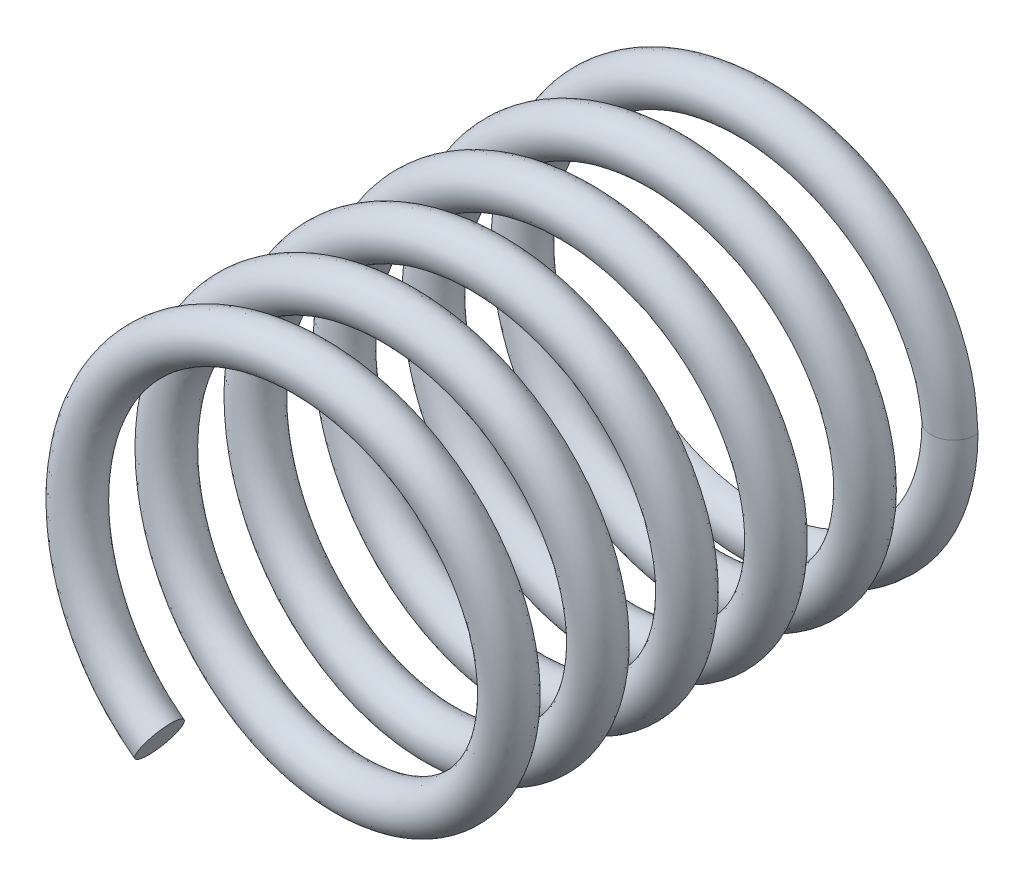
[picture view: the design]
ISO-10303-21;
HEADER;
FILE_DESCRIPTION(('STEP AP214'),'2;1');
FILE_NAME('part.step','',(''),(''),'','','');
FILE_SCHEMA(('AUTOMOTIVE_DESIGN { 1 0 10303 214 1 1 1 1 }'));
ENDSEC;
DATA;
#1=APPLICATION_CONTEXT('core data for automotive mechanical design processes');
#2=APPLICATION_PROTOCOL_DEFINITION('international standard','automotive_design',2000,#1);
#3=PRODUCT_CONTEXT('',#1,'mechanical');
#4=PRODUCT('Part','Part','',(#3));
#5=PRODUCT_RELATED_PRODUCT_CATEGORY('part','',(#4));
#6=PRODUCT_DEFINITION_FORMATION('','',#4);
#7=PRODUCT_DEFINITION_CONTEXT('part definition',#1,'design');
#8=PRODUCT_DEFINITION('design','',#6,#7);
#9=PRODUCT_DEFINITION_SHAPE('','',#8);
#10=(LENGTH_UNIT() NAMED_UNIT(*) SI_UNIT(.MILLI.,.METRE.));
#11=(NAMED_UNIT(*) PLANE_ANGLE_UNIT() SI_UNIT($,.RADIAN.));
#12=(NAMED_UNIT(*) SI_UNIT($,.STERADIAN.) SOLID_ANGLE_UNIT());
#13=UNCERTAINTY_MEASURE_WITH_UNIT(LENGTH_MEASURE(1.E-05),#10,'distance_accuracy_value','');
#14=(GEOMETRIC_REPRESENTATION_CONTEXT(3) GLOBAL_UNCERTAINTY_ASSIGNED_CONTEXT((#13)) GLOBAL_UNIT_ASSIGNED_CONTEXT((#10,
#11,#12)) REPRESENTATION_CONTEXT('',''));
#15=CARTESIAN_POINT('',(0.,0.,0.));
#16=DIRECTION('',(0.,0.,1.));
#17=DIRECTION('',(1.,0.,0.));
#18=AXIS2_PLACEMENT_3D('',#15,#16,#17);
#19=CARTESIAN_POINT('',(6.5,0.,0.75));
#20=CARTESIAN_POINT('',(6.47803879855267,0.400819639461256,0.779446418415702));
#21=CARTESIAN_POINT('',(6.43402565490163,1.20411505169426,0.838460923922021));
#22=CARTESIAN_POINT('',(6.09077083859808,2.36877362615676,0.92702323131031));
#23=CARTESIAN_POINT('',(5.55180292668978,3.45210939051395,1.0156581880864));
#24=CARTESIAN_POINT('',(4.81980996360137,4.41698855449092,1.10417552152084));
#25=CARTESIAN_POINT('',(3.92231791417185,5.22874283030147,1.19270781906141));
#26=CARTESIAN_POINT('',(2.89150520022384,5.86322878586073,1.28123286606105));
#27=CARTESIAN_POINT('',(1.76058421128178,6.29519397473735,1.36980802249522));
#28=CARTESIAN_POINT('',(0.569789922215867,6.51242937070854,1.45832328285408));
#29=CARTESIAN_POINT('',(-0.640762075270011,6.50545141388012,1.54688530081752));
#30=CARTESIAN_POINT('',(-1.82922132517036,6.27588442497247,1.63540445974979));
#31=CARTESIAN_POINT('',(-2.95512377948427,5.83112363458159,1.7239692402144));
#32=CARTESIAN_POINT('',(-3.97933162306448,5.18600612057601,1.81249157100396));
#33=CARTESIAN_POINT('',(-4.86779587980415,4.36377561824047,1.90104849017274));
#34=CARTESIAN_POINT('',(-5.58820585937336,3.39102061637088,1.98957838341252));
#35=CARTESIAN_POINT('',(-6.1186037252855,2.3028796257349,2.07812763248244));
#36=CARTESIAN_POINT('',(-6.43715274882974,1.13504232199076,2.16666656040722));
#37=CARTESIAN_POINT('',(-6.53735656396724,-0.0713012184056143,2.25520603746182));
#38=CARTESIAN_POINT('',(-6.41081294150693,-1.27520680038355,2.34375453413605));
#39=CARTESIAN_POINT('',(-6.06701483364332,-2.43582376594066,2.43228490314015));
#40=CARTESIAN_POINT('',(-5.51278706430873,-3.51206521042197,2.52084187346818));
#41=CARTESIAN_POINT('',(-4.77158359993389,-4.46903238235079,2.6093648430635));
#42=CARTESIAN_POINT('',(-3.86513544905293,-5.27143453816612,2.69792788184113));
#43=CARTESIAN_POINT('',(-2.82732227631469,-5.89439460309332,2.7864463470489));
#44=CARTESIAN_POINT('',(-1.69182218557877,-6.31408899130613,2.8750122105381));
#45=CARTESIAN_POINT('',(-0.498714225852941,-6.51811167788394,2.96352965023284));
#46=CARTESIAN_POINT('',(0.711695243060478,-6.4982025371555,3.05209471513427));
#47=CARTESIAN_POINT('',(1.89753943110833,-6.25544558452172,3.14061474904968));
#48=CARTESIAN_POINT('',(3.01860851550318,-5.79865604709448,3.22917549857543));
#49=CARTESIAN_POINT('',(4.03560159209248,-5.14220099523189,3.31770140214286));
#50=CARTESIAN_POINT('',(4.91518269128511,-4.31049178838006,3.40625489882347));
#51=CARTESIAN_POINT('',(5.62479780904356,-3.32981635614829,3.49478913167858));
#52=CARTESIAN_POINT('',(6.14342757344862,-2.23603196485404,3.58333348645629));
#53=CARTESIAN_POINT('',(6.44911757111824,-1.06474431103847,3.67187724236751));
#54=CARTESIAN_POINT('',(6.53619781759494,0.142601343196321,3.76041204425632));
#55=CARTESIAN_POINT('',(6.3965364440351,1.34507008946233,3.84896500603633));
#56=CARTESIAN_POINT('',(6.04003785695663,2.5018348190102,3.93749136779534));
#57=CARTESIAN_POINT('',(5.47419946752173,3.57202699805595,4.02605173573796));
#58=CARTESIAN_POINT('',(4.72248528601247,4.52074942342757,4.11457204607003));
#59=CARTESIAN_POINT('',(3.80746018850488,5.31336082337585,4.20313693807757));
#60=CARTESIAN_POINT('',(2.76280784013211,5.92477832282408,4.29165443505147));
#61=CARTESIAN_POINT('',(1.62287840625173,6.33228183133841,4.38022035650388));
#62=CARTESIAN_POINT('',(0.427573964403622,6.52303938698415,4.4687386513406));
#63=CARTESIAN_POINT('',(-0.78254677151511,6.49017803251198,4.55730197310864));
#64=CARTESIAN_POINT('',(-1.96563038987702,6.23426179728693,4.64582457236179));
#65=CARTESIAN_POINT('',(-3.08173197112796,5.76549033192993,4.73438200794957));
#66=CARTESIAN_POINT('',(-4.0913981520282,5.09779625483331,4.82291183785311));
#67=CARTESIAN_POINT('',(-4.9619760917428,4.25668531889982,4.91146091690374));
#68=CARTESIAN_POINT('',(-5.66073777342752,3.26822675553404,4.999999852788));
#69=CARTESIAN_POINT('',(-6.1674919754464,2.16890628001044,5.08853938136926));
#70=CARTESIAN_POINT('',(-6.46033993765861,0.994324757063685,5.17708788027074));
#71=CARTESIAN_POINT('',(-6.53422990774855,-0.213884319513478,5.26561823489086));
#72=CARTESIAN_POINT('',(-6.38152240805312,-1.41477755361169,5.35417520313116));
#73=CARTESIAN_POINT('',(-6.01232098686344,-2.56753904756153,5.44269817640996));
#74=CARTESIAN_POINT('',(-5.43497604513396,-3.63157394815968,5.53126121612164));
#75=CARTESIAN_POINT('',(-4.67281556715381,-4.57191794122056,5.61977968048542));
#76=CARTESIAN_POINT('',(-3.7493384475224,-5.35466556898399,5.70834554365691));
#77=CARTESIAN_POINT('',(-2.69796356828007,-5.95445113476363,5.79686298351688));
#78=CARTESIAN_POINT('',(-1.5537413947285,-6.34972708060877,5.88542804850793));
#79=CARTESIAN_POINT('',(-0.356384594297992,-6.52719276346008,5.97394808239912));
#80=CARTESIAN_POINT('',(0.853306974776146,-6.48137921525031,6.06250883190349));
#81=CARTESIAN_POINT('',(2.0334887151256,-6.2123453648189,6.1510347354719));
#82=CARTESIAN_POINT('',(3.14448588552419,-5.73162881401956,6.23958823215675));
#83=CARTESIAN_POINT('',(4.14671672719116,-5.05279801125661,6.32812246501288));
#84=CARTESIAN_POINT('',(5.00816558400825,-4.20235871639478,6.41666681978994));
#85=CARTESIAN_POINT('',(5.69602419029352,-3.206260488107,6.50521057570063));
#86=CARTESIAN_POINT('',(6.19078938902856,-2.10150988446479,6.59374537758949));
#87=CARTESIAN_POINT('',(6.47081915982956,-0.923791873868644,6.6822983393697));
#88=CARTESIAN_POINT('',(6.53145690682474,0.285141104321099,6.77082470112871));
#89=CARTESIAN_POINT('',(6.36577003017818,1.48432092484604,6.85938506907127));
#90=CARTESIAN_POINT('',(5.98387194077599,2.63292977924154,6.94790537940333));
#91=CARTESIAN_POINT('',(5.3951186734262,3.69069787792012,7.0364702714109));
#92=CARTESIAN_POINT('',(4.62258367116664,4.62253453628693,7.1249877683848));
#93=CARTESIAN_POINT('',(3.69077480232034,5.39534140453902,7.2135536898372));
#94=CARTESIAN_POINT('',(2.63279896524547,5.98341306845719,7.30207198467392));
#95=CARTESIAN_POINT('',(1.4844181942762,6.36641916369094,7.39063530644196));
#96=CARTESIAN_POINT('',(0.285154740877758,6.53057499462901,7.4791579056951));
#97=CARTESIAN_POINT('',(-0.923966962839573,6.47180313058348,7.56771534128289));
#98=CARTESIAN_POINT('',(-2.10110764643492,6.1897021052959,7.65624517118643));
#99=CARTESIAN_POINT('',(-3.20686019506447,5.69707155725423,7.74479425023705));
#100=CARTESIAN_POINT('',(-4.20155413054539,5.00721490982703,7.83333318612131));
#101=CARTESIAN_POINT('',(-5.05373706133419,4.14751171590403,7.92187271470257));
#102=CARTESIAN_POINT('',(-5.73065467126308,3.14392602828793,8.01042121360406));
#103=CARTESIAN_POINT('',(-6.213320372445,2.03385273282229,8.09895156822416));
#104=CARTESIAN_POINT('',(-6.48055193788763,0.853153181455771,8.18750853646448));
#105=CARTESIAN_POINT('',(-6.52788373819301,-0.356362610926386,8.27603150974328));
#106=CARTESIAN_POINT('',(-6.34927832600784,-1.55369195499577,8.36459454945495));
#107=CARTESIAN_POINT('',(-5.95469833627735,-2.69800050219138,8.45311301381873));
#108=CARTESIAN_POINT('',(-5.35462915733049,-3.74939044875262,8.54167887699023));
#109=CARTESIAN_POINT('',(-4.57179868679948,-4.67259590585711,8.6301963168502));
#110=CARTESIAN_POINT('',(-3.63177388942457,-5.43538082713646,8.71876138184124));
#111=CARTESIAN_POINT('',(-2.56732337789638,-6.01166416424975,8.80728141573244));
#112=CARTESIAN_POINT('',(-1.41491598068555,-6.3823523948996,8.8958421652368));
#113=CARTESIAN_POINT('',(-0.213892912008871,-6.53318919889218,8.98436806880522));
#114=CARTESIAN_POINT('',(0.994517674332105,-6.46144681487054,9.07292156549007));
#115=CARTESIAN_POINT('',(2.16848040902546,-6.16633765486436,9.1614557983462));
#116=CARTESIAN_POINT('',(3.26884491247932,-5.66181898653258,9.25000015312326));
#117=CARTESIAN_POINT('',(4.25590622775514,-4.96105433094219,9.33854390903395));
#118=CARTESIAN_POINT('',(5.09868039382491,-4.09214800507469,9.42707871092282));
#119=CARTESIAN_POINT('',(5.76462558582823,-3.08123090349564,9.51563167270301));
#120=CARTESIAN_POINT('',(6.23508585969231,-1.96594483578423,9.60415803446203));
#121=CARTESIAN_POINT('',(6.48953477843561,-0.782416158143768,9.69271840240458));
#122=CARTESIAN_POINT('',(6.52351532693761,0.427539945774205,9.78123871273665));
#123=CARTESIAN_POINT('',(6.33204622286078,1.62288229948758,9.86980360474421));
#124=CARTESIAN_POINT('',(5.92480768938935,2.76274486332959,9.95832110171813));
#125=CARTESIAN_POINT('',(5.31350928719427,3.80764317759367,10.0468870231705));
#126=CARTESIAN_POINT('',(4.52046955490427,4.72209882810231,10.1354053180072));
#127=CARTESIAN_POINT('',(3.57234041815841,5.4747761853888,10.2239686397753));
#128=CARTESIAN_POINT('',(2.50154600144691,6.03920446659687,10.3124912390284));
#129=CARTESIAN_POINT('',(1.34524209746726,6.39752095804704,10.4010486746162));
#130=CARTESIAN_POINT('',(0.142607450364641,6.53503853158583,10.4895785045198));
#131=CARTESIAN_POINT('',(-1.06494963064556,6.45030688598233,10.5781275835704));
#132=CARTESIAN_POINT('',(-2.23560105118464,6.14225904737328,10.6666665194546));
#133=CARTESIAN_POINT('',(-3.3304268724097,5.62586602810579,10.7552060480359));
#134=CARTESIAN_POINT('',(-4.30976787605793,4.91432342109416,10.8437545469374));
#135=CARTESIAN_POINT('',(-5.14299270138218,4.0362771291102,10.9322849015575));
#136=CARTESIAN_POINT('',(-5.79793126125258,3.01818105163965,11.0208418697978));
#137=CARTESIAN_POINT('',(-6.25608736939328,1.89779641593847,11.1093648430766));
#138=CARTESIAN_POINT('',(-6.49776393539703,0.711588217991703,11.1979278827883));
#139=CARTESIAN_POINT('',(-6.51835660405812,-0.498664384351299,11.2864463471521));
#140=CARTESIAN_POINT('',(-6.31407256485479,-1.69188350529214,11.3750122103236));
#141=CARTESIAN_POINT('',(-5.89420741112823,-2.82715665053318,11.4635296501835));
#142=CARTESIAN_POINT('',(-5.27176085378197,-3.86544742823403,11.5520947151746));
#143=CARTESIAN_POINT('',(-4.46860507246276,-4.77104014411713,11.6406147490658));
#144=CARTESIAN_POINT('',(-3.51247918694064,-5.51351968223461,11.7291754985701));
#145=CARTESIAN_POINT('',(-2.43547589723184,-6.06603399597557,11.8177014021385));
#146=CARTESIAN_POINT('',(-1.27540404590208,-6.41191896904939,11.9062548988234));
#147=CARTESIAN_POINT('',(-0.071306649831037,-6.53612597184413,11.9947891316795));
#148=CARTESIAN_POINT('',(1.13525330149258,-6.43838032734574,12.0833334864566));
#149=CARTESIAN_POINT('',(2.30246316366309,-6.11747180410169,12.1718772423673));
#150=CARTESIAN_POINT('',(3.39159529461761,-5.58921268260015,12.2604120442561));
#151=CARTESIAN_POINT('',(4.36313308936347,-4.86702801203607,12.3489650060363));
#152=CARTESIAN_POINT('',(5.18667143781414,-3.97990881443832,12.4374913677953));
#153=CARTESIAN_POINT('',(5.83056585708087,-2.95478230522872,12.5260517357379));
#154=CARTESIAN_POINT('',(6.2763264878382,-1.82941751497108,12.61457204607));
#155=CARTESIAN_POINT('',(6.50523554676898,-0.640676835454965,12.7031369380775));
#156=CARTESIAN_POINT('',(6.51241245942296,0.569727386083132,12.7916544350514));
#157=CARTESIAN_POINT('',(6.29535613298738,1.76068698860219,12.8802203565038));
#158=CARTESIAN_POINT('',(5.86290480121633,2.89122977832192,12.9687386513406));
#159=CARTESIAN_POINT('',(5.22938566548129,3.92279440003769,13.0573019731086));
#160=CARTESIAN_POINT('',(4.41621389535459,4.81941675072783,13.1458245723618));
#161=CARTESIAN_POINT('',(3.45219510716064,5.55160334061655,13.2343820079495));
#162=CARTESIAN_POINT('',(2.36912198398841,6.09215286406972,13.3229118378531));
#163=CARTESIAN_POINT('',(1.20540957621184,6.42554000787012,13.4114609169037));
#164=CARTESIAN_POINT('',(-1.49109357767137E-06,6.53645609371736,13.499999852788));
#165=CARTESIAN_POINT('',(-1.20541805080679,6.4256578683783,13.5885393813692));
#166=CARTESIAN_POINT('',(-2.36905946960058,6.0919808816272,13.6770878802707));
#167=CARTESIAN_POINT('',(-3.45234420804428,5.55186693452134,13.7656182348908));
#168=CARTESIAN_POINT('',(-4.41599450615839,4.81917174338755,13.8541752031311));
#169=CARTESIAN_POINT('',(-5.22971453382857,3.92305318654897,13.9426981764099));
#170=CARTESIAN_POINT('',(-5.86252331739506,2.89104034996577,14.0312612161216));
#171=CARTESIAN_POINT('',(-6.29580486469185,1.76081801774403,14.1197796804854));
#172=CARTESIAN_POINT('',(-6.51194563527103,0.569689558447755,14.2083455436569));
#173=CARTESIAN_POINT('',(-6.50568773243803,-0.640720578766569,14.2968629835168));
#174=CARTESIAN_POINT('',(-6.27589565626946,-1.82928402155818,14.3854280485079));
#175=CARTESIAN_POINT('',(-5.83090704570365,-2.95495826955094,14.473948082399));
#176=CARTESIAN_POINT('',(-5.18638556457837,-3.97967512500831,14.5625088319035));
#177=CARTESIAN_POINT('',(-4.36330454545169,-4.86722556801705,14.6510347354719));
#178=CARTESIAN_POINT('',(-3.39149321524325,-5.58901906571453,14.7395882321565));
#179=CARTESIAN_POINT('',(-2.3024930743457,-6.11756103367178,14.8281224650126));
#180=CARTESIAN_POINT('',(-1.13526661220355,-6.43837798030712,14.9166668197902));
#181=CARTESIAN_POINT('',(0.0713090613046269,-6.53603189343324,15.0052105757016));
#182=CARTESIAN_POINT('',(1.27543374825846,-6.4121358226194,15.0937453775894));
#183=CARTESIAN_POINT('',(2.43538234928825,-6.06578971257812,15.1822983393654));
#184=CARTESIAN_POINT('',(3.51266789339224,-5.51383705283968,15.2708247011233));
#185=CARTESIAN_POINT('',(4.46834464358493,-4.77075809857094,15.3593850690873));
#186=CARTESIAN_POINT('',(5.27212004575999,-3.86572022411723,15.4479053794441));
#187=CARTESIAN_POINT('',(5.89379745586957,-2.82696088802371,15.5364702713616));
#188=CARTESIAN_POINT('',(6.31452417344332,-1.69200762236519,15.6249877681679));
#189=CARTESIAN_POINT('',(6.51789012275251,-0.498634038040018,15.7135536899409));
#190=CARTESIAN_POINT('',(6.49818720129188,0.711635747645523,15.8020719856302));
#191=CARTESIAN_POINT('',(6.25568981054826,1.89766571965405,15.8906353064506));
#192=CARTESIAN_POINT('',(5.79822122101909,3.0183362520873,15.9791579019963));
#193=CARTESIAN_POINT('',(5.14276249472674,4.036080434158,16.0677153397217));
#194=CARTESIAN_POINT('',(4.30988543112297,4.91446361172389,16.1562451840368));
#195=CARTESIAN_POINT('',(3.33037839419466,5.62575801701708,16.244794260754));
#196=CARTESIAN_POINT('',(2.23559824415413,6.14226028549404,16.3333331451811));
#197=CARTESIAN_POINT('',(1.06498238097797,6.45042149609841,16.4218726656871));
#198=CARTESIAN_POINT('',(-0.142607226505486,6.53485456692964,16.5104213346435));
#199=CARTESIAN_POINT('',(-1.34529177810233,6.39781606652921,16.5989517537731));
#200=CARTESIAN_POINT('',(-2.50142564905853,6.03890224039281,16.687508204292));
#201=CARTESIAN_POINT('',(-3.57256720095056,5.47514244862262,16.7760309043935));
#202=CARTESIAN_POINT('',(-4.52016795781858,4.72178283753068,16.8645954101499));
#203=CARTESIAN_POINT('',(-5.313853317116,3.80789649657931,16.9531147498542));
#204=CARTESIAN_POINT('',(-5.92440386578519,2.76256665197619,17.0416766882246));
#205=CARTESIAN_POINT('',(-6.33260379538,1.62302507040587,17.1301918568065));
#206=CARTESIAN_POINT('',(-6.52301737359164,0.427468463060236,17.2187672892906));
#207=CARTESIAN_POINT('',(-6.48959308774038,-0.782443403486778,17.3072919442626));
#208=CARTESIAN_POINT('',(-6.23484691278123,-1.96563514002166,17.3958249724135));
#209=CARTESIAN_POINT('',(-5.765579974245,-3.0815324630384,17.4843401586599));
#210=CARTESIAN_POINT('',(-5.09797767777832,-4.09263332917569,17.5729822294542));
#211=CARTESIAN_POINT('',(-4.25486215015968,-4.96096647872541,17.6615197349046));
#212=CARTESIAN_POINT('',(-3.59661837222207,-5.42889327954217,17.7205943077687));
#213=CARTESIAN_POINT('',(-3.24993433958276,-5.62905139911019,17.7499999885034));
#214=CARTESIAN_POINT('',(8.,0.,0.75));
#215=CARTESIAN_POINT('',(7.97295207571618,0.493790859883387,0.779474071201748));
#216=CARTESIAN_POINT('',(7.91874446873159,1.48341285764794,0.838543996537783));
#217=CARTESIAN_POINT('',(7.49731211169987,2.91277065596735,0.926948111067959));
#218=CARTESIAN_POINT('',(6.83246371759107,4.24994089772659,1.01627020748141));
#219=CARTESIAN_POINT('',(5.93260444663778,5.43560340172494,1.103905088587));
#220=CARTESIAN_POINT('',(4.82616965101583,6.43653315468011,1.19308333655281));
#221=CARTESIAN_POINT('',(3.56093396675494,7.21523217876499,1.28090952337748));
#222=CARTESIAN_POINT('',(2.16491457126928,7.74863220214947,1.37048079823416));
#223=CARTESIAN_POINT('',(0.703343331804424,8.01512891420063,1.45798266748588));
#224=CARTESIAN_POINT('',(-0.790784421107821,8.00660569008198,1.54745582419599));
#225=CARTESIAN_POINT('',(-2.2494462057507,7.72477534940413,1.63509786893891));
#226=CARTESIAN_POINT('',(-3.63881967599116,7.17597396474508,1.7245404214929));
#227=CARTESIAN_POINT('',(-4.89648252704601,6.38376586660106,1.81229025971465));
#228=CARTESIAN_POINT('',(-5.99209324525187,5.36979751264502,1.90148160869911));
#229=CARTESIAN_POINT('',(-6.87743679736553,4.17434793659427,1.98952237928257));
#230=CARTESIAN_POINT('',(-7.53079320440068,2.83382067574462,2.07837975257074));
#231=CARTESIAN_POINT('',(-7.92276623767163,1.39700622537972,2.16679821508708));
#232=CARTESIAN_POINT('',(-8.04597328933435,-0.0872066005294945,2.25521790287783));
#233=CARTESIAN_POINT('',(-7.89021161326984,-1.57032986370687,2.34407206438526));
#234=CARTESIAN_POINT('',(-7.46759523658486,-2.99662700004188,2.43210914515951));
#235=CARTESIAN_POINT('',(-6.78429262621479,-4.32389491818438,2.52130818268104));
#236=CARTESIAN_POINT('',(-5.87402862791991,-5.4989225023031,2.60907094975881));
#237=CARTESIAN_POINT('',(-4.75560388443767,-6.48919421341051,2.69849283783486));
#238=CARTESIAN_POINT('',(-3.48173292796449,-7.2537082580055,2.7861022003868));
#239=CARTESIAN_POINT('',(-2.08020057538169,-7.77186524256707,2.87562009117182));
#240=CARTESIAN_POINT('',(-0.615901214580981,-8.02216582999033,2.96319856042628));
#241=CARTESIAN_POINT('',(0.877999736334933,-7.9976576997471,3.05268457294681));
#242=CARTESIAN_POINT('',(2.33375040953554,-7.6995901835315,3.14035513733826));
#243=CARTESIAN_POINT('',(3.7167401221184,-7.13608085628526,3.22968170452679));
#244=CARTESIAN_POINT('',(4.96599562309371,-6.32968645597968,3.31756631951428));
#245=CARTESIAN_POINT('',(6.05013771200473,-5.3044901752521,3.40660784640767));
#246=CARTESIAN_POINT('',(6.92269785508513,-4.09867415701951,3.49482466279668));
#247=CARTESIAN_POINT('',(7.56114144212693,-2.75204742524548,3.58346480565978));
#248=CARTESIAN_POINT('',(7.93757563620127,-1.31005914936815,3.67210435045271));
#249=CARTESIAN_POINT('',(8.0445540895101,0.174494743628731,3.76032173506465));
#250=CARTESIAN_POINT('',(7.87256467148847,1.65667121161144,3.8493627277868));
#251=CARTESIAN_POINT('',(7.43452501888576,3.07759402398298,3.93724780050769));
#252=CARTESIAN_POINT('',(6.73664555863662,4.39789819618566,4.02657398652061));
#253=CARTESIAN_POINT('',(5.81372635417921,5.56248653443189,4.11424482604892));
#254=CARTESIAN_POINT('',(4.68449301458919,6.54084800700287,4.2037306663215));
#255=CARTESIAN_POINT('',(3.40235088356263,7.29113640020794,4.2913091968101));
#256=CARTESIAN_POINT('',(1.99533934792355,7.79421871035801,4.38082714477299));
#257=CARTESIAN_POINT('',(0.528216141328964,8.02827827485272,4.46843632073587));
#258=CARTESIAN_POINT('',(-0.96504926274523,7.98775983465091,4.55785848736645));
#259=CARTESIAN_POINT('',(-2.41780695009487,7.67347355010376,4.6456209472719));
#260=CARTESIAN_POINT('',(-3.79414503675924,7.09537497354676,4.73482049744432));
#261=CARTESIAN_POINT('',(-5.03496605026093,6.2748254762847,4.82285682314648));
#262=CARTESIAN_POINT('',(-6.10740772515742,5.2386037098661,4.91171122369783));
#263=CARTESIAN_POINT('',(-6.96716080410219,4.02250216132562,5.00013117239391));
#264=CARTESIAN_POINT('',(-7.59056795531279,2.66993739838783,5.08855171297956));
#265=CARTESIAN_POINT('',(-7.95145798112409,1.22298393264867,5.177405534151));
#266=CARTESIAN_POINT('',(-8.04215098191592,-0.261840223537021,5.26544238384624));
#267=CARTESIAN_POINT('',(-7.85400891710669,-1.74276742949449,5.35464146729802));
#268=CARTESIAN_POINT('',(-7.40052360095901,-3.15826080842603,5.44240430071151));
#269=CARTESIAN_POINT('',(-6.68824100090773,-4.47133558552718,5.53182618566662));
#270=CARTESIAN_POINT('',(-5.75267308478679,-5.62543332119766,5.61943553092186));
#271=CARTESIAN_POINT('',(-4.61288359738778,-6.59169392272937,5.70895342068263));
#272=CARTESIAN_POINT('',(-3.32250013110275,-7.32771941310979,5.79653189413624));
#273=CARTESIAN_POINT('',(-1.91031015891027,-7.81563351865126,5.88601790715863));
#274=CARTESIAN_POINT('',(-0.440406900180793,-8.03343772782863,5.97368847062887));
#275=CARTESIAN_POINT('',(1.05190986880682,-7.97692251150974,6.06301503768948));
#276=CARTESIAN_POINT('',(2.50162917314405,-7.64643018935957,6.15089965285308));
#277=CARTESIAN_POINT('',(3.87102727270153,-7.05385924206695,6.23994117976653));
#278=CARTESIAN_POINT('',(5.10337896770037,-6.21919597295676,6.32815799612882));
#279=CARTESIAN_POINT('',(6.16389316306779,-5.17214133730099,6.41679813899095));
#280=CARTESIAN_POINT('',(7.010814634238,-3.94586367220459,6.50543768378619));
#281=CARTESIAN_POINT('',(7.61908883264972,-2.58742811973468,6.59365506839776));
#282=CARTESIAN_POINT('',(7.96440585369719,-1.13581398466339,6.68269606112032));
#283=CARTESIAN_POINT('',(8.03876744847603,0.349235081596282,6.77058113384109));
#284=CARTESIAN_POINT('',(7.83454589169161,1.82860400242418,6.85990731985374));
#285=CARTESIAN_POINT('',(7.36559819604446,3.23861602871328,6.94757815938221));
#286=CARTESIAN_POINT('',(6.63908529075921,4.54419563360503,7.03706399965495));
#287=CARTESIAN_POINT('',(5.6908795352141,5.6877545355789,7.12464253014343));
#288=CARTESIAN_POINT('',(4.54078546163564,6.64172355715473,7.21416047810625));
#289=CARTESIAN_POINT('',(3.24219369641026,7.36345329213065,7.30176965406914));
#290=CARTESIAN_POINT('',(1.82512509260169,7.83610526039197,7.39119182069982));
#291=CARTESIAN_POINT('',(0.352487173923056,8.03764515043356,7.47895428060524));
#292=CARTESIAN_POINT('',(-1.13856892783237,7.96514553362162,7.56815383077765));
#293=CARTESIAN_POINT('',(-2.5852037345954,7.61846700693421,7.65619015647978));
#294=CARTESIAN_POINT('',(-3.94737797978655,7.01153371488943,7.74504455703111));
#295=CARTESIAN_POINT('',(-5.17121282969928,6.16282493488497,7.83346450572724));
#296=CARTESIAN_POINT('',(-6.21962832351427,5.10504761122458,7.92188504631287));
#297=CARTESIAN_POINT('',(-7.05364124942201,3.86878777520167,8.01073886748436));
#298=CARTESIAN_POINT('',(-7.64670456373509,2.50452830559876,8.09877571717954));
#299=CARTESIAN_POINT('',(-7.97641578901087,1.04856356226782,8.1879748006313));
#300=CARTESIAN_POINT('',(-8.03440623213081,-0.436666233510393,8.27573763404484));
#301=CARTESIAN_POINT('',(-7.81417755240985,-1.91416790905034,8.36515951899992));
#302=CARTESIAN_POINT('',(-7.32975595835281,-3.31864810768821,8.45276886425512));
#303=CARTESIAN_POINT('',(-6.58918477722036,-4.61646702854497,8.54228675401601));
#304=CARTESIAN_POINT('',(-5.62835649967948,-5.74944188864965,8.62986522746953));
#305=CARTESIAN_POINT('',(-4.46820845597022,-6.69092858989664,8.71935124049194));
#306=CARTESIAN_POINT('',(-3.16144463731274,-7.39833412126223,8.80702180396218));
#307=CARTESIAN_POINT('',(-1.73979623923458,-7.8556295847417,8.89634837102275));
#308=CARTESIAN_POINT('',(-0.264470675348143,-8.04090159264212,8.98423298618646));
#309=CARTESIAN_POINT('',(1.22501381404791,-7.95242878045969,9.07327451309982));
#310=CARTESIAN_POINT('',(2.66851725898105,-7.58959096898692,9.16149132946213));
#311=CARTESIAN_POINT('',(4.02318839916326,-6.96839867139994,9.25013147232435));
#312=CARTESIAN_POINT('',(5.23844591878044,-6.10573880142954,9.33877101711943));
#313=CARTESIAN_POINT('',(6.27464901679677,-5.03726896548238,9.42698840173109));
#314=CARTESIAN_POINT('',(7.09562214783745,-3.79130325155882,9.51602939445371));
#315=CARTESIAN_POINT('',(7.67341588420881,-2.42124676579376,9.60391446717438));
#316=CARTESIAN_POINT('',(7.98748436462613,-0.961246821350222,9.69324065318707));
#317=CARTESIAN_POINT('',(8.02907019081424,0.524120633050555,9.78091149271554));
#318=CARTESIAN_POINT('',(7.79290589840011,1.99944620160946,9.87039733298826));
#319=CARTESIAN_POINT('',(7.29300412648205,3.39834553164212,9.95797586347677));
#320=CARTESIAN_POINT('',(6.53854583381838,4.68813852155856,10.0474938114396));
#321=CARTESIAN_POINT('',(5.5651148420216,5.81048716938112,10.1351029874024));
#322=CARTESIAN_POINT('',(4.39516242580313,6.73930074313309,10.2245251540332));
#323=CARTESIAN_POINT('',(3.08026614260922,7.43235812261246,10.3122876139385));
#324=CARTESIAN_POINT('',(1.65433539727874,7.87420198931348,10.4014871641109));
#325=CARTESIAN_POINT('',(0.17637230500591,8.0432089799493,10.4895234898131));
#326=CARTESIAN_POINT('',(-1.31123619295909,7.93876927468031,10.5783778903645));
#327=CARTESIAN_POINT('',(-2.75154026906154,7.55982006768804,10.6667978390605));
#328=CARTESIAN_POINT('',(-4.0985097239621,6.9244137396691,10.7552183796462));
#329=CARTESIAN_POINT('',(-5.30505128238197,6.04795871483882,10.8440722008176));
#330=CARTESIAN_POINT('',(-6.32895272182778,4.9688137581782,10.9321090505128));
#331=CARTESIAN_POINT('',(-7.13674919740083,3.71342231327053,11.0213081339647));
#332=CARTESIAN_POINT('',(-7.69922089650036,2.33759673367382,11.1090709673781));
#333=CARTESIAN_POINT('',(-7.99760896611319,0.873876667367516,11.1984928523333));
#334=CARTESIAN_POINT('',(-8.02276208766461,-0.611584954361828,11.2861021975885));
#335=CARTESIAN_POINT('',(-7.77073302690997,-2.08442607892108,11.3756200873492));
#336=CARTESIAN_POINT('',(-7.25535000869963,-3.47769681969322,11.463198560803));
#337=CARTESIAN_POINT('',(-6.48717486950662,-4.75919892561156,11.5526845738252));
#338=CARTESIAN_POINT('',(-5.50116549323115,-5.87088223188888,11.6403551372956));
#339=CARTESIAN_POINT('',(-4.32165724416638,-6.78683179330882,11.7296817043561));
#340=CARTESIAN_POINT('',(-2.99867145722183,-7.46552159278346,11.8175663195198));
#341=CARTESIAN_POINT('',(-1.56875438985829,-7.89181804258,11.9066078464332));
#342=CARTESIAN_POINT('',(-0.0882070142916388,-8.04456928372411,11.9948246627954));
#343=CARTESIAN_POINT('',(1.39722773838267,-7.9241642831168,12.0834648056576));
#344=CARTESIAN_POINT('',(2.83424331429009,-7.5291717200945,12.1721043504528));
#345=CARTESIAN_POINT('',(4.17339392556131,-6.87954083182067,12.2603217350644));
#346=CARTESIAN_POINT('',(5.37100169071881,-5.9895053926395,12.349362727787));
#347=CARTESIAN_POINT('',(6.3825371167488,-4.89969051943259,12.4372478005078));
#348=CARTESIAN_POINT('',(7.17701434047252,-3.63515709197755,12.5265739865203));
#349=CARTESIAN_POINT('',(7.72411782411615,-2.25359144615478,12.6142448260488));
#350=CARTESIAN_POINT('',(8.00678704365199,-0.786465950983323,12.7037306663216));
#351=CARTESIAN_POINT('',(8.01548478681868,0.699045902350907,12.7913091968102));
#352=CARTESIAN_POINT('',(7.74766107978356,2.1690947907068,12.8808271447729));
#353=CARTESIAN_POINT('',(7.21680100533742,3.55669054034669,12.9684363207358));
#354=CARTESIAN_POINT('',(6.43507830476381,4.82963709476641,13.0578584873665));
#355=CARTESIAN_POINT('',(5.43651955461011,5.93061901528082,13.1456209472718));
#356=CARTESIAN_POINT('',(4.24770245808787,6.83351347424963,13.2348204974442));
#357=CARTESIAN_POINT('',(2.91667524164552,7.49782124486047,13.3228568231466));
#358=CARTESIAN_POINT('',(1.48306003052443,7.90847209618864,13.4117112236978));
#359=CARTESIAN_POINT('',(8.6564343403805E-06,8.04498932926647,13.5001311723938));
#360=CARTESIAN_POINT('',(-1.48305036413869,7.90859337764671,13.5885517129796));
#361=CARTESIAN_POINT('',(-2.91659383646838,7.49765657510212,13.6774055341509));
#362=CARTESIAN_POINT('',(-4.24783577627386,6.8337869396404,13.7654423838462));
#363=CARTESIAN_POINT('',(-5.43628532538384,5.93038752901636,13.854641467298));
#364=CARTESIAN_POINT('',(-6.43539589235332,4.82991103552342,13.9424043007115));
#365=CARTESIAN_POINT('',(-7.21641070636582,3.55651882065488,14.0318261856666));
#366=CARTESIAN_POINT('',(-7.74810470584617,2.16924437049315,14.1194355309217));
#367=CARTESIAN_POINT('',(-8.0150161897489,0.699027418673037,14.2089534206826));
#368=CARTESIAN_POINT('',(-8.00724122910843,-0.786490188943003,14.2965318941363));
#369=CARTESIAN_POINT('',(-7.72369225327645,-2.2534396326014,14.3860179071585));
#370=CARTESIAN_POINT('',(-7.17736460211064,-3.63531530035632,14.4736884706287));
#371=CARTESIAN_POINT('',(-6.38226260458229,-4.89944192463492,14.5630150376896));
#372=CARTESIAN_POINT('',(-5.37118820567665,-5.98968950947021,14.6508996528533));
#373=CARTESIAN_POINT('',(-4.17330766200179,-6.87933757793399,14.7399411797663));
#374=CARTESIAN_POINT('',(-2.83429221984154,-7.52925381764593,14.8281579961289));
#375=CARTESIAN_POINT('',(-1.39725920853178,-7.92415873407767,14.9167981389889));
#376=CARTESIAN_POINT('',(0.088189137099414,-8.04447541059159,15.005437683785));
#377=CARTESIAN_POINT('',(1.56876593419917,-7.89203854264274,15.0936550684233));
#378=CARTESIAN_POINT('',(2.99855916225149,-7.46528478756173,15.1826960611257));
#379=CARTESIAN_POINT('',(4.32183017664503,-6.78715928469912,15.2705811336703));
#380=CARTESIAN_POINT('',(5.50089046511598,-5.87061376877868,15.359907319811));
#381=CARTESIAN_POINT('',(6.48752285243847,-4.7594871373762,15.447578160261));
#382=CARTESIAN_POINT('',(7.25493150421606,-3.47751869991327,15.5370640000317));
#383=CARTESIAN_POINT('',(7.77117968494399,-2.08456897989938,15.6246425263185));
#384=CARTESIAN_POINT('',(8.02229405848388,-0.611573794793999,15.7141604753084));
#385=CARTESIAN_POINT('',(7.99803446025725,0.873904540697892,15.8017696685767));
#386=CARTESIAN_POINT('',(7.69882874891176,2.3374479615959,15.8911918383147));
#387=CARTESIAN_POINT('',(7.13704847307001,3.7135597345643,15.9789542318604));
#388=CARTESIAN_POINT('',(6.32873399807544,4.96860235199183,16.0681537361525));
#389=CARTESIAN_POINT('',(5.30518408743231,6.04808557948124,16.1561902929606));
#390=CARTESIAN_POINT('',(4.09847709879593,6.92429631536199,16.2450450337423));
#391=CARTESIAN_POINT('',(2.75155666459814,7.55981431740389,16.333464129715));
#392=CARTESIAN_POINT('',(1.31128690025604,7.93888099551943,16.4218831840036));
#393=CARTESIAN_POINT('',(-0.176352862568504,8.04302538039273,16.510739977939));
#394=CARTESIAN_POINT('',(-1.65436541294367,7.87450097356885,16.5987812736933));
#395=CARTESIAN_POINT('',(-3.08012197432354,7.43206571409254,16.6879721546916));
#396=CARTESIAN_POINT('',(-4.39537808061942,6.73967606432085,16.7757223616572));
#397=CARTESIAN_POINT('',(-5.56481727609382,5.81016717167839,16.8651646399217));
#398=CARTESIAN_POINT('',(-6.53886971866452,4.68841307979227,16.9528068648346));
#399=CARTESIAN_POINT('',(-7.2925446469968,3.39827103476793,17.0422799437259));
#400=CARTESIAN_POINT('',(-7.79349204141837,1.99961168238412,17.1297817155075));
#401=CARTESIAN_POINT('',(-8.02854961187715,0.523714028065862,17.2193532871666));
#402=CARTESIAN_POINT('',(-7.98768554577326,-0.961165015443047,17.3071790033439));
#403=CARTESIAN_POINT('',(-7.67269823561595,-2.42047340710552,17.3963582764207));
#404=CARTESIAN_POINT('',(-7.09946791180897,-3.78998300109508,17.4839899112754));
#405=CARTESIAN_POINT('',(-6.26263456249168,-5.04507880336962,17.5733232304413));
#406=CARTESIAN_POINT('',(-5.27545103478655,-6.08339191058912,17.6616872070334));
#407=CARTESIAN_POINT('',(-4.34665518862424,-6.7279101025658,17.7208552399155));
#408=CARTESIAN_POINT('',(-3.99995103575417,-6.92807983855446,17.7502626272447));
#409=CARTESIAN_POINT('',(8.,0.,-0.75));
#410=CARTESIAN_POINT('',(7.97297969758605,0.49379359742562,-0.720525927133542));
#411=CARTESIAN_POINT('',(7.91882744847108,1.48342108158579,-0.661455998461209));
#412=CARTESIAN_POINT('',(7.49723522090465,2.91277308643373,-0.573051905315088));
#413=CARTESIAN_POINT('',(6.83298316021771,4.25025413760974,-0.483729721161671));
#414=CARTESIAN_POINT('',(5.93240777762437,5.43542817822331,-0.396094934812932));
#415=CARTESIAN_POINT('',(4.8263973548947,6.43682450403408,-0.306916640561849));
#416=CARTESIAN_POINT('',(3.56078166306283,7.21495599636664,-0.219090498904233));
#417=CARTESIAN_POINT('',(2.16509163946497,7.74927322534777,-0.129519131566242));
#418=CARTESIAN_POINT('',(0.70331340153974,8.0147988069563,-0.042017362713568));
#419=CARTESIAN_POINT('',(-0.790844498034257,8.00716571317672,0.0474558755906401));
#420=CARTESIAN_POINT('',(-2.24936015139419,7.72449000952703,0.135097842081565));
#421=CARTESIAN_POINT('',(-3.63908648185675,7.17647217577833,0.224540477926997));
#422=CARTESIAN_POINT('',(-4.89635885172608,6.3836157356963,0.312290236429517));
#423=CARTESIAN_POINT('',(-5.99242339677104,5.37007225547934,0.401481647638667));
#424=CARTESIAN_POINT('',(-6.87738836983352,4.17432785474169,0.489522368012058));
#425=CARTESIAN_POINT('',(-7.5310346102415,2.8338926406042,0.578379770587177));
#426=CARTESIAN_POINT('',(-7.92289544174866,1.39703592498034,0.666798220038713));
#427=CARTESIAN_POINT('',(-8.04598732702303,-0.0872241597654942,0.755217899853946));
#428=CARTESIAN_POINT('',(-7.89052191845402,-1.57038371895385,0.844072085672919));
#429=CARTESIAN_POINT('',(-7.46743123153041,-2.99657828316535,0.932109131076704));
#430=CARTESIAN_POINT('',(-6.78468486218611,-4.32413701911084,1.02130821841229));
#431=CARTESIAN_POINT('',(-5.87381171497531,-5.49873540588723,1.10907092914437));
#432=CARTESIAN_POINT('',(-4.75593589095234,-6.48964255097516,1.19849288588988));
#433=CARTESIAN_POINT('',(-3.48158266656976,-7.25340850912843,1.28610217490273));
#434=CARTESIAN_POINT('',(-2.08035295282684,-7.7724458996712,1.37562014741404));
#435=CARTESIAN_POINT('',(-0.615876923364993,-8.02184463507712,1.46319853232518));
#436=CARTESIAN_POINT('',(0.878072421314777,-7.99823617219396,1.55268463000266));
#437=CARTESIAN_POINT('',(2.33367235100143,-7.69935081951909,1.64035511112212));
#438=CARTESIAN_POINT('',(3.71698425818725,-7.13651865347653,1.72968175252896));
#439=CARTESIAN_POINT('',(4.96590966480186,-6.32958940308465,1.81756630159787));
#440=CARTESIAN_POINT('',(6.05041252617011,-5.30470843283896,1.90660787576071));
#441=CARTESIAN_POINT('',(6.92272685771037,-4.09869984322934,1.99482465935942));
#442=CARTESIAN_POINT('',(7.56127161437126,-2.75207595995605,2.08346481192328));
#443=CARTESIAN_POINT('',(7.93779752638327,-1.31010313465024,2.17210436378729));
#444=CARTESIAN_POINT('',(8.0444673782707,0.174509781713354,2.26032172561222));
#445=CARTESIAN_POINT('',(7.87295134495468,1.6567448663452,2.3493627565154));
#446=CARTESIAN_POINT('',(7.43430075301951,3.07751639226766,2.43724778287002));
#447=CARTESIAN_POINT('',(6.73708025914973,4.39817599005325,2.52657402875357));
#448=CARTESIAN_POINT('',(5.81348990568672,5.56227252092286,2.61424480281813));
#449=CARTESIAN_POINT('',(4.6848344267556,6.54132459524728,2.70373071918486));
#450=CARTESIAN_POINT('',(3.40220635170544,7.29083288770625,2.79130916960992));
#451=CARTESIAN_POINT('',(1.99548213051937,7.79480089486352,2.88082720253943));
#452=CARTESIAN_POINT('',(0.528199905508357,8.02798496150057,2.96843629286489));
#453=CARTESIAN_POINT('',(-0.965127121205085,7.98830478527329,3.05785854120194));
#454=CARTESIAN_POINT('',(-2.41774128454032,7.67328800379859,3.14562092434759));
#455=CARTESIAN_POINT('',(-3.79436412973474,7.09575065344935,3.23482053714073));
#456=CARTESIAN_POINT('',(-5.03492810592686,6.27479074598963,3.32285681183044));
#457=CARTESIAN_POINT('',(-6.10760849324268,5.23875281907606,3.41171124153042));
#458=CARTESIAN_POINT('',(-6.96727174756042,4.02257413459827,3.50013117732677));
#459=CARTESIAN_POINT('',(-7.59058760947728,2.66992580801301,3.58855170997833));
#460=CARTESIAN_POINT('',(-7.95176811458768,1.22303946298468,3.67740555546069));
#461=CARTESIAN_POINT('',(-8.04198011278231,-0.261850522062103,3.76544236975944));
#462=CARTESIAN_POINT('',(-7.85446025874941,-1.74286076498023,3.85464150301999));
#463=CARTESIAN_POINT('',(-7.40025579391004,-3.1581591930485,3.94240428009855));
#464=CARTESIAN_POINT('',(-6.68870633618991,-4.47164334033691,4.03182623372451));
#465=CARTESIAN_POINT('',(-5.75242936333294,-5.62520303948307,4.11943550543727));
#466=CARTESIAN_POINT('',(-4.61322537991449,-6.59218744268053,4.20895347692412));
#467=CARTESIAN_POINT('',(-3.32236744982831,-7.3274258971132,4.29653186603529));
#468=CARTESIAN_POINT('',(-1.91043970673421,-7.81620196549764,4.38601796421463));
#469=CARTESIAN_POINT('',(-0.440398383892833,-8.03318610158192,4.47368844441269));
#470=CARTESIAN_POINT('',(1.05198954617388,-7.97741740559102,4.56301508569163));
#471=CARTESIAN_POINT('',(2.50158159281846,-7.64630959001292,4.65089963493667));
#472=CARTESIAN_POINT('',(3.87121086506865,-7.054158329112,4.73994120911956));
#473=CARTESIAN_POINT('',(5.10339743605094,-6.21923002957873,4.82815799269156));
#474=CARTESIAN_POINT('',(6.16400572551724,-5.17221267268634,4.91679814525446));
#475=CARTESIAN_POINT('',(7.01100809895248,-3.94598089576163,5.00543769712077));
#476=CARTESIAN_POINT('',(7.61901249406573,-2.58738433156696,5.09365505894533));
#477=CARTESIAN_POINT('',(7.96479439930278,-1.13587702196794,5.18269608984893));
#478=CARTESIAN_POINT('',(8.03853015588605,0.349238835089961,5.27058111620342));
#479=CARTESIAN_POINT('',(7.83504938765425,1.82871636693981,5.35990736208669));
#480=CARTESIAN_POINT('',(7.36530281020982,3.23849579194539,5.44757813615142));
#481=CARTESIAN_POINT('',(6.63956911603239,4.54452671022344,5.53706405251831));
#482=CARTESIAN_POINT('',(5.6906399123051,5.68751875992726,5.62464250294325));
#483=CARTESIAN_POINT('',(4.5411187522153,6.64222179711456,5.7141605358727));
#484=CARTESIAN_POINT('',(3.24207812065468,7.3631832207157,5.80176962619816));
#485=CARTESIAN_POINT('',(1.82523831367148,7.83664397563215,5.89119187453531));
#486=CARTESIAN_POINT('',(0.352485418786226,8.03744833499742,5.97895425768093));
#487=CARTESIAN_POINT('',(-1.13864631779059,7.96557349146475,6.06815387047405));
#488=CARTESIAN_POINT('',(-2.58517995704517,7.61842139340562,6.15619014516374));
#489=CARTESIAN_POINT('',(-3.94751564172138,7.011742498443,6.24504457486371));
#490=CARTESIAN_POINT('',(-5.1712924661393,6.16293051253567,6.3334645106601));
#491=CARTESIAN_POINT('',(-6.21965075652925,5.10504344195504,6.42188504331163));
#492=CARTESIAN_POINT('',(-7.05391368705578,3.86894602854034,6.51073888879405));
#493=CARTESIAN_POINT('',(-7.64654752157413,2.50446018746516,6.59877570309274));
#494=CARTESIAN_POINT('',(-7.97687183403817,1.04863022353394,6.68797483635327));
#495=CARTESIAN_POINT('',(-8.03411982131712,-0.436662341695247,6.77573761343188));
#496=CARTESIAN_POINT('',(-7.81472008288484,-1.91429794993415,6.86515956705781));
#497=CARTESIAN_POINT('',(-7.32944817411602,-3.31851507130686,6.95276883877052));
#498=CARTESIAN_POINT('',(-6.58967474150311,-4.61681388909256,7.0422868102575));
#499=CARTESIAN_POINT('',(-5.62813143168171,-5.74921145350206,7.12986519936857));
#500=CARTESIAN_POINT('',(-4.46852461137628,-6.69141844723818,7.21935129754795));
#501=CARTESIAN_POINT('',(-3.16135057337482,-7.39810058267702,7.307021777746));
#502=CARTESIAN_POINT('',(-1.73989063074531,-7.85612188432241,7.3963484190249));
#503=CARTESIAN_POINT('',(-0.264474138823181,-8.04077199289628,7.48423296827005));
#504=CARTESIAN_POINT('',(1.22508404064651,-7.95277262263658,7.57327454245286));
#505=CARTESIAN_POINT('',(2.66852296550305,-7.58962928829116,7.66149132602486));
#506=CARTESIAN_POINT('',(4.02326977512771,-6.96850420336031,7.75013147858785));
#507=CARTESIAN_POINT('',(5.23858762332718,-6.10591512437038,7.838771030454));
#508=CARTESIAN_POINT('',(6.27459225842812,-5.03720170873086,7.92698839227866));
#509=CARTESIAN_POINT('',(7.09596570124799,-3.79149537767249,8.01602942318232));
#510=CARTESIAN_POINT('',(7.67319418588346,-2.42116207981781,8.10391444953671));
#511=CARTESIAN_POINT('',(7.98799592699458,-0.96131343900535,8.19324069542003));
#512=CARTESIAN_POINT('',(8.02875149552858,0.524108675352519,8.28091146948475));
#513=CARTESIAN_POINT('',(7.79347378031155,1.99959183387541,8.37039738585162));
#514=CARTESIAN_POINT('',(7.29269831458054,3.39820593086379,8.45797583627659));
#515=CARTESIAN_POINT('',(6.53902943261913,4.68849272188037,8.54749386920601));
#516=CARTESIAN_POINT('',(5.56491386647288,5.81027291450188,8.63510295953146));
#517=CARTESIAN_POINT('',(4.39545307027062,6.73976824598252,8.72452520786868));
#518=CARTESIAN_POINT('',(3.08019717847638,7.43217377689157,8.81228759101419));
#519=CARTESIAN_POINT('',(1.65440904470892,7.8746306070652,8.9014872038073));
#520=CARTESIAN_POINT('',(0.176379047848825,8.04315798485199,8.98952347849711));
#521=CARTESIAN_POINT('',(-1.31129414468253,7.93901255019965,9.07837790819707));
#522=CARTESIAN_POINT('',(-2.75157899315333,7.55994651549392,9.1667978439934));
#523=CARTESIAN_POINT('',(-4.09853223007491,6.92441749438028,9.25521837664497));
#524=CARTESIAN_POINT('',(-5.30525316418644,6.04820060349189,9.34407222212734));
#525=CARTESIAN_POINT('',(-6.32882844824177,4.9686960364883,9.43210903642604));
#526=CARTESIAN_POINT('',(-7.13715494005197,3.71364093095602,9.52130816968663));
#527=CARTESIAN_POINT('',(-7.69895042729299,2.33750243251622,9.60907094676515));
#528=CARTESIAN_POINT('',(-7.99816325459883,0.873940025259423,9.69849290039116));
#529=CARTESIAN_POINT('',(-8.02242736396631,-0.611565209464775,9.78610217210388));
#530=CARTESIAN_POINT('',(-7.77131207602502,-2.08458444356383,9.87562014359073));
#531=CARTESIAN_POINT('',(-7.25505970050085,-3.47755725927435,9.96319853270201));
#532=CARTESIAN_POINT('',(-6.4876394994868,-4.75955110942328,10.0526846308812));
#533=CARTESIAN_POINT('',(-5.50099722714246,-5.87069494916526,10.1403551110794));
#534=CARTESIAN_POINT('',(-4.32191431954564,-6.78726211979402,10.2296817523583));
#535=CARTESIAN_POINT('',(-2.99863038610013,-7.46539862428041,10.3175663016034));
#536=CARTESIAN_POINT('',(-1.56880599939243,-7.89216516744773,10.4066078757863));
#537=CARTESIAN_POINT('',(-0.0882147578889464,-8.04460724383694,10.4948246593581));
#538=CARTESIAN_POINT('',(1.39726811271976,-7.92429128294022,10.5834648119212));
#539=CARTESIAN_POINT('',(2.83431616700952,-7.5293858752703,10.6721043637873));
#540=CARTESIAN_POINT('',(4.17336359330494,-6.87945821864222,10.760321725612));
#541=CARTESIAN_POINT('',(5.37125881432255,-5.98980343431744,10.8493627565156));
#542=CARTESIAN_POINT('',(6.38235775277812,-4.89953511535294,10.9372477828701));
#543=CARTESIAN_POINT('',(7.1774722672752,-3.63539465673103,11.0265740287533));
#544=CARTESIAN_POINT('',(7.72381425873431,-2.25349368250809,11.114244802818));
#545=CARTESIAN_POINT('',(8.00737048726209,-0.786523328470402,11.2037307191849));
#546=CARTESIAN_POINT('',(8.01514967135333,0.699019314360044,11.29130916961));
#547=CARTESIAN_POINT('',(7.74823665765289,2.16926222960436,11.3808272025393));
#548=CARTESIAN_POINT('',(7.21653887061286,3.55655794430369,11.4684362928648));
#549=CARTESIAN_POINT('',(6.43551131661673,4.82997699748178,11.557858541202));
#550=CARTESIAN_POINT('',(5.43639169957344,5.93046937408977,11.6456209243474));
#551=CARTESIAN_POINT('',(4.24791825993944,6.83389105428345,11.7348205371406));
#552=CARTESIAN_POINT('',(2.9166641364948,7.49777101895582,11.8228568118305));
#553=CARTESIAN_POINT('',(1.48308877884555,7.90872052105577,11.9117112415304));
#554=CARTESIAN_POINT('',(1.55153877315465E-05,8.04512139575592,12.0001311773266));
#555=CARTESIAN_POINT('',(-1.48307022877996,7.90860460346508,12.0885517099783));
#556=CARTESIAN_POINT('',(-2.91670081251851,7.49795292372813,12.1774055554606));
#557=CARTESIAN_POINT('',(-4.24775926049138,6.83363381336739,12.2654423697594));
#558=CARTESIAN_POINT('',(-5.43659182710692,5.93073173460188,12.3546415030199));
#559=CARTESIAN_POINT('',(-6.43517398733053,4.82972991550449,12.4424042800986));
#560=CARTESIAN_POINT('',(-7.21690989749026,3.55676793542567,12.5318262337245));
#561=CARTESIAN_POINT('',(-7.74778341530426,2.16914844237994,12.6194355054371));
#562=CARTESIAN_POINT('',(-8.01561448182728,0.699076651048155,12.7089534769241));
#563=CARTESIAN_POINT('',(-8.0069206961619,-0.786458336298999,12.7965318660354));
#564=CARTESIAN_POINT('',(-7.72424931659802,-2.25361166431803,12.8860179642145));
#565=CARTESIAN_POINT('',(-7.17714242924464,-3.63519686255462,12.9736884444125));
#566=CARTESIAN_POINT('',(-6.38265135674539,-4.89975837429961,13.0630150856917));
#567=CARTESIAN_POINT('',(-5.3711075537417,-5.98958800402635,13.1508996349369));
#568=CARTESIAN_POINT('',(-4.17347488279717,-6.87964611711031,13.2399412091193));
#569=CARTESIAN_POINT('',(-2.83431247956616,-7.52928684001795,13.3281579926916));
#570=CARTESIAN_POINT('',(-1.39726470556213,-7.92429188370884,13.4167981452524));
#571=CARTESIAN_POINT('',(0.0881843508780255,-8.04470156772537,13.5054376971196));
#572=CARTESIAN_POINT('',(1.56876568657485,-7.8919505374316,13.5936550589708));
#573=CARTESIAN_POINT('',(2.99869884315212,-7.46565279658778,13.6826960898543));
#574=CARTESIAN_POINT('',(4.32171478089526,-6.78695190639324,13.7705811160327));
#575=CARTESIAN_POINT('',(5.50123952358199,-5.8709936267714,13.859907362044));
#576=CARTESIAN_POINT('',(6.48727103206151,-4.75929144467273,13.9475781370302));
#577=CARTESIAN_POINT('',(7.25546013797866,-3.47777216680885,14.0370640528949));
#578=CARTESIAN_POINT('',(7.77085568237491,-2.08447934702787,14.1246424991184));
#579=CARTESIAN_POINT('',(8.02289218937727,-0.611613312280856,14.2141605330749));
#580=CARTESIAN_POINT('',(7.99774279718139,0.87386959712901,14.3017696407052));
#581=CARTESIAN_POINT('',(7.69935191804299,2.3376192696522,14.3911918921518));
#582=CARTESIAN_POINT('',(7.13687710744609,3.71346282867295,14.4789542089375));
#583=CARTESIAN_POINT('',(6.32906584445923,4.96888330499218,14.5681537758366));
#584=CARTESIAN_POINT('',(5.30515656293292,6.04804226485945,14.6561902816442));
#585=CARTESIAN_POINT('',(4.09858936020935,6.92452030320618,14.7450450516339));
#586=CARTESIAN_POINT('',(2.75160812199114,7.55993577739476,14.833464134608));
#587=CARTESIAN_POINT('',(1.31127164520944,7.9388965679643,14.9218831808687));
#588=CARTESIAN_POINT('',(-0.176351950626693,8.04334143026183,15.0107399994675));
#589=CARTESIAN_POINT('',(-1.65434667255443,7.87433623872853,15.09878125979));
#590=CARTESIAN_POINT('',(-3.08029148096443,7.43249181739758,15.1879721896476));
#591=CARTESIAN_POINT('',(-4.3952240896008,6.73941730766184,15.2757223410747));
#592=CARTESIAN_POINT('',(-5.56520427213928,5.81057493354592,15.3651646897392));
#593=CARTESIAN_POINT('',(-6.53862925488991,4.68823521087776,15.4528068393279));
#594=CARTESIAN_POINT('',(-7.29308504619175,3.39852147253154,15.5422799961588));
#595=CARTESIAN_POINT('',(-7.79310415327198,1.99951045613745,15.6297816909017));
#596=CARTESIAN_POINT('',(-8.02912856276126,0.523737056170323,15.7193533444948));
#597=CARTESIAN_POINT('',(-7.9875816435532,-0.961144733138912,15.8071789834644));
#598=CARTESIAN_POINT('',(-7.67320021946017,-2.42063595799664,15.896358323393));
#599=CARTESIAN_POINT('',(-7.09916992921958,-3.78981306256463,15.9839898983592));
#600=CARTESIAN_POINT('',(-6.2628768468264,-5.04531619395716,16.0733232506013));
#601=CARTESIAN_POINT('',(-5.2755735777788,-6.08351017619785,16.1616872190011));
#602=CARTESIAN_POINT('',(-4.3467865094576,-6.72813755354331,16.2208552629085));
#603=CARTESIAN_POINT('',(-4.00008235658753,-6.92830728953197,16.2502626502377));
#604=CARTESIAN_POINT('',(6.5,0.,-0.75));
#605=CARTESIAN_POINT('',(6.47806642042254,0.400822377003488,-0.720553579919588));
#606=CARTESIAN_POINT('',(6.43410863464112,1.20412327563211,-0.661539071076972));
#607=CARTESIAN_POINT('',(6.09069394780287,2.36877605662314,-0.572976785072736));
#608=CARTESIAN_POINT('',(5.55232236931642,3.4524226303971,-0.48434174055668));
#609=CARTESIAN_POINT('',(4.81961329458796,4.41681333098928,-0.395824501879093));
#610=CARTESIAN_POINT('',(3.92254561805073,5.22903417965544,-0.307292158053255));
#611=CARTESIAN_POINT('',(2.89135289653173,5.86295260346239,-0.218767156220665));
#612=CARTESIAN_POINT('',(1.76076127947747,6.29583499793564,-0.130191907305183));
#613=CARTESIAN_POINT('',(0.569759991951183,6.51209926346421,-0.0416767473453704));
#614=CARTESIAN_POINT('',(-0.640822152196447,6.50601143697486,0.0468853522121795));
#615=CARTESIAN_POINT('',(-1.82913527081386,6.27559908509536,0.135404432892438));
#616=CARTESIAN_POINT('',(-2.95539058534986,5.83162184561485,0.223969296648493));
#617=CARTESIAN_POINT('',(-3.97920794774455,5.18585598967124,0.312491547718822));
#618=CARTESIAN_POINT('',(-4.86812603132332,4.36405036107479,0.401048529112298));
#619=CARTESIAN_POINT('',(-5.58815743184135,3.3910005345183,0.48957837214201));
#620=CARTESIAN_POINT('',(-6.11884513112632,2.30295159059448,0.578127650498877));
#621=CARTESIAN_POINT('',(-6.43728195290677,1.13507202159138,0.66666656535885));
#622=CARTESIAN_POINT('',(-6.53737060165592,-0.071318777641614,0.755206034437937));
#623=CARTESIAN_POINT('',(-6.41112324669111,-1.27526065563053,0.843754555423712));
#624=CARTESIAN_POINT('',(-6.06685082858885,-2.43577504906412,0.932284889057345));
#625=CARTESIAN_POINT('',(-5.51317930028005,-3.51230731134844,1.02084190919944));
#626=CARTESIAN_POINT('',(-4.77136668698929,-4.46884528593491,1.10936482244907));
#627=CARTESIAN_POINT('',(-3.8654674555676,-5.27188287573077,1.19792792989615));
#628=CARTESIAN_POINT('',(-2.82717201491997,-5.89409485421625,1.28644632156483));
#629=CARTESIAN_POINT('',(-1.69197456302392,-6.31466964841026,1.37501226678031));
#630=CARTESIAN_POINT('',(-0.498689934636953,-6.51779048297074,1.46352962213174));
#631=CARTESIAN_POINT('',(0.711767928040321,-6.49878100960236,1.55209477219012));
#632=CARTESIAN_POINT('',(1.89746137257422,-6.25520622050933,1.64061472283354));
#633=CARTESIAN_POINT('',(3.01885265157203,-5.79909384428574,1.7291755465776));
#634=CARTESIAN_POINT('',(4.03551563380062,-5.14210394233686,1.81770138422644));
#635=CARTESIAN_POINT('',(4.91545750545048,-4.31071004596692,1.9062549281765));
#636=CARTESIAN_POINT('',(5.6248268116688,-3.32984204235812,1.99478912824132));
#637=CARTESIAN_POINT('',(6.14355774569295,-2.23606049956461,2.0833334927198));
#638=CARTESIAN_POINT('',(6.44933946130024,-1.06478829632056,2.17187725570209));
#639=CARTESIAN_POINT('',(6.53611110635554,0.142616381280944,2.26041203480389));
#640=CARTESIAN_POINT('',(6.3969231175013,1.3451437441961,2.34896503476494));
#641=CARTESIAN_POINT('',(6.03981359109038,2.50175718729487,2.43749135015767));
#642=CARTESIAN_POINT('',(5.47463416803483,3.57230479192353,2.52605177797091));
#643=CARTESIAN_POINT('',(4.72224883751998,4.52053540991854,2.61457202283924));
#644=CARTESIAN_POINT('',(3.8078016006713,5.31383741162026,2.70313699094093));
#645=CARTESIAN_POINT('',(2.76266330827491,5.92447481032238,2.79165440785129));
#646=CARTESIAN_POINT('',(1.62302118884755,6.33286401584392,2.88022041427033));
#647=CARTESIAN_POINT('',(0.427557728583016,6.522746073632,2.96873862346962));
#648=CARTESIAN_POINT('',(-0.782624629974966,6.49072298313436,3.05730202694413));
#649=CARTESIAN_POINT('',(-1.96556472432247,6.23407625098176,3.14582454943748));
#650=CARTESIAN_POINT('',(-3.08195106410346,5.76586601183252,3.23438204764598));
#651=CARTESIAN_POINT('',(-4.09136020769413,5.09776152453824,3.32291182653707));
#652=CARTESIAN_POINT('',(-4.96217685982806,4.25683442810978,3.41146093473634));
#653=CARTESIAN_POINT('',(-5.66084871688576,3.26829872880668,3.49999985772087));
#654=CARTESIAN_POINT('',(-6.16751162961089,2.16889468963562,3.58853937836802));
#655=CARTESIAN_POINT('',(-6.4606500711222,0.994380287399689,3.67708790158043));
#656=CARTESIAN_POINT('',(-6.53405903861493,-0.21389461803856,3.76561822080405));
#657=CARTESIAN_POINT('',(-6.38197374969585,-1.41487088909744,3.85417523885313));
#658=CARTESIAN_POINT('',(-6.01205317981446,-2.567437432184,3.94269815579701));
#659=CARTESIAN_POINT('',(-5.43544138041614,-3.63188170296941,4.03126126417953));
#660=CARTESIAN_POINT('',(-4.67257184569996,-4.57168765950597,4.11977965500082));
#661=CARTESIAN_POINT('',(-3.74968023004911,-5.35515908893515,4.2083455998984));
#662=CARTESIAN_POINT('',(-2.69783088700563,-5.95415761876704,4.29686295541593));
#663=CARTESIAN_POINT('',(-1.55387094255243,-6.35029552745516,4.38542810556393));
#664=CARTESIAN_POINT('',(-0.356376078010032,-6.52694113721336,4.47394805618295));
#665=CARTESIAN_POINT('',(0.853386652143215,-6.48187410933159,4.56250887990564));
#666=CARTESIAN_POINT('',(2.0334411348,-6.21222476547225,4.65103471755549));
#667=CARTESIAN_POINT('',(3.14466947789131,-5.73192790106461,4.73958826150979));
#668=CARTESIAN_POINT('',(4.14673519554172,-5.05283206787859,4.82812246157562));
#669=CARTESIAN_POINT('',(5.00827814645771,-4.20243005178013,4.91666682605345));
#670=CARTESIAN_POINT('',(5.69621765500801,-3.20637771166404,5.0052105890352));
#671=CARTESIAN_POINT('',(6.19071305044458,-2.10146609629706,5.09374536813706));
#672=CARTESIAN_POINT('',(6.47120770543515,-0.923854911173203,5.18229836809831));
#673=CARTESIAN_POINT('',(6.53121961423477,0.285144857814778,5.27082468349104));
#674=CARTESIAN_POINT('',(6.36627352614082,1.48443328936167,5.35938511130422));
#675=CARTESIAN_POINT('',(5.98357655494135,2.63280954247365,5.44790535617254));
#676=CARTESIAN_POINT('',(5.39560249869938,3.69102895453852,5.53647032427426));
#677=CARTESIAN_POINT('',(4.62234404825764,4.62229876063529,5.62498774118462));
#678=CARTESIAN_POINT('',(3.6911080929,5.39583964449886,5.71355374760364));
#679=CARTESIAN_POINT('',(2.63268338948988,5.98314299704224,5.80207195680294));
#680=CARTESIAN_POINT('',(1.48453141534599,6.36695787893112,5.89063536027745));
#681=CARTESIAN_POINT('',(0.285152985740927,6.53037817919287,5.97915788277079));
#682=CARTESIAN_POINT('',(-0.924044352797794,6.47223108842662,6.06771538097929));
#683=CARTESIAN_POINT('',(-2.10108386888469,6.18965649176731,6.15624515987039));
#684=CARTESIAN_POINT('',(-3.2069978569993,5.69728034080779,6.24479426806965));
#685=CARTESIAN_POINT('',(-4.20163376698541,5.00732048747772,6.33333319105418));
#686=CARTESIAN_POINT('',(-5.05375949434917,4.1475075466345,6.42187271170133));
#687=CARTESIAN_POINT('',(-5.73092710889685,3.1440842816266,6.51042123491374));
#688=CARTESIAN_POINT('',(-6.21316333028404,2.03378461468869,6.59895155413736));
#689=CARTESIAN_POINT('',(-6.48100798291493,0.853219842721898,6.68750857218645));
#690=CARTESIAN_POINT('',(-6.52759732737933,-0.35635871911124,6.77603148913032));
#691=CARTESIAN_POINT('',(-6.34982085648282,-1.55382199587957,6.86459459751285));
#692=CARTESIAN_POINT('',(-5.95439055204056,-2.69786746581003,6.95311298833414));
#693=CARTESIAN_POINT('',(-5.35511912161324,-3.74973730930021,7.04167893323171));
#694=CARTESIAN_POINT('',(-4.57157361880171,-4.67236547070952,7.13019628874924));
#695=CARTESIAN_POINT('',(-3.63209004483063,-5.435870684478,7.21876143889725));
#696=CARTESIAN_POINT('',(-2.56722931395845,-6.01143062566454,7.30728138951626));
#697=CARTESIAN_POINT('',(-1.41501037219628,-6.38284469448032,7.39584221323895));
#698=CARTESIAN_POINT('',(-0.213896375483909,-6.53305959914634,7.48436805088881));
#699=CARTESIAN_POINT('',(0.994587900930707,-6.46179065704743,7.57292159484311));
#700=CARTESIAN_POINT('',(2.16848611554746,-6.1663759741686,7.66145579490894));
#701=CARTESIAN_POINT('',(3.26892628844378,-5.66192451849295,7.75000015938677));
#702=CARTESIAN_POINT('',(4.25604793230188,-4.96123065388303,7.83854392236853));
#703=CARTESIAN_POINT('',(5.09862363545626,-4.09208074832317,7.92707870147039));
#704=CARTESIAN_POINT('',(5.76496913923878,-3.08142302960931,8.01563170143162));
#705=CARTESIAN_POINT('',(6.23486416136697,-1.96586014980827,8.10415801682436));
#706=CARTESIAN_POINT('',(6.49004634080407,-0.782482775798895,8.19271844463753));
#707=CARTESIAN_POINT('',(6.52319663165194,0.427527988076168,8.28123868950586));
#708=CARTESIAN_POINT('',(6.33261410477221,1.62302793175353,8.36980365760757));
#709=CARTESIAN_POINT('',(5.92450187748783,2.76260526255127,8.45832107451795));
#710=CARTESIAN_POINT('',(5.31399288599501,3.80799737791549,8.54688708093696));
#711=CARTESIAN_POINT('',(4.52026857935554,4.72188457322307,8.63540529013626));
#712=CARTESIAN_POINT('',(3.5726310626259,5.47524368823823,8.72396869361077));
#713=CARTESIAN_POINT('',(2.50147703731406,6.03902012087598,8.81249121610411));
#714=CARTESIAN_POINT('',(1.34531574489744,6.39794957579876,8.90104871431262));
#715=CARTESIAN_POINT('',(0.142614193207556,6.53498753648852,8.98957849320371));
#716=CARTESIAN_POINT('',(-1.06500758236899,6.45055016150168,9.07812760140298));
#717=CARTESIAN_POINT('',(-2.23563977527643,6.14238549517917,9.1666665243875));
#718=CARTESIAN_POINT('',(-3.33044937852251,5.62586978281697,9.25520604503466));
#719=CARTESIAN_POINT('',(-4.3099697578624,4.91456530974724,9.34375456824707));
#720=CARTESIAN_POINT('',(-5.14286842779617,4.03615940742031,9.43228488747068));
#721=CARTESIAN_POINT('',(-5.79833700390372,3.01839966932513,9.52084190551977));
#722=CARTESIAN_POINT('',(-6.25581690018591,1.89770211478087,9.60936482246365));
#723=CARTESIAN_POINT('',(-6.49831822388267,0.71165157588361,9.69792793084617));
#724=CARTESIAN_POINT('',(-6.51802188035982,-0.498644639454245,9.78644632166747));
#725=CARTESIAN_POINT('',(-6.31465161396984,-1.69204186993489,9.87501226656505));
#726=CARTESIAN_POINT('',(-5.89391710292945,-2.82701709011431,9.96352962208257));
#727=CARTESIAN_POINT('',(-5.27222548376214,-3.86579961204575,10.0520947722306));
#728=CARTESIAN_POINT('',(-4.46843680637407,-4.77085286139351,10.1406147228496));
#729=CARTESIAN_POINT('',(-3.51273626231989,-5.51395000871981,10.2291755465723));
#730=CARTESIAN_POINT('',(-2.43543482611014,-6.06591102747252,10.3177013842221));
#731=CARTESIAN_POINT('',(-1.27545565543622,-6.41226609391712,10.4062549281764));
#732=CARTESIAN_POINT('',(-0.0713143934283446,-6.53616393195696,10.4947891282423));
#733=CARTESIAN_POINT('',(1.13529367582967,-6.43850732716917,10.5833334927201));
#734=CARTESIAN_POINT('',(2.30253601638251,-6.11768595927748,10.6718772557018));
#735=CARTESIAN_POINT('',(3.39156496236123,-5.58913006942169,10.7604120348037));
#736=CARTESIAN_POINT('',(4.36339021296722,-4.867326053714,10.8489650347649));
#737=CARTESIAN_POINT('',(5.18649207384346,-3.97975341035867,10.9374913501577));
#738=CARTESIAN_POINT('',(5.83102378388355,-2.95501986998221,11.0260517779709));
#739=CARTESIAN_POINT('',(6.27602292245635,-1.82931975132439,11.1145720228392));
#740=CARTESIAN_POINT('',(6.50581899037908,-0.640734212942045,11.2031369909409));
#741=CARTESIAN_POINT('',(6.51207734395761,0.56970079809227,11.2916544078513));
#742=CARTESIAN_POINT('',(6.29593171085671,1.76085442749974,11.3802204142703));
#743=CARTESIAN_POINT('',(5.86264266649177,2.89109718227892,11.4687386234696));
#744=CARTESIAN_POINT('',(5.22981867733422,3.92313430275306,11.5573020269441));
#745=CARTESIAN_POINT('',(4.41608604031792,4.81926710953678,11.6458245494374));
#746=CARTESIAN_POINT('',(3.45241090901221,5.55198092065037,11.7343820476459));
#747=CARTESIAN_POINT('',(2.36911087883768,6.09210263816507,11.822911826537));
#748=CARTESIAN_POINT('',(1.20543832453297,6.42578843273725,11.9114609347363));
#749=CARTESIAN_POINT('',(5.36785981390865E-06,6.53658816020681,11.9999998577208));
#750=CARTESIAN_POINT('',(-1.20543791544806,6.42566909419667,12.088539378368));
#751=CARTESIAN_POINT('',(-2.36916644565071,6.0922772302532,12.1770879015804));
#752=CARTESIAN_POINT('',(-3.4522676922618,5.55171380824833,12.265618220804));
#753=CARTESIAN_POINT('',(-4.41630100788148,4.81951594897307,12.3541752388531));
#754=CARTESIAN_POINT('',(-5.22949262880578,3.92287206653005,12.442698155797));
#755=CARTESIAN_POINT('',(-5.86302250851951,2.89128946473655,12.5312612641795));
#756=CARTESIAN_POINT('',(-6.29548357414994,1.76072208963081,12.6197796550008));
#757=CARTESIAN_POINT('',(-6.51254392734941,0.569738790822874,12.7083455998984));
#758=CARTESIAN_POINT('',(-6.5053671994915,-0.640688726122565,12.7968629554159));
#759=CARTESIAN_POINT('',(-6.27645271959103,-1.82945605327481,12.8854281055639));
#760=CARTESIAN_POINT('',(-5.83068487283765,-2.95483983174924,12.9739480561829));
#761=CARTESIAN_POINT('',(-5.18677431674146,-3.97999157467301,13.0625088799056));
#762=CARTESIAN_POINT('',(-4.36322389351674,-4.86712406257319,13.1510347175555));
#763=CARTESIAN_POINT('',(-3.39166043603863,-5.58932760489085,13.2395882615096));
#764=CARTESIAN_POINT('',(-2.30251333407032,-6.1175940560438,13.3281224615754));
#765=CARTESIAN_POINT('',(-1.1352721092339,-6.43851112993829,13.4166668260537));
#766=CARTESIAN_POINT('',(0.0713042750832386,-6.53625805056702,13.5052105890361));
#767=CARTESIAN_POINT('',(1.27543350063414,-6.41204781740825,13.593745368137));
#768=CARTESIAN_POINT('',(2.43552203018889,-6.06615772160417,13.682298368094));
#769=CARTESIAN_POINT('',(3.51255249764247,-5.51362967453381,13.7708246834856));
#770=CARTESIAN_POINT('',(4.46869370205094,-4.77113795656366,13.8593851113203));
#771=CARTESIAN_POINT('',(5.27186822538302,-3.86552453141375,13.9479053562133));
#772=CARTESIAN_POINT('',(5.89432608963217,-2.82721435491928,14.0364703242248));
#773=CARTESIAN_POINT('',(6.31420017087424,-1.69191798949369,14.1249877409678));
#774=CARTESIAN_POINT('',(6.5184882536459,-0.498673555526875,14.2135537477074));
#775=CARTESIAN_POINT('',(6.49789553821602,0.711600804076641,14.3020719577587));
#776=CARTESIAN_POINT('',(6.25621297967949,1.89783702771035,14.3906353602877));
#777=CARTESIAN_POINT('',(5.79804985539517,3.01823934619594,14.4791578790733));
#778=CARTESIAN_POINT('',(5.14309434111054,4.03636138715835,14.5677153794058));
#779=CARTESIAN_POINT('',(4.30985790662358,4.91442029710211,14.6562451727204));
#780=CARTESIAN_POINT('',(3.33049065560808,5.62598200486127,14.7447942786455));
#781=CARTESIAN_POINT('',(2.23564970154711,6.14238174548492,14.833333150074));
#782=CARTESIAN_POINT('',(1.06496712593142,6.45043706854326,14.9218726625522));
#783=CARTESIAN_POINT('',(-0.142606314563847,6.53517061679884,15.010421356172));
#784=CARTESIAN_POINT('',(-1.34527303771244,6.39765133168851,15.0989517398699));
#785=CARTESIAN_POINT('',(-2.50159515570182,6.03932834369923,15.1875082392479));
#786=CARTESIAN_POINT('',(-3.572413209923,5.47488369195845,15.2760308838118));
#787=CARTESIAN_POINT('',(-4.52055495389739,4.72219059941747,15.3645954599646));
#788=CARTESIAN_POINT('',(-5.31361285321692,3.80771862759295,15.4531147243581));
#789=CARTESIAN_POINT('',(-5.92494426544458,2.76281709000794,15.5416767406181));
#790=CARTESIAN_POINT('',(-6.33221590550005,1.62292384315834,15.6301918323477));
#791=CARTESIAN_POINT('',(-6.52359633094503,0.427491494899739,15.7187673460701));
#792=CARTESIAN_POINT('',(-6.48948916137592,-0.782423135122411,15.807291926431));
#793=CARTESIAN_POINT('',(-6.2353489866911,-1.96579763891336,15.8958250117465));
#794=CARTESIAN_POINT('',(-5.76528165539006,-3.08136271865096,15.9843401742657));
#795=CARTESIAN_POINT('',(-5.09822121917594,-4.09286999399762,16.0729821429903));
#796=CARTESIAN_POINT('',(-4.2549800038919,-4.96108745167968,16.1615201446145));
#797=CARTESIAN_POINT('',(-3.59675975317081,-5.42911492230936,16.2205934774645));
#798=CARTESIAN_POINT('',(-3.25006566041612,-5.6292788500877,16.2500000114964));
#799=CARTESIAN_POINT('',(5.,0.,-0.75));
#800=CARTESIAN_POINT('',(4.98315314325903,0.307851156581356,-0.720581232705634));
#801=CARTESIAN_POINT('',(4.94938982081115,0.924825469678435,-0.661622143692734));
#802=CARTESIAN_POINT('',(4.68415267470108,1.82477902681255,-0.572901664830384));
#803=CARTESIAN_POINT('',(4.27166157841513,2.65459112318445,-0.484953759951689));
#804=CARTESIAN_POINT('',(3.70681881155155,3.39819848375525,-0.395554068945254));
#805=CARTESIAN_POINT('',(3.01869388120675,4.0212438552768,-0.307667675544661));
#806=CARTESIAN_POINT('',(2.22192413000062,4.51094921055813,-0.218443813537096));
#807=CARTESIAN_POINT('',(1.35643091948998,4.84239677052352,-0.130864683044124));
#808=CARTESIAN_POINT('',(0.436206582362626,5.00939971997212,-0.0413361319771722));
#809=CARTESIAN_POINT('',(-0.490799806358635,5.00485716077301,0.046314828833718));
#810=CARTESIAN_POINT('',(-1.40891039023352,4.8267081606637,0.135711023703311));
#811=CARTESIAN_POINT('',(-2.27169468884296,4.48677151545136,0.223398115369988));
#812=CARTESIAN_POINT('',(-3.06205704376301,3.98809624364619,0.312692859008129));
#813=CARTESIAN_POINT('',(-3.74382866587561,3.35802846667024,0.400615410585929));
#814=CARTESIAN_POINT('',(-4.29892649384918,2.6076732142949,0.489634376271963));
#815=CARTESIAN_POINT('',(-4.70665565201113,1.77201054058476,0.577875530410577));
#816=CARTESIAN_POINT('',(-4.95166846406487,0.873108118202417,0.666534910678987));
#817=CARTESIAN_POINT('',(-5.02875387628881,-0.0554133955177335,0.755194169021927));
#818=CARTESIAN_POINT('',(-4.9317245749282,-0.980137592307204,0.843437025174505));
#819=CARTESIAN_POINT('',(-4.66627042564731,-1.8749718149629,0.932460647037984));
#820=CARTESIAN_POINT('',(-4.24167373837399,-2.70047760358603,1.02037559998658));
#821=CARTESIAN_POINT('',(-3.66892165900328,-3.4389551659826,1.10965871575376));
#822=CARTESIAN_POINT('',(-2.97499902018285,-4.05412320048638,1.19736297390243));
#823=CARTESIAN_POINT('',(-2.17276136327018,-4.53478119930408,1.28679046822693));
#824=CARTESIAN_POINT('',(-1.303596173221,-4.85689339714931,1.37440438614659));
#825=CARTESIAN_POINT('',(-0.381502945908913,-5.01373633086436,1.4638607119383));
#826=CARTESIAN_POINT('',(0.545463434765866,-4.99932584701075,1.55150491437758));
#827=CARTESIAN_POINT('',(1.461250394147,-4.81106162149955,1.64087433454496));
#828=CARTESIAN_POINT('',(2.32072104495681,-4.46166903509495,1.72866934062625));
#829=CARTESIAN_POINT('',(3.1051216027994,-3.95461848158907,1.81783646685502));
#830=CARTESIAN_POINT('',(3.78050248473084,-3.31671165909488,1.9059019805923));
#831=CARTESIAN_POINT('',(4.32692676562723,-2.56098424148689,1.99475359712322));
#832=CARTESIAN_POINT('',(4.72584387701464,-1.72004503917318,2.08320217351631));
#833=CARTESIAN_POINT('',(4.96088139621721,-0.819473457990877,2.17165014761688));
#834=CARTESIAN_POINT('',(5.02775483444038,0.110722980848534,2.26050234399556));
#835=CARTESIAN_POINT('',(4.92089489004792,1.033542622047,2.34856731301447));
#836=CARTESIAN_POINT('',(4.64532642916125,1.92599798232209,2.43773491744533));
#837=CARTESIAN_POINT('',(4.21218807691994,2.74643359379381,2.52552952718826));
#838=CARTESIAN_POINT('',(3.63100776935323,3.47879829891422,2.61489924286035));
#839=CARTESIAN_POINT('',(2.93076877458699,4.08635022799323,2.702543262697));
#840=CARTESIAN_POINT('',(2.12312026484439,4.55811673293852,2.79199964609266));
#841=CARTESIAN_POINT('',(1.25056024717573,4.87092713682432,2.87961362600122));
#842=CARTESIAN_POINT('',(0.326915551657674,5.01750718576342,2.96904095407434));
#843=CARTESIAN_POINT('',(-0.600122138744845,4.99314118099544,3.05674551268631));
#844=CARTESIAN_POINT('',(-1.51338816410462,4.79486449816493,3.14602817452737));
#845=CARTESIAN_POINT('',(-2.36953799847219,4.4359813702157,3.23394355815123));
#846=CARTESIAN_POINT('',(-3.14779230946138,3.92073230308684,3.32296684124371));
#847=CARTESIAN_POINT('',(-3.81674522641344,3.2749160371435,3.41121062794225));
#848=CARTESIAN_POINT('',(-4.35442568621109,2.5140233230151,3.49986853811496));
#849=CARTESIAN_POINT('',(-4.7444356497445,1.66786357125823,3.58852704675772));
#850=CARTESIAN_POINT('',(-4.96953202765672,0.765721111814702,3.67677024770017));
#851=CARTESIAN_POINT('',(-5.02613796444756,-0.165938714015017,3.76579407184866));
#852=CARTESIAN_POINT('',(-4.90948724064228,-1.08688101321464,3.85370897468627));
#853=CARTESIAN_POINT('',(-4.62385056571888,-1.97671567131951,3.94299203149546));
#854=CARTESIAN_POINT('',(-4.18217642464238,-2.7921200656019,4.03069629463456));
#855=CARTESIAN_POINT('',(-3.59271432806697,-3.51817227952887,4.12012380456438));
#856=CARTESIAN_POINT('',(-2.88613508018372,-4.11813073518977,4.20773772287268));
#857=CARTESIAN_POINT('',(-2.07329432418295,-4.58088934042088,4.29719404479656));
#858=CARTESIAN_POINT('',(-1.19730217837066,-4.88438908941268,4.38483824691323));
#859=CARTESIAN_POINT('',(-0.27235377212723,-5.0206961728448,4.4742076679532));
#860=CARTESIAN_POINT('',(0.654783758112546,-4.98633081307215,4.56200267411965));
#861=CARTESIAN_POINT('',(1.56530067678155,-4.77813994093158,4.65116980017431));
#862=CARTESIAN_POINT('',(2.41812809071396,-4.40969747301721,4.73923531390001));
#863=CARTESIAN_POINT('',(3.19007295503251,-3.88643410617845,4.82808693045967));
#864=CARTESIAN_POINT('',(3.85255056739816,-3.23264743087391,4.91653550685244));
#865=CARTESIAN_POINT('',(4.38142721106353,-2.46677452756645,5.00498348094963));
#866=CARTESIAN_POINT('',(4.76241360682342,-1.61554786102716,5.0938356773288));
#867=CARTESIAN_POINT('',(4.97762101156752,-0.711832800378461,5.18190064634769));
#868=CARTESIAN_POINT('',(5.02390907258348,0.221050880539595,5.27106825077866));
#869=CARTESIAN_POINT('',(4.89749766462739,1.14015021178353,5.35886286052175));
#870=CARTESIAN_POINT('',(4.60185029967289,2.02712329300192,5.44823257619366));
#871=CARTESIAN_POINT('',(4.15163588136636,2.8375311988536,5.53587659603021));
#872=CARTESIAN_POINT('',(3.55404818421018,3.55707876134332,5.62533297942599));
#873=CARTESIAN_POINT('',(2.8410974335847,4.14945749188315,5.71294695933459));
#874=CARTESIAN_POINT('',(2.02328865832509,4.60310277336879,5.80237428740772));
#875=CARTESIAN_POINT('',(1.14382451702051,4.89727178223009,5.89007884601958));
#876=CARTESIAN_POINT('',(0.217820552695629,5.02330802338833,5.97936150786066));
#877=CARTESIAN_POINT('',(-0.709442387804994,4.97888868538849,6.06727689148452));
#878=CARTESIAN_POINT('',(-1.6169877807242,4.760891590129,6.15630017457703));
#879=CARTESIAN_POINT('',(-2.46648007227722,4.38281818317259,6.24454396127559));
#880=CARTESIAN_POINT('',(-3.23197506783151,3.85171046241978,6.33320187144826));
#881=CARTESIAN_POINT('',(-3.88786823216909,3.18997165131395,6.42186038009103));
#882=CARTESIAN_POINT('',(-4.40794053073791,2.41922253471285,6.51010358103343));
#883=CARTESIAN_POINT('',(-4.77977913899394,1.56310904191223,6.59912740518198));
#884=CARTESIAN_POINT('',(-4.98514413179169,0.657809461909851,6.68704230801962));
#885=CARTESIAN_POINT('',(-5.02107483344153,-0.276055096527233,6.77632536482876));
#886=CARTESIAN_POINT('',(-4.88492163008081,-1.193346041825,6.86402962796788));
#887=CARTESIAN_POINT('',(-4.5793329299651,-2.0772198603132,6.95345713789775));
#888=CARTESIAN_POINT('',(-4.12056350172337,-2.88266072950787,7.04107105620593));
#889=CARTESIAN_POINT('',(-3.51501580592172,-3.59551948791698,7.13052737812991));
#890=CARTESIAN_POINT('',(-2.79565547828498,-4.18032292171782,7.21817158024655));
#891=CARTESIAN_POINT('',(-1.97310805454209,-4.62476066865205,7.30754100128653));
#892=CARTESIAN_POINT('',(-1.09013011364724,-4.90956750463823,7.395336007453));
#893=CARTESIAN_POINT('',(-0.163318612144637,-5.0253472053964,7.48450313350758));
#894=CARTESIAN_POINT('',(0.764091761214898,-4.97080869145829,7.57256864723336));
#895=CARTESIAN_POINT('',(1.66844926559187,-4.74312266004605,7.66142026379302));
#896=CARTESIAN_POINT('',(2.51458280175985,-4.35534483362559,7.74986884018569));
#897=CARTESIAN_POINT('',(3.27350824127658,-3.81654618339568,7.83831681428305));
#898=CARTESIAN_POINT('',(3.92265501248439,-3.14695978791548,7.92716901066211));
#899=CARTESIAN_POINT('',(4.43397257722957,-2.37135068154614,8.01523397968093));
#900=CARTESIAN_POINT('',(4.79653413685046,-1.51055821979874,8.10440158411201));
#901=CARTESIAN_POINT('',(4.99209675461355,-0.60365211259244,8.19219619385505));
#902=CARTESIAN_POINT('',(5.01764176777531,0.330947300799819,8.28156590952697));
#903=CARTESIAN_POINT('',(4.87175442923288,1.24646402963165,8.36920992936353));
#904=CARTESIAN_POINT('',(4.55630544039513,2.12700459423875,8.4586663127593));
#905=CARTESIAN_POINT('',(4.08895633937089,2.9275020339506,8.54628029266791));
#906=CARTESIAN_POINT('',(3.47562329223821,3.63349623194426,8.63570762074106));
#907=CARTESIAN_POINT('',(2.74980905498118,4.21071913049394,8.72341217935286));
#908=CARTESIAN_POINT('',(1.92275689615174,4.64586646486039,8.81269484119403));
#909=CARTESIAN_POINT('',(1.03622244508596,4.92126854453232,8.90061022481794));
#910=CARTESIAN_POINT('',(0.108849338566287,5.02681708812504,8.98963350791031));
#911=CARTESIAN_POINT('',(-0.818721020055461,4.9620877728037,9.07787729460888));
#912=CARTESIAN_POINT('',(-1.71970055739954,4.72482447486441,9.16653520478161));
#913=CARTESIAN_POINT('',(-2.5623665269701,4.32732207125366,9.25519371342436));
#914=CARTESIAN_POINT('',(-3.31468635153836,3.78093001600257,9.34343691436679));
#915=CARTESIAN_POINT('',(-3.95690840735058,3.10362277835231,9.43246073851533));
#916=CARTESIAN_POINT('',(-4.45951906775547,2.32315840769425,9.52037564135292));
#917=CARTESIAN_POINT('',(-4.81268337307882,1.45790179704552,9.60965869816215));
#918=CARTESIAN_POINT('',(-4.99847319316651,0.549363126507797,9.69736296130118));
#919=CARTESIAN_POINT('',(-5.01361639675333,-0.385724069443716,9.78679047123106));
#920=CARTESIAN_POINT('',(-4.85799115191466,-1.29949929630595,9.87440438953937));
#921=CARTESIAN_POINT('',(-4.53277450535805,-2.17647692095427,9.96386071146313));
#922=CARTESIAN_POINT('',(-4.05681146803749,-2.97204811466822,10.05150491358));
#923=CARTESIAN_POINT('',(-3.43587638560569,-3.67101077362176,10.1408743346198));
#924=CARTESIAN_POINT('',(-2.70355820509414,-4.2406378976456,10.2286693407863));
#925=CARTESIAN_POINT('',(-1.87223926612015,-4.66642343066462,10.3178364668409));
#926=CARTESIAN_POINT('',(-0.982105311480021,-4.93236702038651,10.4059019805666));
#927=CARTESIAN_POINT('',(-0.0544140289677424,-5.02772062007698,10.4947535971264));
#928=CARTESIAN_POINT('',(0.873319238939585,-4.95272337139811,10.583202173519));
#929=CARTESIAN_POINT('',(1.77075586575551,-4.70598604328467,10.6716501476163));
#930=CARTESIAN_POINT('',(2.60976633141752,-4.29880192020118,10.7605023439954));
#931=CARTESIAN_POINT('',(3.35552161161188,-3.74484867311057,10.8485673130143));
#932=CARTESIAN_POINT('',(3.9906263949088,-3.05997170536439,10.9377349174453));
#933=CARTESIAN_POINT('',(4.4845753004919,-2.27464508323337,11.0255295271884));
#934=CARTESIAN_POINT('',(4.82823158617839,-1.40514582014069,11.1148992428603));
#935=CARTESIAN_POINT('',(5.00426749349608,-0.494945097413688,11.2025432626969));
#936=CARTESIAN_POINT('',(5.00900501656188,0.440382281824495,11.2919996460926));
#937=CARTESIAN_POINT('',(4.84362676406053,1.35244662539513,11.3796136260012));
#938=CARTESIAN_POINT('',(4.50874646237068,2.22563642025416,11.4690409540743));
#939=CARTESIAN_POINT('',(4.0241260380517,3.01629160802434,11.5567455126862));
#940=CARTESIAN_POINT('',(3.39578038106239,3.70806484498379,11.6460281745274));
#941=CARTESIAN_POINT('',(2.65690355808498,4.27007078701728,11.7339435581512));
#942=CARTESIAN_POINT('',(1.82155762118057,4.68643425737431,11.8229668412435));
#943=CARTESIAN_POINT('',(0.92778787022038,4.94285634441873,11.9112106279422));
#944=CARTESIAN_POINT('',(-4.77966810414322E-06,5.0280549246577,11.999868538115));
#945=CARTESIAN_POINT('',(-0.927805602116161,4.94273358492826,12.0885270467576));
#946=CARTESIAN_POINT('',(-1.82163207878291,4.68660153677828,12.1767702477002));
#947=CARTESIAN_POINT('',(-2.65677612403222,4.26979380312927,12.2657940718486));
#948=CARTESIAN_POINT('',(-3.39601018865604,3.70830016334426,12.3537089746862));
#949=CARTESIAN_POINT('',(-4.02381127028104,3.0160142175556,12.4429920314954));
#950=CARTESIAN_POINT('',(-4.50913511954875,2.22581099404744,12.5306962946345));
#951=CARTESIAN_POINT('',(-4.84318373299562,1.35229573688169,12.6201238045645));
#952=CARTESIAN_POINT('',(-5.00947337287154,0.440400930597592,12.7077377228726));
#953=CARTESIAN_POINT('',(-5.00381370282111,-0.494919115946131,12.7971940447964));
#954=CARTESIAN_POINT('',(-4.82865612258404,-1.40530044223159,12.8848382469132));
#955=CARTESIAN_POINT('',(-4.48422731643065,-2.27448280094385,12.9742076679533));
#956=CARTESIAN_POINT('',(-3.99089727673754,-3.0602247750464,13.0620026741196));
#957=CARTESIAN_POINT('',(-3.35534023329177,-3.74466012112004,13.1511698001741));
#958=CARTESIAN_POINT('',(-2.60984598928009,-4.29900909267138,13.2392353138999));
#959=CARTESIAN_POINT('',(-1.77071418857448,-4.70590127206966,13.3280869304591));
#960=CARTESIAN_POINT('',(-0.873279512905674,-4.95273037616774,13.4165355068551));
#961=CARTESIAN_POINT('',(0.0544241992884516,-5.02781453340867,13.5049834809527));
#962=CARTESIAN_POINT('',(0.982101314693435,-4.93214509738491,13.5938356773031));
#963=CARTESIAN_POINT('',(1.87234521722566,-4.66666264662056,13.6819006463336));
#964=CARTESIAN_POINT('',(2.70339021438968,-4.24030744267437,13.7710682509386));
#965=CARTESIAN_POINT('',(3.43614788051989,-3.67128228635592,13.8588628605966));
#966=CARTESIAN_POINT('',(4.05646541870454,-2.97175761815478,13.9482325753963));
#967=CARTESIAN_POINT('',(4.53319204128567,-2.17665654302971,14.0358765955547));
#968=CARTESIAN_POINT('',(4.85754465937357,-1.29935663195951,14.1253329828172));
#969=CARTESIAN_POINT('',(5.01408431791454,-0.385733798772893,14.2129469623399));
#970=CARTESIAN_POINT('',(4.99804827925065,0.549332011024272,14.3023742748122));
#971=CARTESIAN_POINT('',(4.81307404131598,1.45805478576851,14.3900788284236));
#972=CARTESIAN_POINT('',(4.45922260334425,2.32301586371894,14.4793615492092));
#973=CARTESIAN_POINT('',(3.95712283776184,3.10383946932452,14.5672769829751));
#974=CARTESIAN_POINT('',(3.31455925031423,3.78079832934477,14.6563000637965));
#975=CARTESIAN_POINT('',(2.56239195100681,4.32744370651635,14.7445435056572));
#976=CARTESIAN_POINT('',(1.71969128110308,4.72482771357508,14.8332021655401));
#977=CARTESIAN_POINT('',(0.818662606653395,4.9619775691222,14.9218621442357));
#978=CARTESIAN_POINT('',(-0.108860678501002,5.02699980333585,15.0101027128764));
#979=CARTESIAN_POINT('',(-1.03619940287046,4.9209664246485,15.0991222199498));
#980=CARTESIAN_POINT('',(-1.92289883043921,4.64616487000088,15.1870442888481));
#981=CARTESIAN_POINT('',(-2.74960233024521,4.21035007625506,15.2763394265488));
#982=CARTESIAN_POINT('',(-3.47590563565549,3.63380626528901,15.36402623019));
#983=CARTESIAN_POINT('',(-4.08859645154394,2.92720204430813,15.4534226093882));
#984=CARTESIAN_POINT('',(-4.55680348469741,2.12711270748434,15.5410734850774));
#985=CARTESIAN_POINT('',(-4.87132765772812,1.24633723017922,15.6306019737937));
#986=CARTESIAN_POINT('',(-5.01806409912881,0.331245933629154,15.7181813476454));
#987=CARTESIAN_POINT('',(-4.99139667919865,-0.603701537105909,15.8074048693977));
#988=CARTESIAN_POINT('',(-4.79749775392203,-1.51095931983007,15.8952917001));
#989=CARTESIAN_POINT('',(-4.43139338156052,-2.37291237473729,15.9846904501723));
#990=CARTESIAN_POINT('',(-3.93356559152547,-3.14042379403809,16.0726410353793));
#991=CARTESIAN_POINT('',(-3.234386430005,-3.83866472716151,16.161353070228));
#992=CARTESIAN_POINT('',(-2.84673299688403,-4.13009229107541,16.2203316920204));
#993=CARTESIAN_POINT('',(-2.50004896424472,-4.33025041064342,16.2497373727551));
#994=CARTESIAN_POINT('',(5.,0.,0.75));
#995=CARTESIAN_POINT('',(4.98312552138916,0.307848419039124,0.779418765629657));
#996=CARTESIAN_POINT('',(4.94930684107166,0.924817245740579,0.838377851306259));
#997=CARTESIAN_POINT('',(4.68422956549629,1.82477659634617,0.927098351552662));
#998=CARTESIAN_POINT('',(4.27114213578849,2.65427788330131,1.01504616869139));
#999=CARTESIAN_POINT('',(3.70701548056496,3.39837370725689,1.10444595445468));
#1000=CARTESIAN_POINT('',(3.01846617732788,4.02095250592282,1.19233230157));
#1001=CARTESIAN_POINT('',(2.22207643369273,4.51122539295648,1.28155620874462));
#1002=CARTESIAN_POINT('',(1.35625385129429,4.84175574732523,1.36913524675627));
#1003=CARTESIAN_POINT('',(0.43623651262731,5.00972982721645,1.45866389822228));
#1004=CARTESIAN_POINT('',(-0.490739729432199,5.00429713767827,1.54631477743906));
#1005=CARTESIAN_POINT('',(-1.40899644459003,4.82699350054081,1.63571105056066));
#1006=CARTESIAN_POINT('',(-2.27142788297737,4.4862733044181,1.7233980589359));
#1007=CARTESIAN_POINT('',(-3.06218071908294,3.98824637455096,1.81269288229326));
#1008=CARTESIAN_POINT('',(-3.74349851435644,3.35775372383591,1.90061537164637));
#1009=CARTESIAN_POINT('',(-4.29897492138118,2.60769329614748,1.98963438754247));
#1010=CARTESIAN_POINT('',(-4.70641424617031,1.77193857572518,2.07787551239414));
#1011=CARTESIAN_POINT('',(-4.95153925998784,0.8730784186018,2.16653490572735));
#1012=CARTESIAN_POINT('',(-5.02873983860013,-0.055395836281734,2.25519417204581));
#1013=CARTESIAN_POINT('',(-4.93141426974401,-0.980083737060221,2.34343700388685));
#1014=CARTESIAN_POINT('',(-4.66643443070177,-1.87502053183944,2.43246066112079));
#1015=CARTESIAN_POINT('',(-4.24128150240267,-2.70023550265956,2.52037556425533));
#1016=CARTESIAN_POINT('',(-3.66913857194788,-3.43914226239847,2.6096587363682));
#1017=CARTESIAN_POINT('',(-2.97466701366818,-4.05367486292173,2.6973629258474));
#1018=CARTESIAN_POINT('',(-2.1729116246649,-4.53508094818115,2.78679049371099));
#1019=CARTESIAN_POINT('',(-1.30344379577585,-4.85631274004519,2.87440432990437));
#1020=CARTESIAN_POINT('',(-0.381527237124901,-5.01405752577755,2.9638607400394));
#1021=CARTESIAN_POINT('',(0.545390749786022,-4.9987473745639,3.05150485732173));
#1022=CARTESIAN_POINT('',(1.46132845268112,-4.81130098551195,3.14087436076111));
#1023=CARTESIAN_POINT('',(2.32047690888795,-4.46123123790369,3.22866929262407));
#1024=CARTESIAN_POINT('',(3.10520756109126,-3.95471553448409,3.31783648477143));
#1025=CARTESIAN_POINT('',(3.78022767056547,-3.31649340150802,3.40590195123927));
#1026=CARTESIAN_POINT('',(4.326897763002,-2.56095855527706,3.49475360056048));
#1027=CARTESIAN_POINT('',(4.72571370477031,-1.72001650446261,3.5832021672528));
#1028=CARTESIAN_POINT('',(4.96065950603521,-0.819429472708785,3.67165013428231));
#1029=CARTESIAN_POINT('',(5.02784154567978,0.11070794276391,3.76050235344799));
#1030=CARTESIAN_POINT('',(4.92050821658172,1.03346896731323,3.84856728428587));
#1031=CARTESIAN_POINT('',(4.6455506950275,1.92607561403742,3.937734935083));
#1032=CARTESIAN_POINT('',(4.21175337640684,2.74615579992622,4.02552948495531));
#1033=CARTESIAN_POINT('',(3.63124421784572,3.47901231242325,4.11489926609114));
#1034=CARTESIAN_POINT('',(2.93042736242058,4.08587363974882,4.20254320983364));
#1035=CARTESIAN_POINT('',(2.12326479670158,4.55842024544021,4.29199967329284));
#1036=CARTESIAN_POINT('',(1.25041746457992,4.87034495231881,4.37961356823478));
#1037=CARTESIAN_POINT('',(0.326931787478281,5.01780049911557,4.46904098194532));
#1038=CARTESIAN_POINT('',(-0.60004428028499,4.99259623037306,4.55674545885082));
#1039=CARTESIAN_POINT('',(-1.51345382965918,4.7950500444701,4.64602819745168));
#1040=CARTESIAN_POINT('',(-2.36931890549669,4.43560569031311,4.73394351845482));
#1041=CARTESIAN_POINT('',(-3.14783025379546,3.92076703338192,4.82296685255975));
#1042=CARTESIAN_POINT('',(-3.81654445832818,3.27476692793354,4.91121061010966));
#1043=CARTESIAN_POINT('',(-4.35431474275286,2.51395134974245,4.9998685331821));
#1044=CARTESIAN_POINT('',(-4.74441599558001,1.66787516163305,5.08852704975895));
#1045=CARTESIAN_POINT('',(-4.96922189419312,0.765665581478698,5.17677022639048));
#1046=CARTESIAN_POINT('',(-5.02630883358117,-0.165928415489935,5.26579408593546));
#1047=CARTESIAN_POINT('',(-4.90903589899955,-1.0867876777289,5.3537089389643));
#1048=CARTESIAN_POINT('',(-4.62411837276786,-1.97681728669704,5.44299205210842));
#1049=CARTESIAN_POINT('',(-4.18171108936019,-2.79181231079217,5.53069624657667));
#1050=CARTESIAN_POINT('',(-3.59295804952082,-3.51840256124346,5.62012383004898));
#1051=CARTESIAN_POINT('',(-2.88579329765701,-4.1176372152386,5.70773766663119));
#1052=CARTESIAN_POINT('',(-2.07342700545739,-4.58118285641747,5.79719407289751));
#1053=CARTESIAN_POINT('',(-1.19717263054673,-4.88382064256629,5.88483818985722));
#1054=CARTESIAN_POINT('',(-0.272362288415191,-5.02094779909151,5.97420769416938));
#1055=CARTESIAN_POINT('',(0.654704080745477,-4.98583591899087,6.06200262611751));
#1056=CARTESIAN_POINT('',(1.56534825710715,-4.77826054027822,6.15116981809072));
#1057=CARTESIAN_POINT('',(2.41794449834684,-4.40939838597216,6.23923528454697));
#1058=CARTESIAN_POINT('',(3.19005448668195,-3.88640004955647,6.32808693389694));
#1059=CARTESIAN_POINT('',(3.8524380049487,-3.23257609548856,6.41653550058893));
#1060=CARTESIAN_POINT('',(4.38123374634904,-2.46665730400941,6.50498346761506));
#1061=CARTESIAN_POINT('',(4.76248994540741,-1.61559164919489,6.59383568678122));
#1062=CARTESIAN_POINT('',(4.97723246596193,-0.711769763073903,6.68190061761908));
#1063=CARTESIAN_POINT('',(5.02414636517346,0.221047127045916,6.77106826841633));
#1064=CARTESIAN_POINT('',(4.89699416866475,1.1400378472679,6.85886281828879));
#1065=CARTESIAN_POINT('',(4.60214568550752,2.0272435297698,6.94823259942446));
#1066=CARTESIAN_POINT('',(4.15115205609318,2.8372001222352,7.03587654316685));
#1067=CARTESIAN_POINT('',(3.55428780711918,3.55731453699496,7.12533300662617));
#1068=CARTESIAN_POINT('',(2.84076414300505,4.14895925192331,7.21294690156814));
#1069=CARTESIAN_POINT('',(2.02340423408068,4.60337284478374,7.3023743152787));
#1070=CARTESIAN_POINT('',(1.14371129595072,4.89673306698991,7.39007879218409));
#1071=CARTESIAN_POINT('',(0.217822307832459,5.02350483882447,7.47936153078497));
#1072=CARTESIAN_POINT('',(-0.709364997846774,4.97846072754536,7.56727685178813));
#1073=CARTESIAN_POINT('',(-1.61701155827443,4.76093720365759,7.65630018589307));
#1074=CARTESIAN_POINT('',(-2.46634241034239,4.38260939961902,7.744543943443));
#1075=CARTESIAN_POINT('',(-3.23189543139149,3.85160488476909,7.83320186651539));
#1076=CARTESIAN_POINT('',(-3.88784579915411,3.18997582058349,7.92186038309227));
#1077=CARTESIAN_POINT('',(-4.40766809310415,2.41906428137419,8.01010355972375));
#1078=CARTESIAN_POINT('',(-4.77993618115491,1.56317716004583,8.09912741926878));
#1079=CARTESIAN_POINT('',(-4.98468808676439,0.657742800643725,8.18704227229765));
#1080=CARTESIAN_POINT('',(-5.02136124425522,-0.276058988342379,8.27632538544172));
#1081=CARTESIAN_POINT('',(-4.88437909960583,-1.19321600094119,8.36402957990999));
#1082=CARTESIAN_POINT('',(-4.57964071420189,-2.07735289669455,8.45345716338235));
#1083=CARTESIAN_POINT('',(-4.12007353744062,-2.88231386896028,8.54107099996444));
#1084=CARTESIAN_POINT('',(-3.51524087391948,-3.59574992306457,8.63052740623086));
#1085=CARTESIAN_POINT('',(-2.79533932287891,-4.17983306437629,8.71817152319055));
#1086=CARTESIAN_POINT('',(-1.97320211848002,-4.62499420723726,8.8075410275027));
#1087=CARTESIAN_POINT('',(-1.09003572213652,-4.90907520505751,8.89533595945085));
#1088=CARTESIAN_POINT('',(-0.163315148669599,-5.02547680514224,8.98450315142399));
#1089=CARTESIAN_POINT('',(0.764021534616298,-4.97046484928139,9.07256861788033));
#1090=CARTESIAN_POINT('',(1.66844355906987,-4.74308434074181,9.16142026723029));
#1091=CARTESIAN_POINT('',(2.51450142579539,-4.35523930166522,9.24986883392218));
#1092=CARTESIAN_POINT('',(3.27336653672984,-3.81636986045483,9.33831680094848));
#1093=CARTESIAN_POINT('',(3.92271177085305,-3.147027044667,9.42716902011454));
#1094=CARTESIAN_POINT('',(4.43362902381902,-2.37115855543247,9.51523395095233));
#1095=CARTESIAN_POINT('',(4.79675583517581,-1.5106429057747,9.60440160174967));
#1096=CARTESIAN_POINT('',(4.9915851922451,-0.603585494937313,9.69219615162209));
#1097=CARTESIAN_POINT('',(5.01796046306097,0.330959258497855,9.78156593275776));
#1098=CARTESIAN_POINT('',(4.87118654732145,1.2463183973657,9.86920987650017));
#1099=CARTESIAN_POINT('',(4.55661125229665,2.12714419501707,9.95866633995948));
#1100=CARTESIAN_POINT('',(4.08847274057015,2.92714783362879,10.0462802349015));
#1101=CARTESIAN_POINT('',(3.47582426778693,3.6337104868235,10.135707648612));
#1102=CARTESIAN_POINT('',(2.74951841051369,4.21025162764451,10.2234121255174));
#1103=CARTESIAN_POINT('',(1.92282586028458,4.64605081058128,10.3126948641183));
#1104=CARTESIAN_POINT('',(1.03614879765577,4.9208399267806,10.4006101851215));
#1105=CARTESIAN_POINT('',(0.108842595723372,5.02686808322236,10.4896335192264));
#1106=CARTESIAN_POINT('',(-0.81866306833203,4.96184449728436,10.5778772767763));
#1107=CARTESIAN_POINT('',(-1.71966183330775,4.72469802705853,10.6665351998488));
#1108=CARTESIAN_POINT('',(-2.56234402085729,4.32731831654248,10.7551937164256));
#1109=CARTESIAN_POINT('',(-3.31448446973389,3.78068812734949,10.8434368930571));
#1110=CARTESIAN_POINT('',(-3.95703268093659,3.10374050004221,10.9324607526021));
#1111=CARTESIAN_POINT('',(-4.45911332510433,2.32293979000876,11.0203756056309));
#1112=CARTESIAN_POINT('',(-4.81295384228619,1.45799609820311,11.1096587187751));
#1113=CARTESIAN_POINT('',(-4.99791890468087,0.54929976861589,11.1973629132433));
#1114=CARTESIAN_POINT('',(-5.01395112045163,-0.38574381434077,11.2867904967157));
#1115=CARTESIAN_POINT('',(-4.85741210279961,-1.2993409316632,11.3744043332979));
#1116=CARTESIAN_POINT('',(-4.53306481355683,-2.17661648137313,11.4638607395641));
#1117=CARTESIAN_POINT('',(-4.05634683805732,-2.9716959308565,11.551504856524));
#1118=CARTESIAN_POINT('',(-3.43604465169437,-3.67119805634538,11.640874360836));
#1119=CARTESIAN_POINT('',(-2.70330112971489,-4.24020757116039,11.7286692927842));
#1120=CARTESIAN_POINT('',(-1.87228033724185,-4.66654639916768,11.8178364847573));
#1121=CARTESIAN_POINT('',(-0.982053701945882,-4.93201989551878,11.9059019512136));
#1122=CARTESIAN_POINT('',(-0.054406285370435,-5.02768265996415,11.9947536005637));
#1123=CARTESIAN_POINT('',(0.873278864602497,-4.95259637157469,12.0832021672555));
#1124=CARTESIAN_POINT('',(1.77068301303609,-4.70577188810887,12.1716501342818));
#1125=CARTESIAN_POINT('',(2.6097966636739,-4.29888453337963,12.2605023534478));
#1126=CARTESIAN_POINT('',(3.35526448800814,-3.74455063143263,12.3485672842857));
#1127=CARTESIAN_POINT('',(3.99080575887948,-3.06012710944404,12.4377349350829));
#1128=CARTESIAN_POINT('',(4.48411737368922,-2.27440751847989,12.5255294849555));
#1129=CARTESIAN_POINT('',(4.82853515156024,-1.40524358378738,12.6148992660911));
#1130=CARTESIAN_POINT('',(5.00368404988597,-0.494887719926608,12.7025432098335));
#1131=CARTESIAN_POINT('',(5.00934013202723,0.440408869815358,12.7919996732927));
#1132=CARTESIAN_POINT('',(4.84305118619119,1.35227918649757,12.8796135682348));
#1133=CARTESIAN_POINT('',(4.50900859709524,2.22576901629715,12.9690409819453));
#1134=CARTESIAN_POINT('',(4.02369302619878,3.01595170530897,13.0567454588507));
#1135=CARTESIAN_POINT('',(3.39590823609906,3.70821448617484,13.1460281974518));
#1136=CARTESIAN_POINT('',(2.65668775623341,4.26969320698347,13.2339435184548));
#1137=CARTESIAN_POINT('',(1.82156872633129,4.68648448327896,13.3229668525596));
#1138=CARTESIAN_POINT('',(0.927759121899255,4.9426079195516,13.4112106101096));
#1139=CARTESIAN_POINT('',(-1.16386214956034E-05,5.02792285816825,13.4998685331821));
#1140=CARTESIAN_POINT('',(-0.927785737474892,4.94272235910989,13.5885270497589));
#1141=CARTESIAN_POINT('',(-1.82152510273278,4.68630518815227,13.6767702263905));
#1142=CARTESIAN_POINT('',(-2.6568526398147,4.26994692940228,13.7657940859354));
#1143=CARTESIAN_POINT('',(-3.39570368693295,3.70795595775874,13.8537089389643));
#1144=CARTESIAN_POINT('',(-4.02403317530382,3.01619533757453,13.9429920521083));
#1145=CARTESIAN_POINT('',(-4.50863592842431,2.22556187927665,14.0306962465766));
#1146=CARTESIAN_POINT('',(-4.84350502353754,1.35239166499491,14.1201238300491));
#1147=CARTESIAN_POINT('',(-5.00887508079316,0.440351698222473,14.2077376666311));
#1148=CARTESIAN_POINT('',(-5.00413423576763,-0.494950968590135,14.2971940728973));
#1149=CARTESIAN_POINT('',(-4.82809905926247,-1.40512841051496,14.3848381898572));
#1150=CARTESIAN_POINT('',(-4.48444948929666,-2.27460123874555,14.4742076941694));
#1151=CARTESIAN_POINT('',(-3.99050852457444,-3.0599083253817,14.5620026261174));
#1152=CARTESIAN_POINT('',(-3.35542088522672,-3.7447616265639,14.6511698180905));
#1153=CARTESIAN_POINT('',(-2.60967876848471,-4.29870055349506,14.7392352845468));
#1154=CARTESIAN_POINT('',(-1.77069392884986,-4.70586824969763,14.8280869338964));
#1155=CARTESIAN_POINT('',(-0.87327401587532,-4.95259722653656,14.9165355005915));
#1156=CARTESIAN_POINT('',(0.0544289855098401,-5.02758837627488,15.0049834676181));
#1157=CARTESIAN_POINT('',(0.982101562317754,-4.93223310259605,15.0938356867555));
#1158=CARTESIAN_POINT('',(1.87220553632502,-4.6662946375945,15.181900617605));
#1159=CARTESIAN_POINT('',(2.70350561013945,-4.24051482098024,15.2710682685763));
#1160=CARTESIAN_POINT('',(3.43579882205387,-3.67090242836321,15.3588628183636));
#1161=CARTESIAN_POINT('',(4.0567172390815,-2.97195331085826,15.4482325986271));
#1162=CARTESIAN_POINT('',(4.53266340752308,-2.17640307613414,15.5358765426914));
#1163=CARTESIAN_POINT('',(4.85786866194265,-1.29944626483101,15.6253330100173));
#1164=CARTESIAN_POINT('',(5.01348618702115,-0.385694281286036,15.7129469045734));
#1165=CARTESIAN_POINT('',(4.99833994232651,0.549366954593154,15.8023743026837));
#1166=CARTESIAN_POINT('',(4.81255087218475,1.45788347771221,15.8900787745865));
#1167=CARTESIAN_POINT('',(4.45939396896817,2.32311276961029,15.9793615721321));
#1168=CARTESIAN_POINT('',(3.95679099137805,3.10355851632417,16.0672769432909));
#1169=CARTESIAN_POINT('',(3.31458677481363,3.78084164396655,16.1563000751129));
#1170=CARTESIAN_POINT('',(2.56227968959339,4.32721971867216,16.2445434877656));
#1171=CARTESIAN_POINT('',(1.71963982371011,4.72470625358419,16.3332021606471));
#1172=CARTESIAN_POINT('',(0.818677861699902,4.96196199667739,16.4218621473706));
#1173=CARTESIAN_POINT('',(-0.108861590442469,5.02668375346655,16.510102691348));
#1174=CARTESIAN_POINT('',(-1.03621814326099,4.92113115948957,16.5991222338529));
#1175=CARTESIAN_POINT('',(-1.92272932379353,4.64573876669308,16.6870442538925));
#1176=CARTESIAN_POINT('',(-2.7497563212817,4.2106088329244,16.7763394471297));
#1177=CARTESIAN_POINT('',(-3.47551863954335,3.63339850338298,16.8640261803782));
#1178=CARTESIAN_POINT('',(-4.08883691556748,2.92737991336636,16.9534226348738));
#1179=CARTESIAN_POINT('',(-4.55626308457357,2.12686226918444,17.0410734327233));
#1180=CARTESIAN_POINT('',(-4.87171554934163,1.24643845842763,17.1306019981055));
#1181=CARTESIAN_POINT('',(-5.01748513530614,0.33122289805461,17.2181812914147));
#1182=CARTESIAN_POINT('',(-4.99150062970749,-0.603721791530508,17.3074048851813));
#1183=CARTESIAN_POINT('',(-4.79699558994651,-1.5107968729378,17.3952916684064));
#1184=CARTESIAN_POINT('',(-4.43169203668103,-2.37308192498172,17.4846904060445));
#1185=CARTESIAN_POINT('',(-3.93332079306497,-3.14018785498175,17.5726412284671));
#1186=CARTESIAN_POINT('',(-3.23427326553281,-3.8385410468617,17.6613522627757));
#1187=CARTESIAN_POINT('',(-2.84658155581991,-4.12987645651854,17.7203333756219));
#1188=CARTESIAN_POINT('',(-2.49991764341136,-4.33002295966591,17.749737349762));
#1189=CARTESIAN_POINT('',(6.5,0.,0.75));
#1190=CARTESIAN_POINT('',(6.47803879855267,0.400819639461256,0.779446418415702));
#1191=CARTESIAN_POINT('',(6.43402565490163,1.20411505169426,0.838460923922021));
#1192=CARTESIAN_POINT('',(6.09077083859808,2.36877362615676,0.92702323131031));
#1193=CARTESIAN_POINT('',(5.55180292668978,3.45210939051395,1.0156581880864));
#1194=CARTESIAN_POINT('',(4.81980996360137,4.41698855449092,1.10417552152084));
#1195=CARTESIAN_POINT('',(3.92231791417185,5.22874283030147,1.19270781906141));
#1196=CARTESIAN_POINT('',(2.89150520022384,5.86322878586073,1.28123286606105));
#1197=CARTESIAN_POINT('',(1.76058421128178,6.29519397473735,1.36980802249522));
#1198=CARTESIAN_POINT('',(0.569789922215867,6.51242937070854,1.45832328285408));
#1199=CARTESIAN_POINT('',(-0.640762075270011,6.50545141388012,1.54688530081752));
#1200=CARTESIAN_POINT('',(-1.82922132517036,6.27588442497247,1.63540445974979));
#1201=CARTESIAN_POINT('',(-2.95512377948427,5.83112363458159,1.7239692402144));
#1202=CARTESIAN_POINT('',(-3.97933162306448,5.18600612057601,1.81249157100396));
#1203=CARTESIAN_POINT('',(-4.86779587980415,4.36377561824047,1.90104849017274));
#1204=CARTESIAN_POINT('',(-5.58820585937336,3.39102061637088,1.98957838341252));
#1205=CARTESIAN_POINT('',(-6.1186037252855,2.3028796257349,2.07812763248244));
#1206=CARTESIAN_POINT('',(-6.43715274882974,1.13504232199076,2.16666656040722));
#1207=CARTESIAN_POINT('',(-6.53735656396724,-0.0713012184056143,2.25520603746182));
#1208=CARTESIAN_POINT('',(-6.41081294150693,-1.27520680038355,2.34375453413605));
#1209=CARTESIAN_POINT('',(-6.06701483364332,-2.43582376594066,2.43228490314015));
#1210=CARTESIAN_POINT('',(-5.51278706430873,-3.51206521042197,2.52084187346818));
#1211=CARTESIAN_POINT('',(-4.77158359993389,-4.46903238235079,2.6093648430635));
#1212=CARTESIAN_POINT('',(-3.86513544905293,-5.27143453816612,2.69792788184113));
#1213=CARTESIAN_POINT('',(-2.82732227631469,-5.89439460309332,2.7864463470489));
#1214=CARTESIAN_POINT('',(-1.69182218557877,-6.31408899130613,2.8750122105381));
#1215=CARTESIAN_POINT('',(-0.498714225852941,-6.51811167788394,2.96352965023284));
#1216=CARTESIAN_POINT('',(0.711695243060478,-6.4982025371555,3.05209471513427));
#1217=CARTESIAN_POINT('',(1.89753943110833,-6.25544558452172,3.14061474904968));
#1218=CARTESIAN_POINT('',(3.01860851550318,-5.79865604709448,3.22917549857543));
#1219=CARTESIAN_POINT('',(4.03560159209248,-5.14220099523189,3.31770140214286));
#1220=CARTESIAN_POINT('',(4.91518269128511,-4.31049178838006,3.40625489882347));
#1221=CARTESIAN_POINT('',(5.62479780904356,-3.32981635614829,3.49478913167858));
#1222=CARTESIAN_POINT('',(6.14342757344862,-2.23603196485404,3.58333348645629));
#1223=CARTESIAN_POINT('',(6.44911757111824,-1.06474431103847,3.67187724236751));
#1224=CARTESIAN_POINT('',(6.53619781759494,0.142601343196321,3.76041204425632));
#1225=CARTESIAN_POINT('',(6.3965364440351,1.34507008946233,3.84896500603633));
#1226=CARTESIAN_POINT('',(6.04003785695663,2.5018348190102,3.93749136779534));
#1227=CARTESIAN_POINT('',(5.47419946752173,3.57202699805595,4.02605173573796));
#1228=CARTESIAN_POINT('',(4.72248528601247,4.52074942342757,4.11457204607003));
#1229=CARTESIAN_POINT('',(3.80746018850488,5.31336082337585,4.20313693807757));
#1230=CARTESIAN_POINT('',(2.76280784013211,5.92477832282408,4.29165443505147));
#1231=CARTESIAN_POINT('',(1.62287840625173,6.33228183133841,4.38022035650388));
#1232=CARTESIAN_POINT('',(0.427573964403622,6.52303938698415,4.4687386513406));
#1233=CARTESIAN_POINT('',(-0.78254677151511,6.49017803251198,4.55730197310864));
#1234=CARTESIAN_POINT('',(-1.96563038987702,6.23426179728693,4.64582457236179));
#1235=CARTESIAN_POINT('',(-3.08173197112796,5.76549033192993,4.73438200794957));
#1236=CARTESIAN_POINT('',(-4.0913981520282,5.09779625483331,4.82291183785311));
#1237=CARTESIAN_POINT('',(-4.9619760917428,4.25668531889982,4.91146091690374));
#1238=CARTESIAN_POINT('',(-5.66073777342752,3.26822675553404,4.999999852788));
#1239=CARTESIAN_POINT('',(-6.1674919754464,2.16890628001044,5.08853938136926));
#1240=CARTESIAN_POINT('',(-6.46033993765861,0.994324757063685,5.17708788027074));
#1241=CARTESIAN_POINT('',(-6.53422990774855,-0.213884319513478,5.26561823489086));
#1242=CARTESIAN_POINT('',(-6.38152240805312,-1.41477755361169,5.35417520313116));
#1243=CARTESIAN_POINT('',(-6.01232098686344,-2.56753904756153,5.44269817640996));
#1244=CARTESIAN_POINT('',(-5.43497604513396,-3.63157394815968,5.53126121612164));
#1245=CARTESIAN_POINT('',(-4.67281556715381,-4.57191794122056,5.61977968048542));
#1246=CARTESIAN_POINT('',(-3.7493384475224,-5.35466556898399,5.70834554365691));
#1247=CARTESIAN_POINT('',(-2.69796356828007,-5.95445113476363,5.79686298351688));
#1248=CARTESIAN_POINT('',(-1.5537413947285,-6.34972708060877,5.88542804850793));
#1249=CARTESIAN_POINT('',(-0.356384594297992,-6.52719276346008,5.97394808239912));
#1250=CARTESIAN_POINT('',(0.853306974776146,-6.48137921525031,6.06250883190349));
#1251=CARTESIAN_POINT('',(2.0334887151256,-6.2123453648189,6.1510347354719));
#1252=CARTESIAN_POINT('',(3.14448588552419,-5.73162881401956,6.23958823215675));
#1253=CARTESIAN_POINT('',(4.14671672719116,-5.05279801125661,6.32812246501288));
#1254=CARTESIAN_POINT('',(5.00816558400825,-4.20235871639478,6.41666681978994));
#1255=CARTESIAN_POINT('',(5.69602419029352,-3.206260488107,6.50521057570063));
#1256=CARTESIAN_POINT('',(6.19078938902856,-2.10150988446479,6.59374537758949));
#1257=CARTESIAN_POINT('',(6.47081915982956,-0.923791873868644,6.6822983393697));
#1258=CARTESIAN_POINT('',(6.53145690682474,0.285141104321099,6.77082470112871));
#1259=CARTESIAN_POINT('',(6.36577003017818,1.48432092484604,6.85938506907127));
#1260=CARTESIAN_POINT('',(5.98387194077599,2.63292977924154,6.94790537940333));
#1261=CARTESIAN_POINT('',(5.3951186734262,3.69069787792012,7.0364702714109));
#1262=CARTESIAN_POINT('',(4.62258367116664,4.62253453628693,7.1249877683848));
#1263=CARTESIAN_POINT('',(3.69077480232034,5.39534140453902,7.2135536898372));
#1264=CARTESIAN_POINT('',(2.63279896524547,5.98341306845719,7.30207198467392));
#1265=CARTESIAN_POINT('',(1.4844181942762,6.36641916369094,7.39063530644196));
#1266=CARTESIAN_POINT('',(0.285154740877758,6.53057499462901,7.4791579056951));
#1267=CARTESIAN_POINT('',(-0.923966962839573,6.47180313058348,7.56771534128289));
#1268=CARTESIAN_POINT('',(-2.10110764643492,6.1897021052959,7.65624517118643));
#1269=CARTESIAN_POINT('',(-3.20686019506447,5.69707155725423,7.74479425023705));
#1270=CARTESIAN_POINT('',(-4.20155413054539,5.00721490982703,7.83333318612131));
#1271=CARTESIAN_POINT('',(-5.05373706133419,4.14751171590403,7.92187271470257));
#1272=CARTESIAN_POINT('',(-5.73065467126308,3.14392602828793,8.01042121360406));
#1273=CARTESIAN_POINT('',(-6.213320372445,2.03385273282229,8.09895156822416));
#1274=CARTESIAN_POINT('',(-6.48055193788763,0.853153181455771,8.18750853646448));
#1275=CARTESIAN_POINT('',(-6.52788373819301,-0.356362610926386,8.27603150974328));
#1276=CARTESIAN_POINT('',(-6.34927832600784,-1.55369195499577,8.36459454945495));
#1277=CARTESIAN_POINT('',(-5.95469833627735,-2.69800050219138,8.45311301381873));
#1278=CARTESIAN_POINT('',(-5.35462915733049,-3.74939044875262,8.54167887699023));
#1279=CARTESIAN_POINT('',(-4.57179868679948,-4.67259590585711,8.6301963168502));
#1280=CARTESIAN_POINT('',(-3.63177388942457,-5.43538082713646,8.71876138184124));
#1281=CARTESIAN_POINT('',(-2.56732337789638,-6.01166416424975,8.80728141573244));
#1282=CARTESIAN_POINT('',(-1.41491598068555,-6.3823523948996,8.8958421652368));
#1283=CARTESIAN_POINT('',(-0.213892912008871,-6.53318919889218,8.98436806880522));
#1284=CARTESIAN_POINT('',(0.994517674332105,-6.46144681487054,9.07292156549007));
#1285=CARTESIAN_POINT('',(2.16848040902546,-6.16633765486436,9.1614557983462));
#1286=CARTESIAN_POINT('',(3.26884491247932,-5.66181898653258,9.25000015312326));
#1287=CARTESIAN_POINT('',(4.25590622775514,-4.96105433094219,9.33854390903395));
#1288=CARTESIAN_POINT('',(5.09868039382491,-4.09214800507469,9.42707871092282));
#1289=CARTESIAN_POINT('',(5.76462558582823,-3.08123090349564,9.51563167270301));
#1290=CARTESIAN_POINT('',(6.23508585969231,-1.96594483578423,9.60415803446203));
#1291=CARTESIAN_POINT('',(6.48953477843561,-0.782416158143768,9.69271840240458));
#1292=CARTESIAN_POINT('',(6.52351532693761,0.427539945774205,9.78123871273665));
#1293=CARTESIAN_POINT('',(6.33204622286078,1.62288229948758,9.86980360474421));
#1294=CARTESIAN_POINT('',(5.92480768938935,2.76274486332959,9.95832110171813));
#1295=CARTESIAN_POINT('',(5.31350928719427,3.80764317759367,10.0468870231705));
#1296=CARTESIAN_POINT('',(4.52046955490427,4.72209882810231,10.1354053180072));
#1297=CARTESIAN_POINT('',(3.57234041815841,5.4747761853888,10.2239686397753));
#1298=CARTESIAN_POINT('',(2.50154600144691,6.03920446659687,10.3124912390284));
#1299=CARTESIAN_POINT('',(1.34524209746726,6.39752095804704,10.4010486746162));
#1300=CARTESIAN_POINT('',(0.142607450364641,6.53503853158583,10.4895785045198));
#1301=CARTESIAN_POINT('',(-1.06494963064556,6.45030688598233,10.5781275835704));
#1302=CARTESIAN_POINT('',(-2.23560105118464,6.14225904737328,10.6666665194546));
#1303=CARTESIAN_POINT('',(-3.3304268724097,5.62586602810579,10.7552060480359));
#1304=CARTESIAN_POINT('',(-4.30976787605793,4.91432342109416,10.8437545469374));
#1305=CARTESIAN_POINT('',(-5.14299270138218,4.0362771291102,10.9322849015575));
#1306=CARTESIAN_POINT('',(-5.79793126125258,3.01818105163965,11.0208418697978));
#1307=CARTESIAN_POINT('',(-6.25608736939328,1.89779641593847,11.1093648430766));
#1308=CARTESIAN_POINT('',(-6.49776393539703,0.711588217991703,11.1979278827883));
#1309=CARTESIAN_POINT('',(-6.51835660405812,-0.498664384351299,11.2864463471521));
#1310=CARTESIAN_POINT('',(-6.31407256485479,-1.69188350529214,11.3750122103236));
#1311=CARTESIAN_POINT('',(-5.89420741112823,-2.82715665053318,11.4635296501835));
#1312=CARTESIAN_POINT('',(-5.27176085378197,-3.86544742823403,11.5520947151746));
#1313=CARTESIAN_POINT('',(-4.46860507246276,-4.77104014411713,11.6406147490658));
#1314=CARTESIAN_POINT('',(-3.51247918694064,-5.51351968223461,11.7291754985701));
#1315=CARTESIAN_POINT('',(-2.43547589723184,-6.06603399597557,11.8177014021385));
#1316=CARTESIAN_POINT('',(-1.27540404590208,-6.41191896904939,11.9062548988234));
#1317=CARTESIAN_POINT('',(-0.071306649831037,-6.53612597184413,11.9947891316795));
#1318=CARTESIAN_POINT('',(1.13525330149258,-6.43838032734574,12.0833334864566));
#1319=CARTESIAN_POINT('',(2.30246316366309,-6.11747180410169,12.1718772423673));
#1320=CARTESIAN_POINT('',(3.39159529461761,-5.58921268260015,12.2604120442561));
#1321=CARTESIAN_POINT('',(4.36313308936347,-4.86702801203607,12.3489650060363));
#1322=CARTESIAN_POINT('',(5.18667143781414,-3.97990881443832,12.4374913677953));
#1323=CARTESIAN_POINT('',(5.83056585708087,-2.95478230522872,12.5260517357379));
#1324=CARTESIAN_POINT('',(6.2763264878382,-1.82941751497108,12.61457204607));
#1325=CARTESIAN_POINT('',(6.50523554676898,-0.640676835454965,12.7031369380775));
#1326=CARTESIAN_POINT('',(6.51241245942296,0.569727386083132,12.7916544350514));
#1327=CARTESIAN_POINT('',(6.29535613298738,1.76068698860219,12.8802203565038));
#1328=CARTESIAN_POINT('',(5.86290480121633,2.89122977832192,12.9687386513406));
#1329=CARTESIAN_POINT('',(5.22938566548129,3.92279440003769,13.0573019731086));
#1330=CARTESIAN_POINT('',(4.41621389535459,4.81941675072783,13.1458245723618));
#1331=CARTESIAN_POINT('',(3.45219510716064,5.55160334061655,13.2343820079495));
#1332=CARTESIAN_POINT('',(2.36912198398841,6.09215286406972,13.3229118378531));
#1333=CARTESIAN_POINT('',(1.20540957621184,6.42554000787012,13.4114609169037));
#1334=CARTESIAN_POINT('',(-1.49109357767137E-06,6.53645609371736,13.499999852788));
#1335=CARTESIAN_POINT('',(-1.20541805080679,6.4256578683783,13.5885393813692));
#1336=CARTESIAN_POINT('',(-2.36905946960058,6.0919808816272,13.6770878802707));
#1337=CARTESIAN_POINT('',(-3.45234420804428,5.55186693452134,13.7656182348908));
#1338=CARTESIAN_POINT('',(-4.41599450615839,4.81917174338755,13.8541752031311));
#1339=CARTESIAN_POINT('',(-5.22971453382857,3.92305318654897,13.9426981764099));
#1340=CARTESIAN_POINT('',(-5.86252331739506,2.89104034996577,14.0312612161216));
#1341=CARTESIAN_POINT('',(-6.29580486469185,1.76081801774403,14.1197796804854));
#1342=CARTESIAN_POINT('',(-6.51194563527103,0.569689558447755,14.2083455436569));
#1343=CARTESIAN_POINT('',(-6.50568773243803,-0.640720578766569,14.2968629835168));
#1344=CARTESIAN_POINT('',(-6.27589565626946,-1.82928402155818,14.3854280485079));
#1345=CARTESIAN_POINT('',(-5.83090704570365,-2.95495826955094,14.473948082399));
#1346=CARTESIAN_POINT('',(-5.18638556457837,-3.97967512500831,14.5625088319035));
#1347=CARTESIAN_POINT('',(-4.36330454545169,-4.86722556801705,14.6510347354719));
#1348=CARTESIAN_POINT('',(-3.39149321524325,-5.58901906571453,14.7395882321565));
#1349=CARTESIAN_POINT('',(-2.3024930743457,-6.11756103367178,14.8281224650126));
#1350=CARTESIAN_POINT('',(-1.13526661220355,-6.43837798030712,14.9166668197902));
#1351=CARTESIAN_POINT('',(0.0713090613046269,-6.53603189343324,15.0052105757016));
#1352=CARTESIAN_POINT('',(1.27543374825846,-6.4121358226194,15.0937453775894));
#1353=CARTESIAN_POINT('',(2.43538234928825,-6.06578971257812,15.1822983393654));
#1354=CARTESIAN_POINT('',(3.51266789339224,-5.51383705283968,15.2708247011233));
#1355=CARTESIAN_POINT('',(4.46834464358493,-4.77075809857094,15.3593850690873));
#1356=CARTESIAN_POINT('',(5.27212004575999,-3.86572022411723,15.4479053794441));
#1357=CARTESIAN_POINT('',(5.89379745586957,-2.82696088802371,15.5364702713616));
#1358=CARTESIAN_POINT('',(6.31452417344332,-1.69200762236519,15.6249877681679));
#1359=CARTESIAN_POINT('',(6.51789012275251,-0.498634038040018,15.7135536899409));
#1360=CARTESIAN_POINT('',(6.49818720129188,0.711635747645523,15.8020719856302));
#1361=CARTESIAN_POINT('',(6.25568981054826,1.89766571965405,15.8906353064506));
#1362=CARTESIAN_POINT('',(5.79822122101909,3.0183362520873,15.9791579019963));
#1363=CARTESIAN_POINT('',(5.14276249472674,4.036080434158,16.0677153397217));
#1364=CARTESIAN_POINT('',(4.30988543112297,4.91446361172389,16.1562451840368));
#1365=CARTESIAN_POINT('',(3.33037839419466,5.62575801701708,16.244794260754));
#1366=CARTESIAN_POINT('',(2.23559824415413,6.14226028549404,16.3333331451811));
#1367=CARTESIAN_POINT('',(1.06498238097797,6.45042149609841,16.4218726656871));
#1368=CARTESIAN_POINT('',(-0.142607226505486,6.53485456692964,16.5104213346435));
#1369=CARTESIAN_POINT('',(-1.34529177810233,6.39781606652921,16.5989517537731));
#1370=CARTESIAN_POINT('',(-2.50142564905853,6.03890224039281,16.687508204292));
#1371=CARTESIAN_POINT('',(-3.57256720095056,5.47514244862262,16.7760309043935));
#1372=CARTESIAN_POINT('',(-4.52016795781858,4.72178283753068,16.8645954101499));
#1373=CARTESIAN_POINT('',(-5.313853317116,3.80789649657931,16.9531147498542));
#1374=CARTESIAN_POINT('',(-5.92440386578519,2.76256665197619,17.0416766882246));
#1375=CARTESIAN_POINT('',(-6.33260379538,1.62302507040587,17.1301918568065));
#1376=CARTESIAN_POINT('',(-6.52301737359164,0.427468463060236,17.2187672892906));
#1377=CARTESIAN_POINT('',(-6.48959308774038,-0.782443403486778,17.3072919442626));
#1378=CARTESIAN_POINT('',(-6.23484691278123,-1.96563514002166,17.3958249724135));
#1379=CARTESIAN_POINT('',(-5.765579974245,-3.0815324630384,17.4843401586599));
#1380=CARTESIAN_POINT('',(-5.09797767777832,-4.09263332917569,17.5729822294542));
#1381=CARTESIAN_POINT('',(-4.25486215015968,-4.96096647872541,17.6615197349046));
#1382=CARTESIAN_POINT('',(-3.59661837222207,-5.42889327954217,17.7205943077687));
#1383=CARTESIAN_POINT('',(-3.24993433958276,-5.62905139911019,17.7499999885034));
#1384=(BOUNDED_SURFACE() B_SPLINE_SURFACE(3,3,((#19,#20,#21,#22,#23,#24,#25,#26,#27,#28,#29,#30,
#31,#32,#33,#34,#35,#36,#37,#38,#39,#40,#41,#42,#43,#44,#45,#46,#47,#48,#49,#50,#51,#52,#53,#54,
#55,#56,#57,#58,#59,#60,#61,#62,#63,#64,#65,#66,#67,#68,#69,#70,#71,#72,#73,#74,#75,#76,#77,#78,
#79,#80,#81,#82,#83,#84,#85,#86,#87,#88,#89,#90,#91,#92,#93,#94,#95,#96,#97,#98,#99,#100,#101,
#102,#103,#104,#105,#106,#107,#108,#109,#110,#111,#112,#113,#114,#115,#116,#117,#118,#119,#120,
#121,#122,#123,#124,#125,#126,#127,#128,#129,#130,#131,#132,#133,#134,#135,#136,#137,#138,#139,
#140,#141,#142,#143,#144,#145,#146,#147,#148,#149,#150,#151,#152,#153,#154,#155,#156,#157,#158,
#159,#160,#161,#162,#163,#164,#165,#166,#167,#168,#169,#170,#171,#172,#173,#174,#175,#176,#177,
#178,#179,#180,#181,#182,#183,#184,#185,#186,#187,#188,#189,#190,#191,#192,#193,#194,#195,#196,
#197,#198,#199,#200,#201,#202,#203,#204,#205,#206,#207,#208,#209,#210,#211,#212,#213),(#214,
#215,#216,#217,#218,#219,#220,#221,#222,#223,#224,#225,#226,#227,#228,#229,#230,#231,#232,#233,
#234,#235,#236,#237,#238,#239,#240,#241,#242,#243,#244,#245,#246,#247,#248,#249,#250,#251,#252,
#253,#254,#255,#256,#257,#258,#259,#260,#261,#262,#263,#264,#265,#266,#267,#268,#269,#270,#271,
#272,#273,#274,#275,#276,#277,#278,#279,#280,#281,#282,#283,#284,#285,#286,#287,#288,#289,#290,
#291,#292,#293,#294,#295,#296,#297,#298,#299,#300,#301,#302,#303,#304,#305,#306,#307,#308,#309,
#310,#311,#312,#313,#314,#315,#316,#317,#318,#319,#320,#321,#322,#323,#324,#325,#326,#327,#328,
#329,#330,#331,#332,#333,#334,#335,#336,#337,#338,#339,#340,#341,#342,#343,#344,#345,#346,#347,
#348,#349,#350,#351,#352,#353,#354,#355,#356,#357,#358,#359,#360,#361,#362,#363,#364,#365,#366,
#367,#368,#369,#370,#371,#372,#373,#374,#375,#376,#377,#378,#379,#380,#381,#382,#383,#384,#385,
#386,#387,#388,#389,#390,#391,#392,#393,#394,#395,#396,#397,#398,#399,#400,#401,#402,#403,#404,
#405,#406,#407,#408),(#409,#410,#411,#412,#413,#414,#415,#416,#417,#418,#419,#420,#421,#422,
#423,#424,#425,#426,#427,#428,#429,#430,#431,#432,#433,#434,#435,#436,#437,#438,#439,#440,#441,
#442,#443,#444,#445,#446,#447,#448,#449,#450,#451,#452,#453,#454,#455,#456,#457,#458,#459,#460,
#461,#462,#463,#464,#465,#466,#467,#468,#469,#470,#471,#472,#473,#474,#475,#476,#477,#478,#479,
#480,#481,#482,#483,#484,#485,#486,#487,#488,#489,#490,#491,#492,#493,#494,#495,#496,#497,#498,
#499,#500,#501,#502,#503,#504,#505,#506,#507,#508,#509,#510,#511,#512,#513,#514,#515,#516,#517,
#518,#519,#520,#521,#522,#523,#524,#525,#526,#527,#528,#529,#530,#531,#532,#533,#534,#535,#536,
#537,#538,#539,#540,#541,#542,#543,#544,#545,#546,#547,#548,#549,#550,#551,#552,#553,#554,#555,
#556,#557,#558,#559,#560,#561,#562,#563,#564,#565,#566,#567,#568,#569,#570,#571,#572,#573,#574,
#575,#576,#577,#578,#579,#580,#581,#582,#583,#584,#585,#586,#587,#588,#589,#590,#591,#592,#593,
#594,#595,#596,#597,#598,#599,#600,#601,#602,#603),(#604,#605,#606,#607,#608,#609,#610,#611,
#612,#613,#614,#615,#616,#617,#618,#619,#620,#621,#622,#623,#624,#625,#626,#627,#628,#629,#630,
#631,#632,#633,#634,#635,#636,#637,#638,#639,#640,#641,#642,#643,#644,#645,#646,#647,#648,#649,
#650,#651,#652,#653,#654,#655,#656,#657,#658,#659,#660,#661,#662,#663,#664,#665,#666,#667,#668,
#669,#670,#671,#672,#673,#674,#675,#676,#677,#678,#679,#680,#681,#682,#683,#684,#685,#686,#687,
#688,#689,#690,#691,#692,#693,#694,#695,#696,#697,#698,#699,#700,#701,#702,#703,#704,#705,#706,
#707,#708,#709,#710,#711,#712,#713,#714,#715,#716,#717,#718,#719,#720,#721,#722,#723,#724,#725,
#726,#727,#728,#729,#730,#731,#732,#733,#734,#735,#736,#737,#738,#739,#740,#741,#742,#743,#744,
#745,#746,#747,#748,#749,#750,#751,#752,#753,#754,#755,#756,#757,#758,#759,#760,#761,#762,#763,
#764,#765,#766,#767,#768,#769,#770,#771,#772,#773,#774,#775,#776,#777,#778,#779,#780,#781,#782,
#783,#784,#785,#786,#787,#788,#789,#790,#791,#792,#793,#794,#795,#796,#797,#798),(#799,#800,
#801,#802,#803,#804,#805,#806,#807,#808,#809,#810,#811,#812,#813,#814,#815,#816,#817,#818,#819,
#820,#821,#822,#823,#824,#825,#826,#827,#828,#829,#830,#831,#832,#833,#834,#835,#836,#837,#838,
#839,#840,#841,#842,#843,#844,#845,#846,#847,#848,#849,#850,#851,#852,#853,#854,#855,#856,#857,
#858,#859,#860,#861,#862,#863,#864,#865,#866,#867,#868,#869,#870,#871,#872,#873,#874,#875,#876,
#877,#878,#879,#880,#881,#882,#883,#884,#885,#886,#887,#888,#889,#890,#891,#892,#893,#894,#895,
#896,#897,#898,#899,#900,#901,#902,#903,#904,#905,#906,#907,#908,#909,#910,#911,#912,#913,#914,
#915,#916,#917,#918,#919,#920,#921,#922,#923,#924,#925,#926,#927,#928,#929,#930,#931,#932,#933,
#934,#935,#936,#937,#938,#939,#940,#941,#942,#943,#944,#945,#946,#947,#948,#949,#950,#951,#952,
#953,#954,#955,#956,#957,#958,#959,#960,#961,#962,#963,#964,#965,#966,#967,#968,#969,#970,#971,
#972,#973,#974,#975,#976,#977,#978,#979,#980,#981,#982,#983,#984,#985,#986,#987,#988,#989,#990,
#991,#992,#993),(#994,#995,#996,#997,#998,#999,#1000,#1001,#1002,#1003,#1004,#1005,#1006,#1007,
#1008,#1009,#1010,#1011,#1012,#1013,#1014,#1015,#1016,#1017,#1018,#1019,#1020,#1021,#1022,#1023,
#1024,#1025,#1026,#1027,#1028,#1029,#1030,#1031,#1032,#1033,#1034,#1035,#1036,#1037,#1038,#1039,
#1040,#1041,#1042,#1043,#1044,#1045,#1046,#1047,#1048,#1049,#1050,#1051,#1052,#1053,#1054,#1055,
#1056,#1057,#1058,#1059,#1060,#1061,#1062,#1063,#1064,#1065,#1066,#1067,#1068,#1069,#1070,#1071,
#1072,#1073,#1074,#1075,#1076,#1077,#1078,#1079,#1080,#1081,#1082,#1083,#1084,#1085,#1086,#1087,
#1088,#1089,#1090,#1091,#1092,#1093,#1094,#1095,#1096,#1097,#1098,#1099,#1100,#1101,#1102,#1103,
#1104,#1105,#1106,#1107,#1108,#1109,#1110,#1111,#1112,#1113,#1114,#1115,#1116,#1117,#1118,#1119,
#1120,#1121,#1122,#1123,#1124,#1125,#1126,#1127,#1128,#1129,#1130,#1131,#1132,#1133,#1134,#1135,
#1136,#1137,#1138,#1139,#1140,#1141,#1142,#1143,#1144,#1145,#1146,#1147,#1148,#1149,#1150,#1151,
#1152,#1153,#1154,#1155,#1156,#1157,#1158,#1159,#1160,#1161,#1162,#1163,#1164,#1165,#1166,#1167,
#1168,#1169,#1170,#1171,#1172,#1173,#1174,#1175,#1176,#1177,#1178,#1179,#1180,#1181,#1182,#1183,
#1184,#1185,#1186,#1187,#1188),(#1189,#1190,#1191,#1192,#1193,#1194,#1195,#1196,#1197,#1198,
#1199,#1200,#1201,#1202,#1203,#1204,#1205,#1206,#1207,#1208,#1209,#1210,#1211,#1212,#1213,#1214,
#1215,#1216,#1217,#1218,#1219,#1220,#1221,#1222,#1223,#1224,#1225,#1226,#1227,#1228,#1229,#1230,
#1231,#1232,#1233,#1234,#1235,#1236,#1237,#1238,#1239,#1240,#1241,#1242,#1243,#1244,#1245,#1246,
#1247,#1248,#1249,#1250,#1251,#1252,#1253,#1254,#1255,#1256,#1257,#1258,#1259,#1260,#1261,#1262,
#1263,#1264,#1265,#1266,#1267,#1268,#1269,#1270,#1271,#1272,#1273,#1274,#1275,#1276,#1277,#1278,
#1279,#1280,#1281,#1282,#1283,#1284,#1285,#1286,#1287,#1288,#1289,#1290,#1291,#1292,#1293,#1294,
#1295,#1296,#1297,#1298,#1299,#1300,#1301,#1302,#1303,#1304,#1305,#1306,#1307,#1308,#1309,#1310,
#1311,#1312,#1313,#1314,#1315,#1316,#1317,#1318,#1319,#1320,#1321,#1322,#1323,#1324,#1325,#1326,
#1327,#1328,#1329,#1330,#1331,#1332,#1333,#1334,#1335,#1336,#1337,#1338,#1339,#1340,#1341,#1342,
#1343,#1344,#1345,#1346,#1347,#1348,#1349,#1350,#1351,#1352,#1353,#1354,#1355,#1356,#1357,#1358,
#1359,#1360,#1361,#1362,#1363,#1364,#1365,#1366,#1367,#1368,#1369,#1370,#1371,#1372,#1373,#1374,
#1375,#1376,#1377,#1378,#1379,#1380,#1381,#1382,#1383)),.UNSPECIFIED.,.T.,.F.,
.F.) B_SPLINE_SURFACE_WITH_KNOTS((4,3,4),(4,1,1,1,1,1,1,1,1,1,1,1,1,1,1,1,1,1,1,1,1,1,1,1,1,1,1,
1,1,1,1,1,1,1,1,1,1,1,1,1,1,1,1,1,1,1,1,1,1,1,1,1,1,1,1,1,1,1,1,1,1,1,1,1,1,1,1,1,1,1,1,1,1,1,1,
1,1,1,1,1,1,1,1,1,1,1,1,1,1,1,1,1,1,1,1,1,1,1,1,1,1,1,1,1,1,1,1,1,1,1,1,1,1,1,1,1,1,1,1,1,1,1,1,
1,1,1,1,1,1,1,1,1,1,1,1,1,1,1,1,1,1,1,1,1,1,1,1,1,1,1,1,1,1,1,1,1,1,1,1,1,1,1,1,1,1,1,1,1,1,1,1,
1,1,1,1,1,1,1,1,1,1,1,1,1,1,1,1,1,1,1,1,1,4),(0.,0.5,1.),(0.,0.00519683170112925,
0.0104151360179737,0.0156272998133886,0.0208339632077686,0.026040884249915,0.0312498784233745,
0.0364579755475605,0.0416667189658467,0.0468746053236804,0.0520833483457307,0.057291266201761,
0.0624999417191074,0.0677080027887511,0.0729165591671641,0.0781247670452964,0.0833331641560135,
0.0885415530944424,0.0937497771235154,0.0989583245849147,0.104166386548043,0.109375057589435,
0.114583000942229,0.119791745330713,0.124999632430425,0.130208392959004,0.135416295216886,
0.140625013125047,0.145832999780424,0.151041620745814,0.156249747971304,0.161458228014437,
0.166666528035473,0.171874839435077,0.177083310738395,0.182291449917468,0.187500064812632,
0.19270806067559,0.197916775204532,0.203124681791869,0.208333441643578,0.213541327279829,
0.218750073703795,0.223958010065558,0.229166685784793,0.23437473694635,0.239583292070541,
0.24479150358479,0.249999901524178,0.255208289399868,0.260416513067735,0.265625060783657,
0.270833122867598,0.276041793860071,0.281249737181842,0.286458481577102,0.291666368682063,
0.296875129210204,0.30208303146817,0.307291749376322,0.312499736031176,0.317708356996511,
0.32291648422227,0.328124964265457,0.333333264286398,0.338541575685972,0.343750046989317,
0.348958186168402,0.354166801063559,0.359374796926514,0.364583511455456,0.369791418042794,
0.375000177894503,0.380208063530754,0.38541680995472,0.390624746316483,0.395833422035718,
0.401041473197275,0.406250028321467,0.411458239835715,0.416666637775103,0.421875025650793,
0.42708324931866,0.432291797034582,0.437499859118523,0.442708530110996,0.447916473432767,
0.453125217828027,0.458333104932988,0.463541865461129,0.468749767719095,0.473958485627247,
0.479166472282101,0.484375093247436,0.489583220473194,0.494791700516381,0.500000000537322,
0.505208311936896,0.510416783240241,0.515624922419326,0.520833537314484,0.526041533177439,
0.531250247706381,0.536458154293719,0.541666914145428,0.546874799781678,0.552083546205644,
0.557291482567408,0.562500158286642,0.567708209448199,0.572916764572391,0.578124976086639,
0.583333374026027,0.588541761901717,0.593749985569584,0.598958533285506,0.604166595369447,
0.60937526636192,0.614583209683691,0.619791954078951,0.624999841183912,0.630208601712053,
0.635416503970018,0.64062522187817,0.645833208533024,0.651041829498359,0.656249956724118,
0.661458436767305,0.666666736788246,0.67187504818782,0.677083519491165,0.68229165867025,
0.687500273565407,0.692708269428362,0.697916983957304,0.703124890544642,0.708333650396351,
0.713541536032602,0.718750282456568,0.723958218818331,0.729166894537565,0.734374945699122,
0.739583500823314,0.744791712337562,0.750000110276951,0.75520849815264,0.760416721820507,
0.76562526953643,0.77083333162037,0.776042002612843,0.781249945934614,0.786458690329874,
0.791666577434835,0.796875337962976,0.80208324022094,0.807291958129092,0.812499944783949,
0.817708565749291,0.822916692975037,0.828125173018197,0.833333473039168,0.838541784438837,
0.843750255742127,0.848958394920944,0.854167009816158,0.859375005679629,0.864583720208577,
0.869791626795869,0.875000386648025,0.880208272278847,0.885417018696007,0.890624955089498,
0.895833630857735,0.901041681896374,0.906250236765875,0.911458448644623,0.916666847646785,
0.921875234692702,0.927083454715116,0.932292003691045,0.937500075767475,0.942708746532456,
0.947916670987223,0.953125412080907,0.958333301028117,0.963542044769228,0.968750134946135,
0.973959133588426,0.979166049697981,0.984372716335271,0.989584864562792,0.994803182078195,1.),
.UNSPECIFIED.) GEOMETRIC_REPRESENTATION_ITEM() RATIONAL_B_SPLINE_SURFACE(((1.,1.,1.,1.,1.,1.,1.,
1.,1.,1.,1.,1.,1.,1.,1.,1.,1.,1.,1.,1.,1.,1.,1.,1.,1.,1.,1.,1.,1.,1.,1.,1.,1.,1.,1.,1.,1.,1.,1.,
1.,1.,1.,1.,1.,1.,1.,1.,1.,1.,1.,1.,1.,1.,1.,1.,1.,1.,1.,1.,1.,1.,1.,1.,1.,1.,1.,1.,1.,1.,1.,1.,
1.,1.,1.,1.,1.,1.,1.,1.,1.,1.,1.,1.,0.999999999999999,1.,1.,1.,1.,1.,1.,1.,1.,1.,1.,1.,1.,1.,1.,
1.,1.,1.,1.,1.,1.,1.,1.,1.,1.,1.,1.,1.,1.,1.,1.,1.,1.,1.,1.,1.,1.,1.,1.,1.,1.,1.,1.,1.,1.,1.,1.,
1.,1.,1.,1.,1.,1.,1.,1.,1.,1.,1.,1.,1.,1.,1.,1.,1.,1.,1.,1.,1.,1.,1.,1.,1.,1.,1.,1.,1.,1.,1.,1.,
1.,1.,1.,1.,1.,1.,1.,1.,1.,1.,1.,1.,1.,1.,1.,1.,1.,1.,1.,1.,1.,1.,1.,1.,1.,1.,1.,1.,1.,1.,1.,1.,
1.),(0.333333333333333,0.333333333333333,0.333333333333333,0.333333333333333,0.333333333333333,
0.333333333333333,0.333333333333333,0.333333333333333,0.333333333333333,0.333333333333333,
0.333333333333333,0.333333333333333,0.333333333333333,0.333333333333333,0.333333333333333,
0.333333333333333,0.333333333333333,0.333333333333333,0.333333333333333,0.333333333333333,
0.333333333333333,0.333333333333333,0.333333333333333,0.333333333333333,0.333333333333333,
0.333333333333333,0.333333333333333,0.333333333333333,0.333333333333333,0.333333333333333,
0.333333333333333,0.333333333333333,0.333333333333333,0.333333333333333,0.333333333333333,
0.333333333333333,0.333333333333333,0.333333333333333,0.333333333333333,0.333333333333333,
0.333333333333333,0.333333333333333,0.333333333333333,0.333333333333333,0.333333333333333,
0.333333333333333,0.333333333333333,0.333333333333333,0.333333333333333,0.333333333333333,
0.333333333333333,0.333333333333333,0.333333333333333,0.333333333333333,0.333333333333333,
0.333333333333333,0.333333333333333,0.333333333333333,0.333333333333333,0.333333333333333,
0.333333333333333,0.333333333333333,0.333333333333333,0.333333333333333,0.333333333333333,
0.333333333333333,0.333333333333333,0.333333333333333,0.333333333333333,0.333333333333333,
0.333333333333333,0.333333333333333,0.333333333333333,0.333333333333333,0.333333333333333,
0.333333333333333,0.333333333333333,0.333333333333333,0.333333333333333,0.333333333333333,
0.333333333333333,0.333333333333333,0.333333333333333,0.333333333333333,0.333333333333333,
0.333333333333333,0.333333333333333,0.333333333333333,0.333333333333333,0.333333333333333,
0.333333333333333,0.333333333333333,0.333333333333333,0.333333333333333,0.333333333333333,
0.333333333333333,0.333333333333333,0.333333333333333,0.333333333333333,0.333333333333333,
0.333333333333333,0.333333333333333,0.333333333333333,0.333333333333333,0.333333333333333,
0.333333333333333,0.333333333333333,0.333333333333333,0.333333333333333,0.333333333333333,
0.333333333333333,0.333333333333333,0.333333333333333,0.333333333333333,0.333333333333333,
0.333333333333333,0.333333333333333,0.333333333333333,0.333333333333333,0.333333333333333,
0.333333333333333,0.333333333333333,0.333333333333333,0.333333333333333,0.333333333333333,
0.333333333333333,0.333333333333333,0.333333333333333,0.333333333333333,0.333333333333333,
0.333333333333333,0.333333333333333,0.333333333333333,0.333333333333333,0.333333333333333,
0.333333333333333,0.333333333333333,0.333333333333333,0.333333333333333,0.333333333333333,
0.333333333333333,0.333333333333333,0.333333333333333,0.333333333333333,0.333333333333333,
0.333333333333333,0.333333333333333,0.333333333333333,0.333333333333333,0.333333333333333,
0.333333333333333,0.333333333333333,0.333333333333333,0.333333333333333,0.333333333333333,
0.333333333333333,0.333333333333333,0.333333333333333,0.333333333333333,0.333333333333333,
0.333333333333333,0.333333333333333,0.333333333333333,0.333333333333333,0.333333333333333,
0.333333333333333,0.333333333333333,0.333333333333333,0.333333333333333,0.333333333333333,
0.333333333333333,0.333333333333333,0.333333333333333,0.333333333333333,0.333333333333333,
0.333333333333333,0.333333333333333,0.333333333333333,0.333333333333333,0.333333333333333,
0.333333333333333,0.333333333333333,0.333333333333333,0.333333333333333,0.333333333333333,
0.333333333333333,0.333333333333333,0.333333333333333,0.333333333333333,0.333333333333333,
0.333333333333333,0.333333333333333,0.333333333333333,0.333333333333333,0.333333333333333),
(0.333333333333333,0.333333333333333,0.333333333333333,0.333333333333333,0.333333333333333,
0.333333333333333,0.333333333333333,0.333333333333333,0.333333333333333,0.333333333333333,
0.333333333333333,0.333333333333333,0.333333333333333,0.333333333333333,0.333333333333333,
0.333333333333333,0.333333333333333,0.333333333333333,0.333333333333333,0.333333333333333,
0.333333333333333,0.333333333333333,0.333333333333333,0.333333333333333,0.333333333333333,
0.333333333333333,0.333333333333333,0.333333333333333,0.333333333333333,0.333333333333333,
0.333333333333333,0.333333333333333,0.333333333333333,0.333333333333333,0.333333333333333,
0.333333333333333,0.333333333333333,0.333333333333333,0.333333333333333,0.333333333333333,
0.333333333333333,0.333333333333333,0.333333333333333,0.333333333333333,0.333333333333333,
0.333333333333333,0.333333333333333,0.333333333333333,0.333333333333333,0.333333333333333,
0.333333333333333,0.333333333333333,0.333333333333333,0.333333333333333,0.333333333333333,
0.333333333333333,0.333333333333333,0.333333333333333,0.333333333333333,0.333333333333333,
0.333333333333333,0.333333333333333,0.333333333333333,0.333333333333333,0.333333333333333,
0.333333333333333,0.333333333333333,0.333333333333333,0.333333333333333,0.333333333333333,
0.333333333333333,0.333333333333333,0.333333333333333,0.333333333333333,0.333333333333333,
0.333333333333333,0.333333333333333,0.333333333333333,0.333333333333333,0.333333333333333,
0.333333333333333,0.333333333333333,0.333333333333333,0.333333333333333,0.333333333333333,
0.333333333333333,0.333333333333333,0.333333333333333,0.333333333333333,0.333333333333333,
0.333333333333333,0.333333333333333,0.333333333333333,0.333333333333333,0.333333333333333,
0.333333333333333,0.333333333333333,0.333333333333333,0.333333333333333,0.333333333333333,
0.333333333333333,0.333333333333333,0.333333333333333,0.333333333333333,0.333333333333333,
0.333333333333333,0.333333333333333,0.333333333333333,0.333333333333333,0.333333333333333,
0.333333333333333,0.333333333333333,0.333333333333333,0.333333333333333,0.333333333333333,
0.333333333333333,0.333333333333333,0.333333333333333,0.333333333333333,0.333333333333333,
0.333333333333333,0.333333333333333,0.333333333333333,0.333333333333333,0.333333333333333,
0.333333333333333,0.333333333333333,0.333333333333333,0.333333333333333,0.333333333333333,
0.333333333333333,0.333333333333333,0.333333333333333,0.333333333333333,0.333333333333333,
0.333333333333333,0.333333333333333,0.333333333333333,0.333333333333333,0.333333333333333,
0.333333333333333,0.333333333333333,0.333333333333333,0.333333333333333,0.333333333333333,
0.333333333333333,0.333333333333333,0.333333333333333,0.333333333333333,0.333333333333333,
0.333333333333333,0.333333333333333,0.333333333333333,0.333333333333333,0.333333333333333,
0.333333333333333,0.333333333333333,0.333333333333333,0.333333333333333,0.333333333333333,
0.333333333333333,0.333333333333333,0.333333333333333,0.333333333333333,0.333333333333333,
0.333333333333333,0.333333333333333,0.333333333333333,0.333333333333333,0.333333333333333,
0.333333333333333,0.333333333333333,0.333333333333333,0.333333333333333,0.333333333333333,
0.333333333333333,0.333333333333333,0.333333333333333,0.333333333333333,0.333333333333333,
0.333333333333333,0.333333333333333,0.333333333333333,0.333333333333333,0.333333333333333,
0.333333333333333,0.333333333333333,0.333333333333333,0.333333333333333,0.333333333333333,
0.333333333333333,0.333333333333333,0.333333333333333,0.333333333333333,0.333333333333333),(1.,
1.,1.,1.,1.,1.,1.,1.,1.,1.,1.,1.,1.,1.,1.,1.,1.,1.,1.,1.,1.,1.,1.,1.,1.,1.,1.,1.,1.,1.,1.,1.,1.,
1.,1.,1.,1.,1.,1.,1.,1.,1.,1.,1.,1.,1.,1.,1.,1.,1.,1.,1.,1.,1.,1.,1.,1.,1.,1.,1.,1.,1.,1.,1.,1.,
1.,1.,1.,1.,1.,1.,1.,1.,1.,1.,1.,1.,1.,1.,1.,1.,1.,1.,0.999999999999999,1.,1.,1.,1.,1.,1.,1.,1.,
1.,1.,1.,1.,1.,1.,1.,1.,1.,1.,1.,1.,1.,1.,1.,1.,1.,1.,1.,1.,1.,1.,1.,1.,1.,1.,1.,1.,1.,1.,1.,1.,
1.,1.,1.,1.,1.,1.,1.,1.,1.,1.,1.,1.,1.,1.,1.,1.,1.,1.,1.,1.,1.,1.,1.,1.,1.,1.,1.,1.,1.,1.,1.,1.,
1.,1.,1.,1.,1.,1.,1.,1.,1.,1.,1.,1.,1.,1.,1.,1.,1.,1.,1.,1.,1.,1.,1.,1.,1.,1.,1.,1.,1.,1.,1.,1.,
1.,1.,1.,1.,1.,1.,1.),(0.333333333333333,0.333333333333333,0.333333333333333,0.333333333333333,
0.333333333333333,0.333333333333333,0.333333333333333,0.333333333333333,0.333333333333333,
0.333333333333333,0.333333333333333,0.333333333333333,0.333333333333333,0.333333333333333,
0.333333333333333,0.333333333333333,0.333333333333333,0.333333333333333,0.333333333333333,
0.333333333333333,0.333333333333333,0.333333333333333,0.333333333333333,0.333333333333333,
0.333333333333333,0.333333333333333,0.333333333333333,0.333333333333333,0.333333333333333,
0.333333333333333,0.333333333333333,0.333333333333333,0.333333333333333,0.333333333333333,
0.333333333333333,0.333333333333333,0.333333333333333,0.333333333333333,0.333333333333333,
0.333333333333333,0.333333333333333,0.333333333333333,0.333333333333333,0.333333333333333,
0.333333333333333,0.333333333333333,0.333333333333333,0.333333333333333,0.333333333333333,
0.333333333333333,0.333333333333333,0.333333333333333,0.333333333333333,0.333333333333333,
0.333333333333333,0.333333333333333,0.333333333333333,0.333333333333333,0.333333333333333,
0.333333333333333,0.333333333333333,0.333333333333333,0.333333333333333,0.333333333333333,
0.333333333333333,0.333333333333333,0.333333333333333,0.333333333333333,0.333333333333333,
0.333333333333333,0.333333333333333,0.333333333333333,0.333333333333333,0.333333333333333,
0.333333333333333,0.333333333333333,0.333333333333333,0.333333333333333,0.333333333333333,
0.333333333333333,0.333333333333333,0.333333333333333,0.333333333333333,0.333333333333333,
0.333333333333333,0.333333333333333,0.333333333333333,0.333333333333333,0.333333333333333,
0.333333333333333,0.333333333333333,0.333333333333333,0.333333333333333,0.333333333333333,
0.333333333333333,0.333333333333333,0.333333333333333,0.333333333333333,0.333333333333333,
0.333333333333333,0.333333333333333,0.333333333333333,0.333333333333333,0.333333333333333,
0.333333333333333,0.333333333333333,0.333333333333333,0.333333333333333,0.333333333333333,
0.333333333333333,0.333333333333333,0.333333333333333,0.333333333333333,0.333333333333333,
0.333333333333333,0.333333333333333,0.333333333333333,0.333333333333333,0.333333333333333,
0.333333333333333,0.333333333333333,0.333333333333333,0.333333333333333,0.333333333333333,
0.333333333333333,0.333333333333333,0.333333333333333,0.333333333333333,0.333333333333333,
0.333333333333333,0.333333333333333,0.333333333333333,0.333333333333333,0.333333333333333,
0.333333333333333,0.333333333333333,0.333333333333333,0.333333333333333,0.333333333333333,
0.333333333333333,0.333333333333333,0.333333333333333,0.333333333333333,0.333333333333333,
0.333333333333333,0.333333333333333,0.333333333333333,0.333333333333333,0.333333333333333,
0.333333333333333,0.333333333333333,0.333333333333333,0.333333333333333,0.333333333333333,
0.333333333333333,0.333333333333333,0.333333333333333,0.333333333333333,0.333333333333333,
0.333333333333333,0.333333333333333,0.333333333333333,0.333333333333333,0.333333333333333,
0.333333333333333,0.333333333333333,0.333333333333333,0.333333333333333,0.333333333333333,
0.333333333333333,0.333333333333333,0.333333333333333,0.333333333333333,0.333333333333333,
0.333333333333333,0.333333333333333,0.333333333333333,0.333333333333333,0.333333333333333,
0.333333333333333,0.333333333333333,0.333333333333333,0.333333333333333,0.333333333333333,
0.333333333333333,0.333333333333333,0.333333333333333,0.333333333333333,0.333333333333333,
0.333333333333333,0.333333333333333,0.333333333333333,0.333333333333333,0.333333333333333,
0.333333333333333),(0.333333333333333,0.333333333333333,0.333333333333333,0.333333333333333,
0.333333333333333,0.333333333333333,0.333333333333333,0.333333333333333,0.333333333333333,
0.333333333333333,0.333333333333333,0.333333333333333,0.333333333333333,0.333333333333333,
0.333333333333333,0.333333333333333,0.333333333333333,0.333333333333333,0.333333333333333,
0.333333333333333,0.333333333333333,0.333333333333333,0.333333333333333,0.333333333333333,
0.333333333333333,0.333333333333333,0.333333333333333,0.333333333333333,0.333333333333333,
0.333333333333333,0.333333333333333,0.333333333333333,0.333333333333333,0.333333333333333,
0.333333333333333,0.333333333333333,0.333333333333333,0.333333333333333,0.333333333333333,
0.333333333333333,0.333333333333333,0.333333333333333,0.333333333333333,0.333333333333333,
0.333333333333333,0.333333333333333,0.333333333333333,0.333333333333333,0.333333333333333,
0.333333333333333,0.333333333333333,0.333333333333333,0.333333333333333,0.333333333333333,
0.333333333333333,0.333333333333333,0.333333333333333,0.333333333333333,0.333333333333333,
0.333333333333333,0.333333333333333,0.333333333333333,0.333333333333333,0.333333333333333,
0.333333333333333,0.333333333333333,0.333333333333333,0.333333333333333,0.333333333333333,
0.333333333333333,0.333333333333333,0.333333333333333,0.333333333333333,0.333333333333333,
0.333333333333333,0.333333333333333,0.333333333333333,0.333333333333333,0.333333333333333,
0.333333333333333,0.333333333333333,0.333333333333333,0.333333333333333,0.333333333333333,
0.333333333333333,0.333333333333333,0.333333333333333,0.333333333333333,0.333333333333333,
0.333333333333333,0.333333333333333,0.333333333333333,0.333333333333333,0.333333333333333,
0.333333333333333,0.333333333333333,0.333333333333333,0.333333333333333,0.333333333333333,
0.333333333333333,0.333333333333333,0.333333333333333,0.333333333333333,0.333333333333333,
0.333333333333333,0.333333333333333,0.333333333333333,0.333333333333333,0.333333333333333,
0.333333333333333,0.333333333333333,0.333333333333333,0.333333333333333,0.333333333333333,
0.333333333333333,0.333333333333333,0.333333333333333,0.333333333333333,0.333333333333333,
0.333333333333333,0.333333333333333,0.333333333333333,0.333333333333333,0.333333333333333,
0.333333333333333,0.333333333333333,0.333333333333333,0.333333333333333,0.333333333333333,
0.333333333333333,0.333333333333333,0.333333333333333,0.333333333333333,0.333333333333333,
0.333333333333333,0.333333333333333,0.333333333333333,0.333333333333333,0.333333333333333,
0.333333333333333,0.333333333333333,0.333333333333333,0.333333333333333,0.333333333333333,
0.333333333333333,0.333333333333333,0.333333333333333,0.333333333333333,0.333333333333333,
0.333333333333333,0.333333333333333,0.333333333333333,0.333333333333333,0.333333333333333,
0.333333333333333,0.333333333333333,0.333333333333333,0.333333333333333,0.333333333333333,
0.333333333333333,0.333333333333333,0.333333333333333,0.333333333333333,0.333333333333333,
0.333333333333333,0.333333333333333,0.333333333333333,0.333333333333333,0.333333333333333,
0.333333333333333,0.333333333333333,0.333333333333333,0.333333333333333,0.333333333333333,
0.333333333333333,0.333333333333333,0.333333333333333,0.333333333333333,0.333333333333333,
0.333333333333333,0.333333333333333,0.333333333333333,0.333333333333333,0.333333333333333,
0.333333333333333,0.333333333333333,0.333333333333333,0.333333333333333,0.333333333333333,
0.333333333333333,0.333333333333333,0.333333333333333,0.333333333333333,0.333333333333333,
0.333333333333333),(1.,1.,1.,1.,1.,1.,1.,1.,1.,1.,1.,1.,1.,1.,1.,1.,1.,1.,1.,1.,1.,1.,1.,1.,1.,
1.,1.,1.,1.,1.,1.,1.,1.,1.,1.,1.,1.,1.,1.,1.,1.,1.,1.,1.,1.,1.,1.,1.,1.,1.,1.,1.,1.,1.,1.,1.,1.,
1.,1.,1.,1.,1.,1.,1.,1.,1.,1.,1.,1.,1.,1.,1.,1.,1.,1.,1.,1.,1.,1.,1.,1.,1.,1.,0.999999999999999,
1.,1.,1.,1.,1.,1.,1.,1.,1.,1.,1.,1.,1.,1.,1.,1.,1.,1.,1.,1.,1.,1.,1.,1.,1.,1.,1.,1.,1.,1.,1.,1.,
1.,1.,1.,1.,1.,1.,1.,1.,1.,1.,1.,1.,1.,1.,1.,1.,1.,1.,1.,1.,1.,1.,1.,1.,1.,1.,1.,1.,1.,1.,1.,1.,
1.,1.,1.,1.,1.,1.,1.,1.,1.,1.,1.,1.,1.,1.,1.,1.,1.,1.,1.,1.,1.,1.,1.,1.,1.,1.,1.,1.,1.,1.,1.,1.,
1.,1.,1.,1.,1.,1.,1.,1.,1.,1.,1.,1.,1.,1.,1.))) REPRESENTATION_ITEM('') SURFACE());
#1385=CARTESIAN_POINT('',(-3.24999999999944,-5.62916512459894,16.9999999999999));
#1386=DIRECTION('',(0.866018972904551,-0.500011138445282,1.12598632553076E-09));
#1387=DIRECTION('',(8.75472222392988E-05,0.000151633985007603,0.999999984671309));
#1388=AXIS2_PLACEMENT_3D('',#1385,#1386,#1387);
#1389=CIRCLE('',#1388,0.75);
#1390=CARTESIAN_POINT('',(-3.24993433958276,-5.62905139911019,17.7499999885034));
#1391=VERTEX_POINT('',#1390);
#1392=EDGE_CURVE('E66',#1391,#1391,#1389,.T.);
#1393=CARTESIAN_POINT('',(6.5,0.,0.));
#1394=DIRECTION('',(0.,1.,0.));
#1395=DIRECTION('',(0.,0.,1.));
#1396=AXIS2_PLACEMENT_3D('',#1393,#1394,#1395);
#1397=CIRCLE('',#1396,0.75);
#1398=CARTESIAN_POINT('',(5.7544181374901,0.,-0.0812876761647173));
#1399=VERTEX_POINT('',#1398);
#1400=CARTESIAN_POINT('',(7.24558186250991,0.,-0.0812876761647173));
#1401=VERTEX_POINT('',#1400);
#1402=EDGE_CURVE('E38',#1399,#1401,#1397,.T.);
#1403=CARTESIAN_POINT('',(7.24558186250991,0.,-0.0812876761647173));
#1404=CARTESIAN_POINT('',(7.24047667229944,0.0824135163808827,-0.0812876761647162));
#1405=CARTESIAN_POINT('',(7.23531316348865,0.164829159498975,-0.0812876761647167));
#1406=CARTESIAN_POINT('',(7.22420609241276,0.329783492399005,-0.0812876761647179));
#1407=CARTESIAN_POINT('',(7.21826088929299,0.412322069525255,-0.0812876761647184));
#1408=CARTESIAN_POINT('',(7.20493843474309,0.577348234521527,-0.0812876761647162));
#1409=CARTESIAN_POINT('',(7.19756015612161,0.659835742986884,-0.0812876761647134));
#1410=CARTESIAN_POINT('',(7.18069721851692,0.824714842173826,-0.0812876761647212));
#1411=CARTESIAN_POINT('',(7.17120966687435,0.907106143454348,-0.0812876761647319));
#1412=CARTESIAN_POINT('',(7.14947657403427,1.07147196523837,-0.0812876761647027));
#1413=CARTESIAN_POINT('',(7.13723312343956,1.15344675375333,-0.0812876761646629));
#1414=CARTESIAN_POINT('',(7.11630145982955,1.27595178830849,-0.0812876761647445));
#1415=CARTESIAN_POINT('',(7.10889820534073,1.3167026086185,-0.0812876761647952));
#1416=CARTESIAN_POINT('',(7.09317556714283,1.39802882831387,-0.0812876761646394));
#1417=CARTESIAN_POINT('',(7.08485613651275,1.43860421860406,-0.0812876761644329));
#1418=CARTESIAN_POINT('',(7.0565946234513,1.56920029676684,-0.0812876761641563));
#1419=CARTESIAN_POINT('',(7.03490842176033,1.65885008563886,-0.0812876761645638));
#1420=CARTESIAN_POINT('',(6.98744886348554,1.8370607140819,-0.0812876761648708));
#1421=CARTESIAN_POINT('',(6.9616748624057,1.92562137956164,-0.0812876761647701));
#1422=CARTESIAN_POINT('',(6.87856325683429,2.18971542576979,-0.0812876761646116));
#1423=CARTESIAN_POINT('',(6.81547719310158,2.36347537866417,-0.0812876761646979));
#1424=CARTESIAN_POINT('',(6.71098913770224,2.61997428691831,-0.081287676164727));
#1425=CARTESIAN_POINT('',(6.67451752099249,2.70478196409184,-0.0812876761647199));
#1426=CARTESIAN_POINT('',(6.59834424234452,2.87293582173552,-0.0812876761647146));
#1427=CARTESIAN_POINT('',(6.55864261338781,2.95628201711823,-0.0812876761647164));
#1428=CARTESIAN_POINT('',(6.43472077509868,3.2037910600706,-0.0812876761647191));
#1429=CARTESIAN_POINT('',(6.34562710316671,3.36556351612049,-0.0812876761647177));
#1430=CARTESIAN_POINT('',(6.20149226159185,3.60379324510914,-0.0812876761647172));
#1431=CARTESIAN_POINT('',(6.15119377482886,3.68316247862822,-0.0812876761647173));
#1432=CARTESIAN_POINT('',(6.0472799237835,3.83969625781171,-0.0812876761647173));
#1433=CARTESIAN_POINT('',(5.99366469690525,3.91686089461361,-0.0812876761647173));
#1434=CARTESIAN_POINT('',(5.82795943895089,4.14486892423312,-0.0812876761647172));
#1435=CARTESIAN_POINT('',(5.71101116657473,4.29222422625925,-0.0812876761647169));
#1436=CARTESIAN_POINT('',(5.46494598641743,4.57653444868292,-0.0812876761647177));
#1437=CARTESIAN_POINT('',(5.33582134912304,4.7134826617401,-0.0812876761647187));
#1438=CARTESIAN_POINT('',(5.06620436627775,4.97584572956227,-0.0812876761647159));
#1439=CARTESIAN_POINT('',(4.92570645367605,5.10125487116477,-0.0812876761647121));
#1440=CARTESIAN_POINT('',(4.63555413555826,5.33845430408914,-0.0812876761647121));
#1441=CARTESIAN_POINT('',(4.48598365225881,5.45034722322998,-0.0812876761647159));
#1442=CARTESIAN_POINT('',(4.17758216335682,5.66054025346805,-0.0812876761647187));
#1443=CARTESIAN_POINT('',(4.01875220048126,5.75884189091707,-0.0812876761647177));
#1444=CARTESIAN_POINT('',(3.69323994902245,5.94038102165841,-0.0812876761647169));
#1445=CARTESIAN_POINT('',(3.52657919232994,6.02365708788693,-0.0812876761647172));
#1446=CARTESIAN_POINT('',(3.1861500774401,6.17394362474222,-0.0812876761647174));
#1447=CARTESIAN_POINT('',(3.01238748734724,6.24096700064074,-0.0812876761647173));
#1448=CARTESIAN_POINT('',(2.75556041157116,6.3251556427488,-0.0812876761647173));
#1449=CARTESIAN_POINT('',(2.6748183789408,6.3495527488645,-0.0812876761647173));
#1450=CARTESIAN_POINT('',(2.5122398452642,6.3943515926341,-0.0812876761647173));
#1451=CARTESIAN_POINT('',(2.43040358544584,6.41475419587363,-0.0812876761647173));
#1452=CARTESIAN_POINT('',(2.26564535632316,6.45122587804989,-0.0812876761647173));
#1453=CARTESIAN_POINT('',(2.18272199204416,6.46728866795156,-0.0812876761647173));
#1454=CARTESIAN_POINT('',(2.01608762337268,6.49447817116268,-0.0812876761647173));
#1455=CARTESIAN_POINT('',(1.93237704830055,6.50560743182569,-0.0812876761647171));
#1456=CARTESIAN_POINT('',(1.80634937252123,6.51781517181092,-0.0812876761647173));
#1457=CARTESIAN_POINT('',(1.76424524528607,6.52113718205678,-0.0812876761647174));
#1458=CARTESIAN_POINT('',(1.67990873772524,6.52604869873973,-0.0812876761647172));
#1459=CARTESIAN_POINT('',(1.63767630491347,6.52763736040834,-0.081287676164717));
#1460=CARTESIAN_POINT('',(1.55336981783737,6.52870317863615,-0.0812876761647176));
#1461=CARTESIAN_POINT('',(1.51129588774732,6.52818962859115,-0.0812876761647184));
#1462=CARTESIAN_POINT('',(1.42727930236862,6.52443807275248,-0.0812876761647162));
#1463=CARTESIAN_POINT('',(1.38533655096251,6.52120326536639,-0.0812876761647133));
#1464=CARTESIAN_POINT('',(1.3283621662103,6.51385588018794,-0.0812876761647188));
#1465=CARTESIAN_POINT('',(1.31309399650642,6.51159360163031,-0.0812876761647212));
#1466=CARTESIAN_POINT('',(1.28265694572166,6.50631571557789,-0.0812876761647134));
#1467=CARTESIAN_POINT('',(1.26748828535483,6.50329879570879,-0.0812876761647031));
#1468=CARTESIAN_POINT('',(1.23771039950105,6.4963364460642,-0.0812876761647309));
#1469=CARTESIAN_POINT('',(1.22309621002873,6.49241292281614,-0.0812876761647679));
#1470=CARTESIAN_POINT('',(1.19434072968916,6.48319064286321,-0.0812876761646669));
#1471=CARTESIAN_POINT('',(1.1801980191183,6.47789653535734,-0.0812876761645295));
#1472=CARTESIAN_POINT('',(1.1562078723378,6.46658289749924,-0.0812876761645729));
#1473=CARTESIAN_POINT('',(1.14615002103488,6.4610499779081,-0.0812876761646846));
#1474=CARTESIAN_POINT('',(1.13209518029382,6.45110878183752,-0.0812876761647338));
#1475=CARTESIAN_POINT('',(1.12755504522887,6.44749117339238,-0.0812876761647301));
#1476=CARTESIAN_POINT('',(1.11913401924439,6.43957040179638,-0.0812876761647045));
#1477=CARTESIAN_POINT('',(1.11525040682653,6.43527021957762,-0.0812876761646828));
#1478=CARTESIAN_POINT('',(1.1080365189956,6.42509181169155,-0.0812876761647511));
#1479=CARTESIAN_POINT('',(1.10488969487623,6.41907172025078,-0.0812876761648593));
#1480=CARTESIAN_POINT('',(1.10096021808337,6.40623669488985,-0.0812876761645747));
#1481=CARTESIAN_POINT('',(1.10018934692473,6.39941797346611,-0.0812876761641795));
#1482=CARTESIAN_POINT('',(1.10104200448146,6.38490782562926,-0.0812876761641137));
#1483=CARTESIAN_POINT('',(1.1030673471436,6.37725081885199,-0.0812876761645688));
#1484=CARTESIAN_POINT('',(1.1084404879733,6.3639558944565,-0.0812876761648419));
#1485=CARTESIAN_POINT('',(1.11152060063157,6.35819190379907,-0.0812876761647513));
#1486=CARTESIAN_POINT('',(1.11845765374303,6.34713609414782,-0.0812876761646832));
#1487=CARTESIAN_POINT('',(1.12231702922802,6.34184583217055,-0.0812876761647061));
#1488=CARTESIAN_POINT('',(1.13285973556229,6.32875557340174,-0.0812876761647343));
#1489=CARTESIAN_POINT('',(1.13989691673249,6.32124805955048,-0.0812876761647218));
#1490=CARTESIAN_POINT('',(1.15460365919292,6.30691238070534,-0.0812876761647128));
#1491=CARTESIAN_POINT('',(1.16227301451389,6.30008399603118,-0.0812876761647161));
#1492=CARTESIAN_POINT('',(1.17806433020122,6.28686132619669,-0.0812876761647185));
#1493=CARTESIAN_POINT('',(1.18618905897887,6.2804703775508,-0.0812876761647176));
#1494=CARTESIAN_POINT('',(1.20270333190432,6.26805187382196,-0.081287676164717));
#1495=CARTESIAN_POINT('',(1.21109276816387,6.26202417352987,-0.0812876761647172));
#1496=CARTESIAN_POINT('',(1.23919652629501,6.2424964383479,-0.0812876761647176));
#1497=CARTESIAN_POINT('',(1.25931383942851,6.22957949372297,-0.081287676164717));
#1498=CARTESIAN_POINT('',(1.30005581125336,6.20456718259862,-0.0812876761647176));
#1499=CARTESIAN_POINT('',(1.32068077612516,6.19247232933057,-0.0812876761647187));
#1500=CARTESIAN_POINT('',(1.38304373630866,6.15690979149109,-0.0812876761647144));
#1501=CARTESIAN_POINT('',(1.42521180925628,6.13420102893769,-0.0812876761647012));
#1502=CARTESIAN_POINT('',(1.50985308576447,6.08960089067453,-0.0812876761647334));
#1503=CARTESIAN_POINT('',(1.55232547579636,6.06770791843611,-0.0812876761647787));
#1504=CARTESIAN_POINT('',(1.63735006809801,6.02416856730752,-0.0812876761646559));
#1505=CARTESIAN_POINT('',(1.67990216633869,6.00252198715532,-0.081287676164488));
#1506=CARTESIAN_POINT('',(1.80783740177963,5.93722737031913,-0.081287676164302));
#1507=CARTESIAN_POINT('',(1.89313444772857,5.89340832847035,-0.0812876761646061));
#1508=CARTESIAN_POINT('',(2.06279383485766,5.8039878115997,-0.0812876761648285));
#1509=CARTESIAN_POINT('',(2.14715620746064,5.75838639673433,-0.0812876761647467));
#1510=CARTESIAN_POINT('',(2.31455766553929,5.66479193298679,-0.0812876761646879));
#1511=CARTESIAN_POINT('',(2.39759667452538,5.61679874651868,-0.0812876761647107));
#1512=CARTESIAN_POINT('',(2.56203408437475,5.51808019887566,-0.0812876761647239));
#1513=CARTESIAN_POINT('',(2.64343246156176,5.46735479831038,-0.0812876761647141));
#1514=CARTESIAN_POINT('',(2.88476744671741,5.31079163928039,-0.0812876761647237));
#1515=CARTESIAN_POINT('',(3.04188713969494,5.20054314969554,-0.0812876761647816));
#1516=CARTESIAN_POINT('',(3.34697978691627,4.96791972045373,-0.0812876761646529));
#1517=CARTESIAN_POINT('',(3.4949493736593,4.84554035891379,-0.0812876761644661));
#1518=CARTESIAN_POINT('',(3.78179643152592,4.587353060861,-0.081287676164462));
#1519=CARTESIAN_POINT('',(3.92055043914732,4.45140744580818,-0.0812876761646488));
#1520=CARTESIAN_POINT('',(4.18554623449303,4.16786306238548,-0.0812876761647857));
#1521=CARTESIAN_POINT('',(4.31179036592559,4.02026648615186,-0.0812876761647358));
#1522=CARTESIAN_POINT('',(4.55049459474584,3.7141608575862,-0.0812876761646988));
#1523=CARTESIAN_POINT('',(4.66294859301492,3.55564702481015,-0.0812876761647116));
#1524=CARTESIAN_POINT('',(4.82031309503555,3.31066290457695,-0.0812876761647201));
#1525=CARTESIAN_POINT('',(4.87089005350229,3.22778349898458,-0.0812876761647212));
#1526=CARTESIAN_POINT('',(4.96809357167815,3.05974179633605,-0.0812876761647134));
#1527=CARTESIAN_POINT('',(5.01472048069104,2.97457970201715,-0.0812876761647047));
#1528=CARTESIAN_POINT('',(5.11519651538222,2.78045167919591,-0.0812876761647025));
#1529=CARTESIAN_POINT('',(5.16790531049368,2.67089453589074,-0.0812876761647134));
#1530=CARTESIAN_POINT('',(5.26698282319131,2.4489408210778,-0.0812876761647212));
#1531=CARTESIAN_POINT('',(5.31335113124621,2.3365440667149,-0.081287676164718));
#1532=CARTESIAN_POINT('',(5.37815651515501,2.16614723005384,-0.081287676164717));
#1533=CARTESIAN_POINT('',(5.39896958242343,2.10904028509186,-0.0812876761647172));
#1534=CARTESIAN_POINT('',(5.43899242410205,1.99426952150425,-0.0812876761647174));
#1535=CARTESIAN_POINT('',(5.45820222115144,1.93660571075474,-0.0812876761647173));
#1536=CARTESIAN_POINT('',(5.51326232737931,1.76278573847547,-0.0812876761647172));
#1537=CARTESIAN_POINT('',(5.54654616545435,1.64579369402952,-0.0812876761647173));
#1538=CARTESIAN_POINT('',(5.59062512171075,1.46889933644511,-0.0812876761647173));
#1539=CARTESIAN_POINT('',(5.60434166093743,1.40971115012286,-0.0812876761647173));
#1540=CARTESIAN_POINT('',(5.62971593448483,1.29089397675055,-0.0812876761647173));
#1541=CARTESIAN_POINT('',(5.64137378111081,1.23126501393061,-0.0812876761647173));
#1542=CARTESIAN_POINT('',(5.6624516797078,1.11165110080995,-0.0812876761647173));
#1543=CARTESIAN_POINT('',(5.67187313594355,1.05166639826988,-0.0812876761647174));
#1544=CARTESIAN_POINT('',(5.6885434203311,0.9313985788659,-0.0812876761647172));
#1545=CARTESIAN_POINT('',(5.6957922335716,0.871115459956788,-0.0812876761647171));
#1546=CARTESIAN_POINT('',(5.70694248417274,0.765800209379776,-0.0812876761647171));
#1547=CARTESIAN_POINT('',(5.71122596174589,0.720807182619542,-0.0812876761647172));
#1548=CARTESIAN_POINT('',(5.71900269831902,0.630751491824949,-0.0812876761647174));
#1549=CARTESIAN_POINT('',(5.72249592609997,0.585688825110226,-0.0812876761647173));
#1550=CARTESIAN_POINT('',(5.72886444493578,0.495515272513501,-0.0812876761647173));
#1551=CARTESIAN_POINT('',(5.73173966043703,0.450404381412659,-0.0812876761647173));
#1552=CARTESIAN_POINT('',(5.73703470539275,0.360259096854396,-0.0812876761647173));
#1553=CARTESIAN_POINT('',(5.73945555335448,0.315224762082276,-0.0812876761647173));
#1554=CARTESIAN_POINT('',(5.74401792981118,0.22515036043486,-0.0812876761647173));
#1555=CARTESIAN_POINT('',(5.74615950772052,0.180110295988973,-0.0812876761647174));
#1556=CARTESIAN_POINT('',(5.75033063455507,0.0900462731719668,-0.0812876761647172));
#1557=CARTESIAN_POINT('',(5.75236023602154,0.0450223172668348,-0.0812876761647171));
#1558=CARTESIAN_POINT('',(5.7544181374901,0.,-0.0812876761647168));
#1559=B_SPLINE_CURVE_WITH_KNOTS('',3,(#1403,#1404,#1405,#1406,#1407,#1408,#1409,#1410,#1411,
#1412,#1413,#1414,#1415,#1416,#1417,#1418,#1419,#1420,#1421,#1422,#1423,#1424,#1425,#1426,#1427,
#1428,#1429,#1430,#1431,#1432,#1433,#1434,#1435,#1436,#1437,#1438,#1439,#1440,#1441,#1442,#1443,
#1444,#1445,#1446,#1447,#1448,#1449,#1450,#1451,#1452,#1453,#1454,#1455,#1456,#1457,#1458,#1459,
#1460,#1461,#1462,#1463,#1464,#1465,#1466,#1467,#1468,#1469,#1470,#1471,#1472,#1473,#1474,#1475,
#1476,#1477,#1478,#1479,#1480,#1481,#1482,#1483,#1484,#1485,#1486,#1487,#1488,#1489,#1490,#1491,
#1492,#1493,#1494,#1495,#1496,#1497,#1498,#1499,#1500,#1501,#1502,#1503,#1504,#1505,#1506,#1507,
#1508,#1509,#1510,#1511,#1512,#1513,#1514,#1515,#1516,#1517,#1518,#1519,#1520,#1521,#1522,#1523,
#1524,#1525,#1526,#1527,#1528,#1529,#1530,#1531,#1532,#1533,#1534,#1535,#1536,#1537,#1538,#1539,
#1540,#1541,#1542,#1543,#1544,#1545,#1546,#1547,#1548,#1549,#1550,#1551,#1552,#1553,#1554,#1555,
#1556,#1557,#1558),.UNSPECIFIED.,.F.,.F.,(4,2,2,2,2,2,2,2,2,2,2,2,2,2,2,2,2,2,2,2,2,2,2,2,2,2,2,
2,2,2,2,2,2,2,2,2,2,2,2,2,2,2,2,2,2,2,2,2,2,2,2,2,2,2,2,2,2,2,2,2,2,2,2,2,2,2,2,2,2,2,2,2,2,2,2,
2,2,4),(0.,0.247723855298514,0.495976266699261,0.744407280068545,0.993181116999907,
1.24176686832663,1.36601069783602,1.49026089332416,1.76684912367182,2.04348100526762,
2.59731278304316,2.87421669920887,3.15111778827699,3.70447057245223,3.98629632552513,
4.2681104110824,4.8317463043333,5.39574243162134,5.960016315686,6.51969311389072,
7.07930700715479,7.63746318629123,8.19517470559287,8.44813824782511,8.7010469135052,
8.95432013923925,9.20746243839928,9.33414095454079,9.46088118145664,9.58706172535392,
9.71309417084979,9.75938562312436,9.80575814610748,9.85110963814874,9.89630926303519,
9.93055664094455,9.94791732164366,9.96520417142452,9.9852133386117,10.005321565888,
10.0286393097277,10.0481761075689,10.0677749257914,10.098568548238,10.1293521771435,
10.1603491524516,10.1913336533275,10.2630108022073,10.3347322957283,10.4783812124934,
10.6217324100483,10.7649566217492,11.0526312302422,11.3402961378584,11.6279776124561,
11.9156632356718,12.4908868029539,13.0663208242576,13.6483417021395,14.2302533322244,
14.8124214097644,15.1036118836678,15.3947765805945,15.7593028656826,16.1238526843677,
16.3061760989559,16.4884969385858,16.8531150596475,17.0353573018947,17.2175895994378,
17.3997071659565,17.5818259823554,17.7174083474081,17.8529960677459,17.9886003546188,
18.1238969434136,18.2591695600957,18.3943781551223),.UNSPECIFIED.);
#1560=EDGE_CURVE('E49',#1401,#1399,#1559,.T.);
#1561=ORIENTED_EDGE('',*,*,#1392,.F.);
#1562=EDGE_LOOP('',(#1561));
#1563=FACE_BOUND('',#1562,.T.);
#1564=ORIENTED_EDGE('',*,*,#1402,.T.);
#1565=ORIENTED_EDGE('',*,*,#1560,.T.);
#1566=EDGE_LOOP('',(#1564,#1565));
#1567=FACE_BOUND('',#1566,.T.);
#1568=ADVANCED_FACE('F28',(#1563,#1567),#1384,.T.);
#1569=CARTESIAN_POINT('',(0.,0.,0.));
#1570=DIRECTION('',(0.,0.,1.));
#1571=DIRECTION('',(1.,0.,0.));
#1572=AXIS2_PLACEMENT_3D('',#1569,#1570,#1571);
#1573=TOROIDAL_SURFACE('',#1572,6.5,0.75);
#1574=CARTESIAN_POINT('',(0.,0.,-0.0812876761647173));
#1575=DIRECTION('',(0.,0.,-1.));
#1576=DIRECTION('',(-1.,0.,0.));
#1577=AXIS2_PLACEMENT_3D('',#1574,#1575,#1576);
#1578=CIRCLE('',#1577,7.24558186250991);
#1579=CARTESIAN_POINT('',(-3.62279093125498,-6.27485795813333,-0.0812876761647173));
#1580=VERTEX_POINT('',#1579);
#1581=EDGE_CURVE('E45',#1401,#1580,#1578,.T.);
#1582=ORIENTED_EDGE('',*,*,#1581,.F.);
#1583=ORIENTED_EDGE('',*,*,#1402,.F.);
#1584=CARTESIAN_POINT('',(0.,0.,-0.0812876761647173));
#1585=DIRECTION('',(0.,0.,1.));
#1586=DIRECTION('',(1.,0.,0.));
#1587=AXIS2_PLACEMENT_3D('',#1584,#1585,#1586);
#1588=CIRCLE('',#1587,5.75441813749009);
#1589=CARTESIAN_POINT('',(-2.87720906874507,-4.98347229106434,-0.0812876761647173));
#1590=VERTEX_POINT('',#1589);
#1591=EDGE_CURVE('E55',#1590,#1399,#1588,.T.);
#1592=ORIENTED_EDGE('',*,*,#1591,.F.);
#1593=CARTESIAN_POINT('',(-3.25000000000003,-5.62916512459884,0.));
#1594=DIRECTION('',(-0.866025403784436,0.500000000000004,0.));
#1595=DIRECTION('',(0.,0.,-1.));
#1596=AXIS2_PLACEMENT_3D('',#1593,#1594,#1595);
#1597=CIRCLE('',#1596,0.75);
#1598=EDGE_CURVE('E62',#1580,#1590,#1597,.T.);
#1599=ORIENTED_EDGE('',*,*,#1598,.F.);
#1600=EDGE_LOOP('',(#1582,#1583,#1592,#1599));
#1601=FACE_BOUND('',#1600,.T.);
#1602=ADVANCED_FACE('F61',(#1601),#1573,.T.);
#1603=CARTESIAN_POINT('',(-3.25000000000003,-5.62916512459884,0.));
#1604=DIRECTION('',(-0.866025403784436,0.500000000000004,0.));
#1605=DIRECTION('',(0.,0.,-1.));
#1606=AXIS2_PLACEMENT_3D('',#1603,#1604,#1605);
#1607=PLANE('',#1606);
#1608=ORIENTED_EDGE('',*,*,#1598,.T.);
#1609=DIRECTION('',(-0.500000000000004,-0.866025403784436,0.));
#1610=VECTOR('',#1609,1.);
#1611=CARTESIAN_POINT('',(-3.25000000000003,-5.62916512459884,-0.0812876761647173));
#1612=LINE('',#1611,#1610);
#1613=EDGE_CURVE('E11',#1590,#1580,#1612,.T.);
#1614=ORIENTED_EDGE('',*,*,#1613,.T.);
#1615=EDGE_LOOP('',(#1608,#1614));
#1616=FACE_BOUND('',#1615,.T.);
#1617=ADVANCED_FACE('F65',(#1616),#1607,.T.);
#1618=CARTESIAN_POINT('',(-3.24999999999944,-5.62916512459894,16.9999999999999));
#1619=DIRECTION('',(0.866018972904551,-0.500011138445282,1.12598632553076E-09));
#1620=DIRECTION('',(8.75472222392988E-05,0.000151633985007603,0.999999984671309));
#1621=AXIS2_PLACEMENT_3D('',#1618,#1619,#1620);
#1622=PLANE('',#1621);
#1623=ORIENTED_EDGE('',*,*,#1392,.T.);
#1624=EDGE_LOOP('',(#1623));
#1625=FACE_BOUND('',#1624,.T.);
#1626=ADVANCED_FACE('F85',(#1625),#1622,.T.);
#1627=CARTESIAN_POINT('',(-43.0839814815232,-5.57931837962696,-0.0812876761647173));
#1628=DIRECTION('',(0.,0.,-1.));
#1629=DIRECTION('',(-1.,0.,0.));
#1630=AXIS2_PLACEMENT_3D('',#1627,#1628,#1629);
#1631=PLANE('',#1630);
#1632=ORIENTED_EDGE('',*,*,#1560,.F.);
#1633=ORIENTED_EDGE('',*,*,#1581,.T.);
#1634=ORIENTED_EDGE('',*,*,#1613,.F.);
#1635=ORIENTED_EDGE('',*,*,#1591,.T.);
#1636=EDGE_LOOP('',(#1632,#1633,#1634,#1635));
#1637=FACE_BOUND('',#1636,.T.);
#1638=ADVANCED_FACE('F54',(#1637),#1631,.T.);
#1639=CLOSED_SHELL('',(#1568,#1602,#1617,#1626,#1638));
#1640=MANIFOLD_SOLID_BREP('B2',#1639);
#1641=ADVANCED_BREP_SHAPE_REPRESENTATION('',(#18,#1640),#14);
#1642=SHAPE_DEFINITION_REPRESENTATION(#9,#1641);
ENDSEC;
END-ISO-10303-21;
